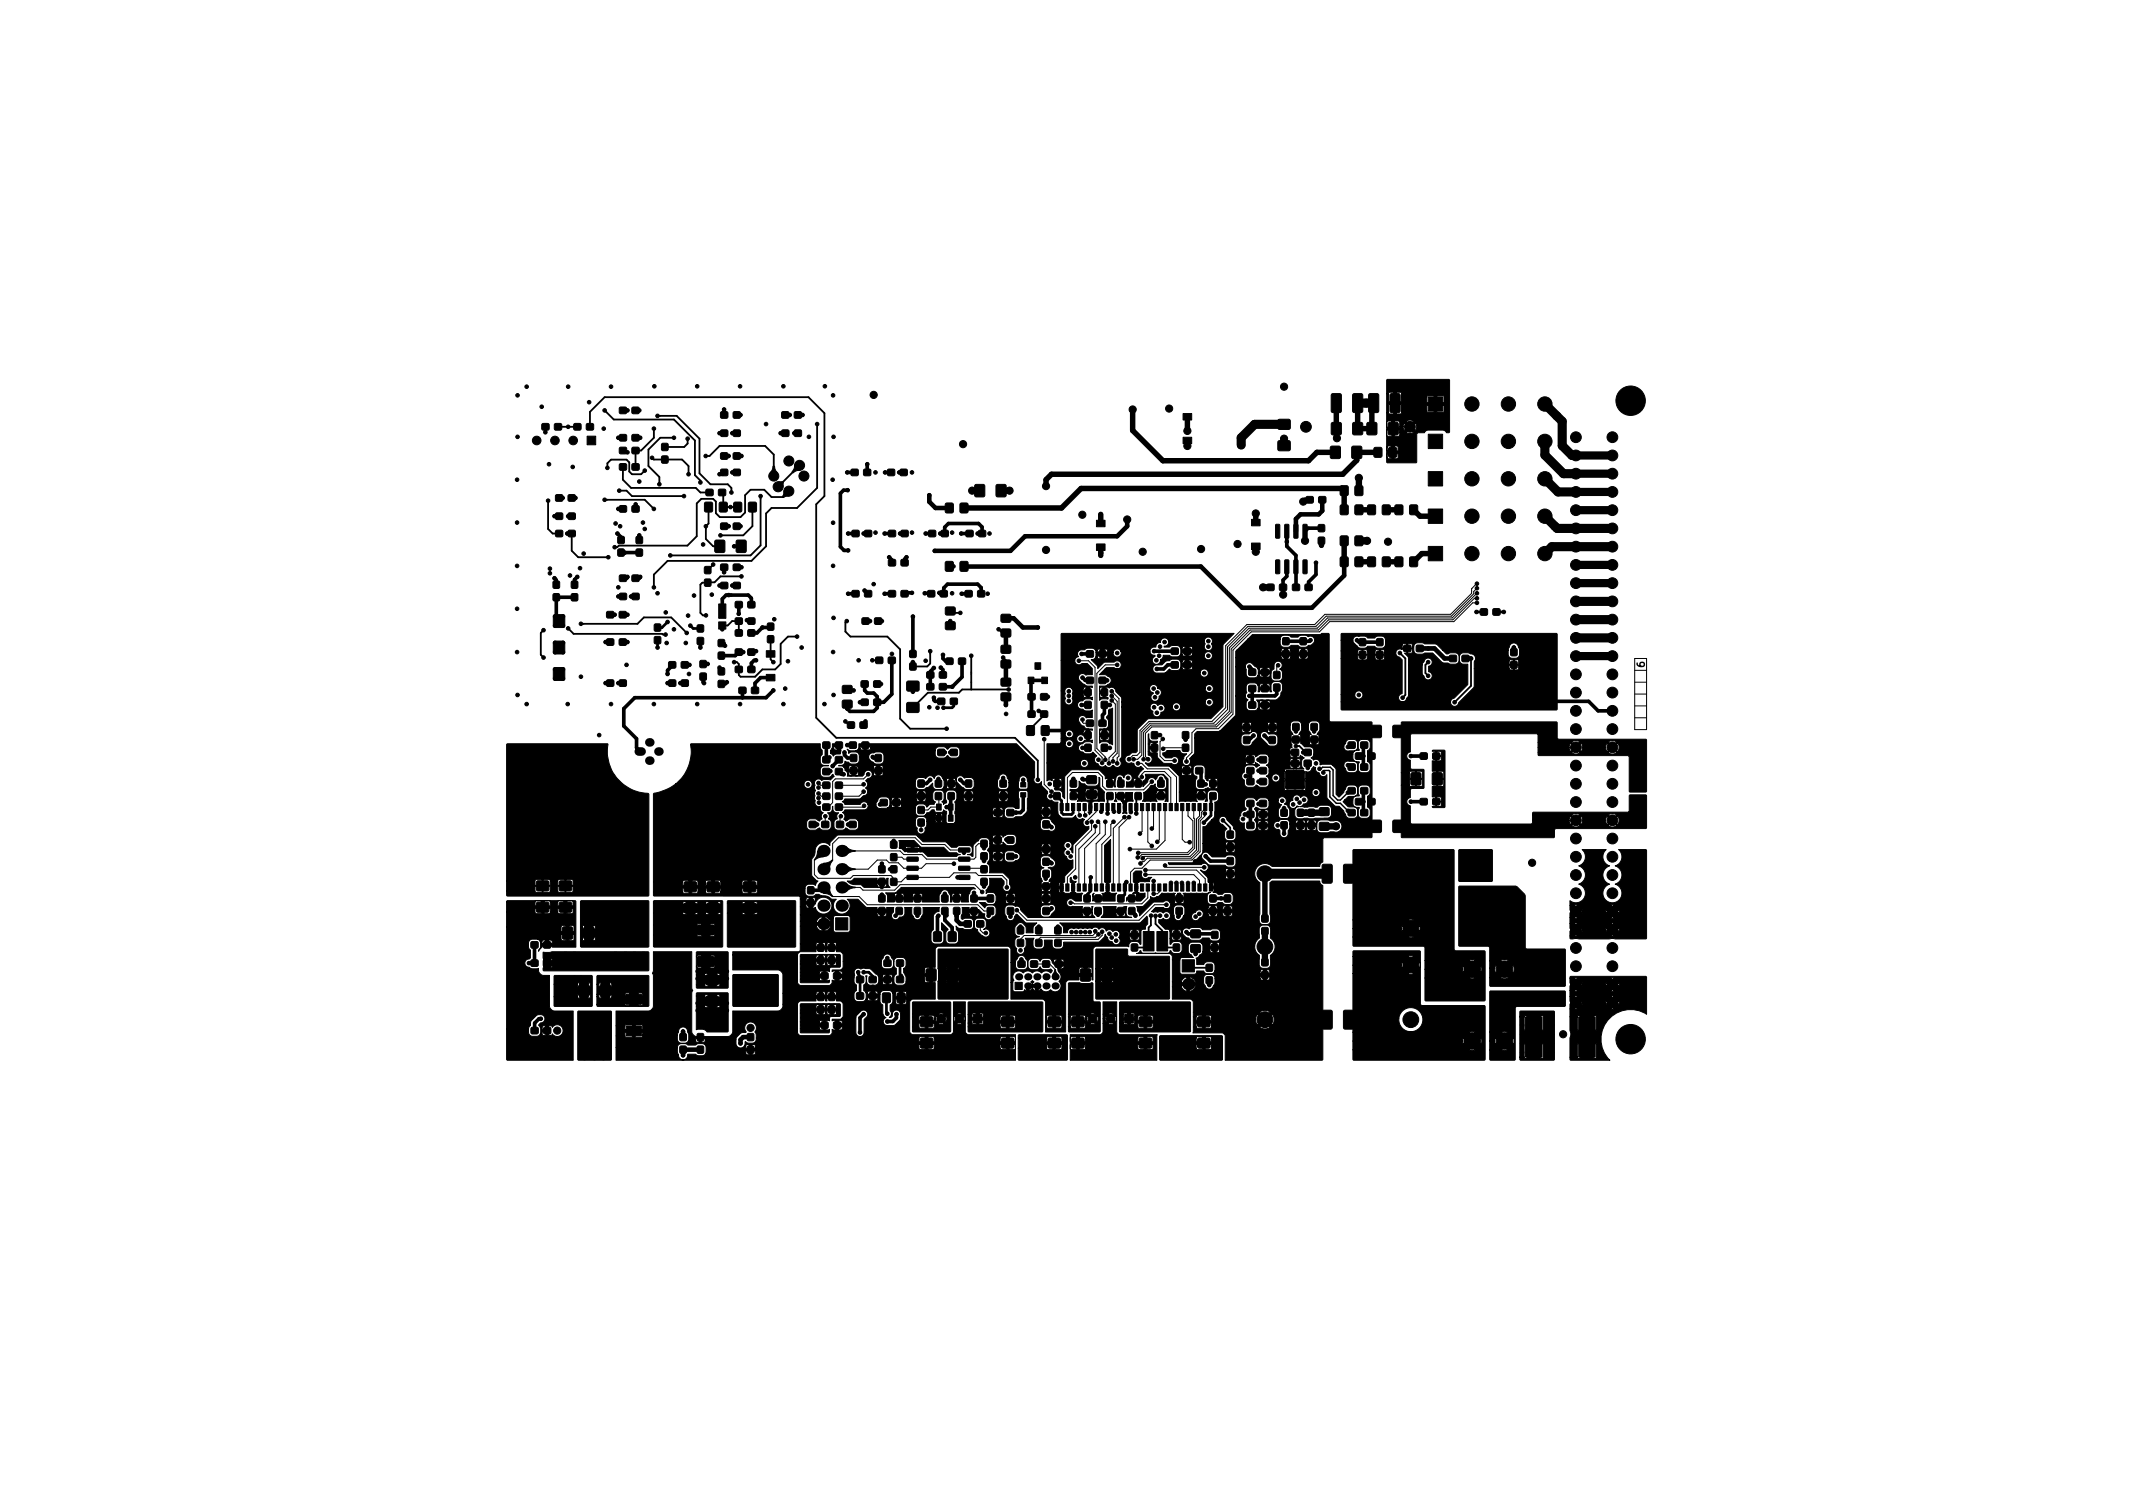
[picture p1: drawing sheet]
<svg xmlns="http://www.w3.org/2000/svg" width="297mm" height="210mm" viewBox="0 0 297 210" stroke-linecap="round" stroke-linejoin="round" font-family="sans-serif">
<defs><g id="words">
<text font-size="1.4" x="229" y="92.9" transform="rotate(-90 229 92.9)">6</text>
</g></defs>
<g fill="#000" stroke="#000" stroke-width=".14">
<path d="M75.5 59h.9l.1 .2-.1 .6-.2 .1h-.7l-.1-.2zM77.3 59h.8l.1 .2v.6l-.2 .1h-.7l-.1-.2zM79.9 59h.9l.1 .2v.6l-.2 .1h-.7l-.1-.2zM81.7 59h.9l.1 .2-.1 .6-.2 .1h-.7l-.1-.2zM86.3 56.7h.9l.1 .2-.1 .6-.2 .1h-.7l-.1-.2zM88 56.7h.9l.1 .2v.6l-.2 .1h-.7l-.1-.2zM100.4 59.9h.9l.1 .2-.1 .6-.2 .1-.7-.1-.1-.1zM100.4 57.4h.9l.1 .1-.1 .7-.2 .1-.7-.1-.1-.2zM102.1 59.9h.9l.1 .2v.6l-.2 .1-.7-.1-.1-.1zM102.1 57.4h.9l.1 .1v.7l-.2 .1-.7-.1-.1-.2zM108.9 59.9h.9l.1 .2-.1 .6-.2 .1-.7-.1-.1-.1zM108.9 57.4h.9l.1 .1-.1 .7-.2 .1-.7-.1-.1-.2z"/>
<path d="M110.7 59.9h.8l.1 .2v.6l-.2 .1-.7-.1-.1-.1zM110.7 57.4h.8l.1 .1v.7l-.2 .1-.7-.1-.1-.2zM164.8 57.6h1.2v.9h-1.2zM178 58.4h.2h1.4l.1 .2-.1 1.1-.2 .1-1.4-.1-.1-.2zM185.5 58.9l1.1-.1 .1 .1 .1 1.4-.1 .2-1.1 .1-.2-.1v-1.4zM185.5 54.9l1.1-.1 .2 .2v2.2l-.2 .2-1 .1-.2-.2zM188.4 58.9l1.1-.1 .2 .1 .1 1.4-.1 .2-1.1 .1-.2-.1v-1.4zM188.4 54.9l1.2-.1 .2 .2v2.2l-.2 .2-1 .1-.2-.2zM190.4 58.9l1.1-.1 .2 .1 .1 1.4-.1 .2-1.1 .1-.2-.1-.1-1.4zM190.7 54.9l1.1-.1 .2 .2v2.2l-.1 .2-1.1 .1-.2-.2zM193.4 58.9l1.1-.1 .2 .1v1.4l-.1 .2-1 .1-.2-.1-.1-1.4zM193.6 54.9l1.2-.1 .2 .2v2.2l-.2 .2-1 .1-.2-.2z"/>
<path d="M198.9 55.3h2v2h-2zM193.1 52.9l.1-.1h8.6l.1 .1v7.3l-.1 .1h-.4l-.2-.3-.3-.1h-2l-.3 .1-.2 .3h-1l-.1 .1v4h-.1h-4h-.1v-.7l.2 .2h.4v-.7h.4l.1 .7h.4l.1-.2v-.5h-1.5l-.1 .5v-1.4l.1 .5h.5v-.7h.4v.7h.6v-.5l-.2-.2h-1.2l-.2 .2v-1.7l.2 .1h.5v-.8h.4l.1 .8h.6v-.5h1l.4 .2 .5-.2-.5-.5-.4 .5h-1v-.3h-1.7l-.1 .7v-1.8l.1 .7h.6v-.8h.4v.8l1.2-.1 .2 .5 .5-.5h.5l.5 .5 .2-.4-.2-.6-.5 .5h-.5l-.5-.5-.2 .5h-.5v-.7h1l.4 .5 .5-.5-.2-.2h-.4l-.3 .2-2.6-.1-.2 .2v-1.3h.3l.1 .1h.6v-1.3h.4v1.3h.6l.1-.3h3.5l.2 .1h.8v-1h.4v1h.8l.2-.1v-.8l-2.3-.1-.1 .9h-3.5l-.1-1h-1.7v1.2h-.3v-2.7h.3v1.1h.7v-1.2h.4v1.2h.6l.1-.6h3.5l.1 .8h.9v-1h.4v1h.9l.1-.9-.2-.1h-2l-.2 .2h-3.5v-.5l-.2-.2h-1.5l-.1 .2h-.3zM77.4 68.9h.9l.1 .2-.1 .6-.1 .1h-.8l-.1-.2zM77.4 71.5h.9l.1 .1-.1 .7-.1 .1-.8-.1-.1-.2zM77.4 73.9h.9l.1 .2-.1 .6-.1 .1-.8-.1-.1-.2zM79.2 68.9h.9v.2v.6l-.2 .1h-.7l-.1-.2zM79.2 71.5h.9v.1v.7l-.2 .1-.7-.1-.1-.2zM79.2 73.9h.9v.2v.6l-.2 .1-.7-.1-.1-.2zM81.8 60.7h1.2v1.2h-1.2zM86.1 76.5l.6-.1 .2 .1 .1 .7-.1 .2-.7 .1-.1-.1zM86.1 74.7h.6l.2 .1 .1 .7-.1 .2h-.7l-.1-.1zM86.3 60.5h.9l.1 .2-.1 .6-.2 .1h-.7l-.1-.2z"/>
<path d="M86.3 70.5l.9-.1 .1 .2-.1 .6-.2 .1h-.7l-.1-.2zM86.3 62.3h.9l.1 .2-.1 .6-.2 .1h-.7l-.1-.2zM86.3 64.6h.9l.1 .2-.1 .6-.2 .1-.7-.1-.1-.1zM88 60.5h.9l.1 .2v.6l-.2 .1h-.7l-.1-.2zM88 70.5l.9-.1 .1 .2v.6l-.2 .1h-.7l-.1-.2zM88 62.3h.9l.1 .2v.6l-.2 .1h-.7l-.1-.2zM88 64.6h.9l.1 .2v.6l-.2 .1-.7-.1-.1-.1zM88.6 76.5l.7-.1 .1 .1 .1 .7-.1 .2-.6 .1-.2-.1zM88.6 74.7h.7l.1 .1 .1 .7-.1 .2h-.6l-.2-.1zM92.2 63.5h.6l.2 .1 .1 .7-.1 .2h-.7l-.1-.1zM92.2 61.8l.6-.1 .2 .1 .1 .7-.1 .2-.7 .1-.1-.1zM98.1 78.9h.7h.2v.8l-.1 .2h-.6l-.2-.1z"/>
<path d="M98.2 70l.8-.1 .2 .1v1.1v.1l-.9 .1-.1-.1-.1-1zM98.4 68.2h.8l.1 .1v.7h-.2h-.7l-.1-.2zM99.6 75.3l1.1-.1 .2 .1 .1 1.4-.1 .2h-1.1h-.2l-.1-1.5zM100.1 68.2h.9l.1 .1-.1 .7h-.2h-.7l-.1-.2zM100.2 70l.8-.1 .2 .1 .1 1.1-.1 .1-.8 .1-.2-.1-.1-1zM100.4 65.4h.9l.1 .1-.1 .7-.2 .1-.7-.1-.1-.2zM100.4 63.1h.9l.1 .2-.1 .6-.2 .1-.7-.1-.1-.2zM100.4 72.9h.9l.1 .1-.1 .7h-.2h-.7l-.1-.2zM100.4 78.6h.9l.1 .2-.1 .6-.2 .1-.7-.1-.1-.2zM102.1 65.4h.9l.1 .1v.7l-.2 .1-.7-.1-.1-.2zM102.1 63.1h.9l.1 .2v.6l-.2 .1-.7-.1-.1-.2zM102.1 72.9h.9l.1 .1v.7h-.2h-.7l-.1-.2z"/>
<path d="M102.1 78.6h.9l.1 .2v.6l-.2 .1-.7-.1-.1-.2zM102.2 70l.9-.1 .2 .1v1.1l-.1 .1-.8 .1-.2-.1v-1zM102.6 75.3l1.1-.1 .2 .1v1.4l-.1 .2h-1h-.2l-.1-1.5zM104.3 70l.8-.1 .2 .1 .1 1.1-.1 .1-.8 .1-.2-.1-.1-1zM107.6 64.9h.3l.1 .5 .2 .4-.4 .8-.5-.8 .2-.4zM108.4 67.1h.5l.2 .1v.6l-1 .2zM109.2 68.4l.9-.2-.3 .9h-.4l-.3 .2-.1-.2 .1-.3zM110.7 64.8l.9-.2-.3 .9-.4 .1-.4 .2-.2-.1 .3-.4zM118.6 65.4h.9v.1v.7l-.2 .1-.7-.1-.1-.2zM118.7 73.9h.9l.1 .2-.1 .6-.2 .1-.7-.1-.1-.2zM120.3 65.4h.9l.1 .1-.1 .7-.1 .1-.8-.1-.1-.2zM120.4 73.9h.9l.1 .2v.6l-.2 .1-.7-.1-.1-.2z"/>
<path d="M123.6 65.4h.9l.1 .1v.7l-.2 .1-.7-.1-.1-.2zM123.8 77.9h.9v.2v.6l-.2 .1h-.7l-.1-.2zM123.8 73.9h.9v.2v.6l-.2 .1-.7-.1-.1-.2zM125.4 65.4h.9l.1 .1-.1 .7-.2 .1-.7-.1-.1-.2zM125.5 77.9h.9l.1 .2-.1 .6-.1 .1h-.8l-.1-.2zM125.5 73.9h.9l.1 .2-.1 .6-.1 .1-.8-.1-.1-.2zM129.4 73.9h.8l.1 .2v.6l-.2 .1-.7-.1-.1-.2zM131.1 73.9h.9l.1 .2-.1 .6-.2 .1-.7-.1-.1-.2zM131.7 70.1l.8-.1 .2 .1 .1 1.1-.1 .2h-.8l-.2-.1-.1-1zM131.7 78.2h.8l.2 .1 .1 1-.1 .2-.8 .1-.2-.1-.1-1.1zM133.7 70.1l.9-.1 .2 .1v1.1l-.1 .2h-.8l-.2-.1v-1zM133.7 78.2h.9l.2 .1v1l-.1 .2-.8 .1-.2-.1v-1.1z"/>
<path d="M134.6 73.9h.9v.2v.6l-.2 .1-.7-.1-.1-.2zM135.8 67.5l1.1-.1 .2 .1v1.4v.2l-1.1 .1-.2-.1-.1-1.4zM136.3 73.9h.9l.1 .2-.1 .6-.1 .1-.8-.1-.1-.2zM138.8 67.5l1.1-.1 .2 .1v1.4l-.1 .2-1.1 .1-.1-.1-.1-1.4zM152.7 72.4h1.2v.9h-1.2zM152.7 75.7h1.2v.9h-1.2zM164.8 60.9h1.2v.9h-1.2zM174.3 72.3h1.2v.9h-1.2zM174.3 75.6h1.2v.9h-1.2zM177.7 78l.4-.1 .1 .2v1.7l-.1 .1h-.4l-.1-.1zM177.7 73h.4l.1 .1v1.7l-.1 .1h-.4l-.1-.1zM178.9 78l.5-.1 .1 .2v1.7l-.1 .1h-.4l-.1-.1z"/>
<path d="M178.9 73h.5l.1 .1v1.7l-.1 .1h-.4l-.1-.1zM178 61.4l.2-.1 1.4 .1 .1 .2-.1 1.1-.2 .1-1.4-.1-.1-.2zM180.2 78l.4-.1 .2 .2v1.7l-.2 .1h-.3l-.1-.1zM180.2 73h.4l.2 .1v1.7l-.2 .1h-.3l-.1-.1zM181.5 78l.4-.1 .1 .2v1.7l-.1 .1h-.3l-.2-.1zM181.5 73h.4l.1 .1v1.7l-.1 .1h-.3l-.2-.1zM181.9 69.2h.9l.1 .2v.6l-.2 .1-.8-.1v-.2zM183.6 74.8h.7l.1 .1 .1 .7-.1 .2h-.6l-.2-.1zM183.6 73.1l.7-.1 .1 .1 .1 .7-.1 .2-.6 .1-.2-.1zM183.7 69.2h.9l.1 .2-.1 .6-.2 .1-.7-.1-.1-.2zM185.3 62.2l1.1-.1 .2 .1 .1 1.4-.1 .2-1.1 .1-.2-.1v-1.4zM186.7 77.6l.8-.1 .2 .1 .1 1.1-.1 .2h-.8l-.2-.1-.1-1z"/>
<path d="M186.7 67.7l.8-.1 .2 .1 .1 1.1-.1 .2h-.8l-.2-.1-.1-1zM186.7 74.7l.8-.1 .2 .1 .1 1.1-.1 .1-.8 .1-.2-.1-.1-1zM186.7 70.4l.8-.1 .2 .1 .1 1-.1 .2-.8 .1-.2-.1-.1-1.1zM188.3 62.2l1.1-.1 .2 .1 .1 1.4-.1 .2-1.1 .1-.2-.1-.1-1.4zM188.7 77.6l.9-.1 .2 .1v1.1l-.1 .2h-.8l-.2-.1v-1zM188.7 67.7l.9-.1 .2 .1v1.1l-.1 .2h-.8l-.2-.1v-1zM188.7 74.7l.9-.1 .2 .1v1.1l-.1 .1-.8 .1-.2-.1v-1zM188.7 70.4l.9-.1 .2 .1v1l-.1 .2-.8 .1-.2-.1v-1.1zM190.5 70.4l.8-.1 .2 .1 .1 1-.1 .2-.8 .1-.2-.1-.1-1.1zM190.5 77.6l.8-.1 .2 .1 .1 1.1-.1 .2h-.8l-.2-.1-.1-1zM191.4 62.4l.8-.1 .2 .1 .1 1-.1 .2-.8 .1-.2-.1-.1-1.1zM192.5 70.4l.9-.1 .2 .1v1l-.1 .2-.8 .1-.2-.1v-1.1z"/>
<path d="M192.5 77.6l.9-.1 .2 .1v1.1l-.1 .2h-.8l-.2-.1v-1zM193.4 62.4l.9-.1 .2 .1v1l-.1 .2-.8 .1-.2-.1v-1.1zM194.3 70.4l.8-.1 .2 .1 .1 1-.1 .2-.8 .1-.2-.1-.1-1.1zM194.3 77.6l.8-.1 .2 .1 .1 1.1-.1 .2h-.8l-.2-.1-.1-1zM196.4 70.4l.8-.1 .2 .1v1l-.1 .2-.8 .1-.2-.1v-1.1zM196.4 77.6l.8-.1 .2 .1v1.1l-.1 .2h-.8l-.2-.1v-1zM198.9 76.1h2v2h-2zM198.9 70.9h2v2h-2zM198.9 65.7h2v2h-2zM198.9 60.5h2v2h-2zM77.1 82.7l.6-.1 .2 .1v.8v.1l-.7 .1-.2-.1zM77.1 81l.6-.1 .2 .1v.7v.2h-.7h-.2z"/>
<path d="M77.1 89.3h1.3l.2 .1 .1 1.4-.1 .2-1.3 .1-.2-.1v-1.5zM77.1 93l1.3-.1 .2 .1 .1 1.5-.1 .2h-1.3h-.2v-1.5zM77.1 85.7l1.3-.1 .2 .1 .1 1.4-.1 .2-1.3 .1-.2-.1v-1.5zM79.6 82.7l.6-.1 .2 .1 .1 .8-.1 .1-.6 .1-.2-.1zM79.6 81l.6-.1 .2 .1 .1 .7-.1 .2h-.6h-.2zM84.5 89h.9l.1 .2-.1 .6-.1 .1-.8-.1v-.2zM84.5 94.7h.9l.1 .2-.1 .6-.1 .1-.8-.1v-.1zM84.5 85.2h.9l.1 .2-.1 .6-.1 .1-.8-.1v-.2zM86.3 89h.9l.1 .2-.1 .6-.2 .1-.7-.1-.1-.2zM86.3 94.7h.9l.1 .2-.1 .6-.2 .1-.7-.1-.1-.1zM86.3 85.2h.9l.1 .2-.1 .6-.2 .1-.7-.1-.1-.2zM86.3 80.1h.9l.1 .2-.1 .6-.2 .1-.7-.1-.1-.2z"/>
<path d="M86.3 82.6h.9l.1 .2-.1 .6-.2 .1h-.7l-.1-.2zM88 80.1h.9l.1 .2v.6l-.2 .1-.7-.1-.1-.2zM88 82.6h.9l.1 .2v.6l-.2 .1h-.7l-.1-.2zM91.2 88.7l.6-.1 .2 .1v.7v.2l-.7 .1-.2-.1zM91.2 86.9h.6h.2v.8v.2h-.7l-.2-.1zM93.2 92.2h.9v.1v.7l-.2 .1-.7-.1-.1-.2zM93.2 94.7h.9v.2v.6l-.2 .1-.7-.1-.1-.1zM94.9 92.2h.9l.1 .1-.1 .7-.1 .1-.8-.1-.1-.2zM94.9 94.7h.9l.1 .2-.1 .6-.1 .1-.8-.1-.1-.1zM97.1 88.8l.7-.1 .2 .1v.7l-.1 .2-.6 .1-.2-.1zM97.1 87.1l.7-.1 .2 .1v.7l-.1 .2h-.6l-.2-.1zM97.5 92l.7-.1 .1 .1 .1 .8-.1 .1-.6 .1-.2-.1z"/>
<path d="M97.5 93.8l.7-.1 .1 .1 .1 .7-.1 .2h-.6h-.2zM98.1 80.7l.7-.1 .2 .1v.7l-.1 .2-.6 .1-.2-.1zM100.1 84.1h1v2h-1zM100.1 86.6h1v1h-1zM100.1 90.8h.6l.2 .1v.7l-.1 .2h-.6l-.2-.1zM100.1 89.1l.6-.1 .2 .1v.7l-.1 .2-.6 .1-.2-.1zM100.1 94.8l.6-.1 .2 .1v.7l-.1 .2-.6 .1-.2-.1zM100.1 93h.6h.2v.8l-.1 .2h-.6l-.2-.1zM100.4 81.1h.9l.1 .2-.1 .6-.2 .1-.7-.1-.1-.1zM102.1 81.1h.9l.1 .2v.6l-.2 .1-.7-.1-.1-.1zM102.4 86.1h.9l.1 .1v.7l-.2 .1-.8-.1v-.2zM102.4 92.8h.9l.1 .2v.6l-.2 .1-.8-.1v-.2z"/>
<path d="M102.4 87.7h.9l.1 .2v.6l-.2 .1h-.8v-.2zM102.4 90.4h.9l.1 .2v.6l-.2 .1-.8-.1v-.2zM102.4 83.8h.9l.1 .2v.6l-.2 .1-.8-.1v-.2zM102.9 95.7h.9l.1 .2v.6l-.2 .1h-.7l-.1-.2zM104.2 86.1h.9l.1 .1-.1 .7-.2 .1-.7-.1-.1-.2zM104.2 92.8h.9l.1 .2-.1 .6-.2 .1-.7-.1-.1-.2zM104.2 87.7h.9l.1 .2-.1 .6-.2 .1h-.7l-.1-.2zM104.2 90.4h.9l.1 .2-.1 .6-.2 .1-.7-.1-.1-.2zM104.2 83.8h.9l.1 .2-.1 .6-.2 .1-.7-.1-.1-.2zM104.7 95.7h.9l.1 .2-.1 .6-.2 .1h-.7l-.1-.2zM106.9 86.8l.7-.1 .1 .1 .1 .7-.1 .2-.6 .1-.2-.1zM106.9 88.6l.7-.1 .1 .1 .1 .7-.1 .2h-.6l-.2-.1z"/>
<path d="M106.7 90.6h1.2v.9h-1.2zM106.7 93.9h1.2v.9h-1.2zM117.4 97.5h.1h1.1l.1 .2-.1 .8-.2 .1h-1l-.1-.2zM117.4 95.5l.1-.1 1.1 .1 .1 .2-.1 .8-.2 .1-1-.1-.1-.2zM118.7 82.3h.9l.1 .1-.1 .7h-.2h-.7l-.1-.2zM120 97.4h.8l.1 .1v.7l-.2 .1-.7-.1-.1-.2zM120 94.8h.8l.1 .2v.6l-.2 .1h-.7l-.1-.2zM120.1 86.1h.9l.1 .1-.1 .7-.2 .1-.7-.1-.1-.2zM120.4 82.3h.9l.1 .1v.7h-.2h-.7l-.1-.2zM121.7 97.4h.9l.1 .1-.1 .7-.2 .1-.7-.1-.1-.2zM121.7 94.8h.9l.1 .2-.1 .6-.2 .1h-.7l-.1-.2zM121.8 86.1h.9l.1 .1v.7l-.2 .1-.8-.1v-.2z"/>
<path d="M122 91.5h.9l.1 .2-.1 .6-.2 .1h-.7l-.1-.2zM123.7 91.5h.9l.1 .2v.6l-.2 .1h-.7l-.1-.2zM123.8 82.3h.9v.1v.7h-.2h-.7l-.1-.2zM125.5 82.3h.9l.1 .1-.1 .7h-.1h-.8l-.1-.2zM126.7 92.3h.7l.1 .1 .1 .7-.1 .2h-.6l-.2-.1zM126.7 90.6l.7-.1 .1 .1 .1 .7-.1 .2-.6 .1-.2-.1zM126.3 94.9l.2-.1 1.4 .1 .1 .2-.1 1.1h-.1h-1.5v-.2zM126.3 97.9l.2-.1 1.4 .1 .1 .1-.1 1.1-.1 .1h-1.5v-.2zM129.1 93.6h.9l.1 .1-.1 .7h-.2h-.7l-.1-.2zM129.1 95.2h.9l.1 .2-.1 .6-.2 .1-.7-.1-.1-.1zM129.2 82.3h.9l.1 .1v.7h-.2h-.8v-.2zM130.6 97.3l.9-.1 .1 .2-.1 .6-.1 .1h-.8v-.2z"/>
<path d="M130.8 93.6h.9l.1 .1v.7h-.2h-.7l-.1-.2zM130.8 95.2h.9l.1 .2v.6l-.2 .1-.7-.1-.1-.1zM131 82.3h.9l.1 .1-.1 .7h-.2h-.7l-.1-.2zM131.8 91.7l.9-.1v.2v.7h-.2h-.7l-.1-.2zM131.7 86.6h.2h1l.1 .2v.8l-.2 .1-1.1-.1-.1-.1zM131.7 84.6l.2-.1 1 .1 .1 .2v.8l-.2 .1-1.1-.1-.1-.2zM132.4 97.3l.9-.1 .1 .2-.1 .6-.2 .1h-.7l-.1-.2zM133.5 91.7l.9-.1 .1 .2-.1 .7h-.1h-.8l-.1-.2zM134.4 82.3h.9l.1 .1v.7h-.2h-.8v-.2zM136.2 82.3h.9l.1 .1-.1 .7h-.2h-.7l-.1-.2zM139.5 87.6h.1h1.1l.1 .2-.1 .8-.2 .1h-1l-.1-.2zM139.5 85.6l.1-.1 1.1 .1 .1 .2-.1 .8-.2 .1-1-.1-.1-.2z"/>
<path d="M139.5 92l.1-.1h1.1l.1 .2-.1 .8-.2 .1h-1l-.1-.2zM139.5 89.9l.1-.1 1.1 .1 .1 .2-.1 .8-.2 .1-1-.1-.1-.2zM139.5 96.5h.1h1.1l.1 .2-.1 .8-.2 .1-1-.1-.1-.1zM139.5 94.5l.1-.1 1.1 .1 .1 .2-.1 .8-.2 .1-1-.1-.1-.2zM143.2 99h.9l.1 .2-.1 .6-.2 .1h-.7l-.1-.2zM143.2 96.6h.9l.1 .2-.1 .6-.2 .1-.7-.1-.1-.1zM143.2 94.3h.8v.9h-.8zM144.1 92.3h.8v.9h-.8zM144.9 99h.9l.1 .2v.6l-.2 .1h-.7l-.1-.2zM144.9 96.6h.9l.1 .2v.6l-.2 .1-.7-.1-.1-.1zM145.1 94.3h.8v.9h-.8zM151.1 95.9h.6l.2 .1 .1 .7-.1 .2h-.6l-.2-.1z"/>
<path d="M151.1 97.7l.6-.1 .2 .1 .1 .7-.1 .2-.6 .1-.2-.1zM151.3 94.3h.9l.1 .2v.6l-.2 .1h-.8v-.2zM151.3 90.6h.9l.1 .2v.6l-.2 .1h-.8v-.2zM153.1 94.3h.9l.1 .2-.1 .6-.2 .1h-.7l-.1-.2zM153.1 90.6h.9l.1 .2-.1 .6-.2 .1h-.7l-.1-.2zM153.4 95.9h.6l.2 .1 .1 .7-.1 .2h-.6l-.2-.1zM153.4 97.7l.6-.1 .2 .1 .1 .7-.1 .2-.6 .1-.2-.1zM163.1 92.2h.9l.1 .1v.7l-.2 .1-.7-.1-.1-.2zM163.1 90.3h.9l.1 .1v.7h-.2h-.7l-.1-.2zM164.9 92.2h.9l.1 .1-.1 .7-.2 .1-.7-.1-.1-.2zM164.9 90.3h.9l.1 .1-.1 .7h-.2h-.7l-.1-.2zM147.8 88.3l.1-.1h24l-1.6 1.6v8.6l-1.7 1.7h-8.7l-1.5 1.5v3l-.2 .2h-.6l-.3 .4a.59 .59 0 0 0-.6 .7 .59 .59 0 0 0 .9 .3l.3 .1a.57 .57 0 0 0 .4 .5 .57 .57 0 0 0 .6-.1l.4 .4-.6 .5-.2 .4v.4l-.6 .1-.1 .4h1.3l.1-.2a.57 .57 0 0 0 .3-.8l2.5-.1 .7 .7v3.1h-.5l.1-.2v-.4h-1.2l-.1 .4 .2 .2h-.2h-1.9l.2-.4-.1-.8 1.8-.1 .1 .4h.4v-.5h.4v.5l.4-.1v-.3l-.2-.2h-.9l-.2 .2h-1.6l1-.9 .3-.1 .2-.2a.62 .62 0 0 0 .5 .8h.6l.4-.2 .1-.9-.2-.4a.64 .64 0 0 0-.6-.5 .64 .64 0 0 0-.7 .5l-.1 .2a.57 .57 0 0 0-.7-.3 .57 .57 0 0 0-.4 .6l-.6 .6-.1-.2h-1.2l-.1 .3h-1l.1-.8a.57 .57 0 0 0 .7-.3 .57 .57 0 0 0-.4-.7 .57 .57 0 0 0-.7 .5 .62 .62 0 0 0-.7-.4 .62 .62 0 0 0-.5 .7v1h-.1v-.3h-.9l.1-.9h.3v.5h.5v-.5h-1.1l-.2 .1v-.5l-.8-.8h-3.8l-1 1v3l-.3-.3v-.3a.56 .56 0 0 0-.6-.6h-.4l-.2-.2h.2v-.5h.4v.5h.4l.1-.5h-.9v-.9h.4v.5h.4l.1-.3-.1-.2h-1.1l-.2 .1v.2l-.4-.1-.3 .1v-2.5h4.6v.1a.57 .57 0 0 0 .9 .5 .57 .57 0 0 0 0-1 .57 .57 0 0 0-.9 .4h-4.6v-2.6l2.5-.1v.1a.57 .57 0 0 0 .9 .4 .57 .57 0 0 0 0-.9 .57 .57 0 0 0-.9 .4h-.6l.1-.1v-.6h2.1a.58 .58 0 0 0 .5 .6 .58 .58 0 0 0 .6-.3l.3-.1v-.4h-.3a.57 .57 0 0 0-.6-.3 .57 .57 0 0 0-.5 .5h-2.1v-.6h.5v.1a.57 .57 0 0 0 .8 .4 .57 .57 0 0 0 .2-.9h1.5l.1 .4h.4v-.5h-.3l-.2 .1h-1.5a.57 .57 0 0 0-.6-.1 .57 .57 0 0 0-.4 .5h-.5v-6h.5l.1 .4-.1 .4 .1 .2a.57 .57 0 0 0 .1 .8 .57 .57 0 0 0 .7 0 .57 .57 0 0 0 .1-.8l.1-.3h1.4l.2 .2h.3v-.5h-.4l-.1 .3h-1.4l-.1-.3a.56 .56 0 0 0 0-.7h1.5l.1 .3h.4v-.5h-.3l-.2 .2h-1.5a.57 .57 0 0 0-.6-.2 .57 .57 0 0 0-.4 .5h-.5v-4.3h1.9v.2a.57 .57 0 0 0 .4 .4 .57 .57 0 0 0 .6-.1h.7l.7 .7v.8l-.9 .1a.58 .58 0 0 0-.8-.1 .58 .58 0 0 0-.1 .8l.5 .5 .5 .3h.8v.2h-.4v1.4h.4v.3l-.2-.1h-.6l-.5 .3a.61 .61 0 0 0-.8 .6 .61 .61 0 0 0 .8 .5l.5 .3h.6l.2-.1v1l-.8 .1a.59 .59 0 0 0-1-.2 .59 .59 0 0 0 .1 .9l.3 .3 .3 .1 .3 .4h.8v.2h-.4v1.3h.4v.4l-.2-.1h-.7l-.4 .3a.58 .58 0 0 0-.6 .6 .58 .58 0 0 0 .6 .5l.5 .3h.6l.3-.3 .5 .6a.6 .6 0 0 0-.3 .6 .6 .6 0 0 0 .5 .5 .57 .57 0 0 0 .5 .4 .57 .57 0 0 0 .5-.2 .58 .58 0 0 0 1 0h.2a.57 .57 0 0 0 .8 .1 .57 .57 0 0 0 .1-.8v-.2l.2-.4v-6.9h4v.4l.4 .3a.57 .57 0 0 0 .4 .7 .57 .57 0 0 0 .7-.6 .57 .57 0 0 0 .5-.8h1.1v.1a.57 .57 0 0 0 .8 .4 .57 .57 0 0 0 0-1 .57 .57 0 0 0-.8 .5l-1.1-.1a.57 .57 0 0 0-1-.1 .57 .57 0 0 0-.6-.3 .57 .57 0 0 0-.4 .5h-4v-.7h11.6v.1a.57 .57 0 0 0 .9 .5 .57 .57 0 0 0 0-1 .57 .57 0 0 0-.9 .4h-11.6v-.6l-.8-.8-.2-.5h4.9a.66 .66 0 0 0 .5 .7v.1a.58 .58 0 0 0-.2 .7 .58 .58 0 0 0 .7 .3 .58 .58 0 0 0 .3-.7 .6 .6 0 0 0 .3-.6 .6 .6 0 0 0-.5-.5h6.6v.1a.57 .57 0 0 0 .9 .5 .57 .57 0 0 0 0-1 .57 .57 0 0 0-.9 .4h-6.6v-.1a.57 .57 0 0 0-.6-.4 .57 .57 0 0 0-.5 .5h-4.9l-.3-.1-.4 .1-.2-.1h-.3v1.4h.3v.1v.2l-.8-.1-.4 .2v-.6l.2 .2h.3v-.5h-.4l-.1 .3v-1l.1 .3h.4v-.5h-.3l-.2 .2v-.4h.8l.4-.2a.6 .6 0 0 0 .4-.6 .6 .6 0 0 0-.5-.6l-.3-.1-.8-.1 .8-.8h6.6a.57 .57 0 0 0 .6 .6h6v.1a.57 .57 0 0 0 .9 .4 .57 .57 0 0 0 0-1 .57 .57 0 0 0-.9 .5h-4.8l.6-.6 .4 .3h.7l.4-.3h.2l.2 .1h.3v-.4h.4l.1 .4h.3l.2-.1-.1-.3h-1.3l-.1 .3h-.2v-1h.2l.1 .3h.4v-.4h.4v.4h.5l.1-.3-.2-.2h-1.1l-.2 .2h-.2l-.4-.3h-.8l-.3 .2-.6 .1-.5 .5h-.7a.57 .57 0 0 0-.6 .5h-6.6l.2-.1h1.1a.57 .57 0 0 0 .8-.1 .57 .57 0 0 0 0-.7 .57 .57 0 0 0-.8 0h-1.4l-.9 .9-.1-.4-.8-.9h.3l.3-.3h.2l.2 .2h.3v-.5h.4l.1 .5h.3l.1-.1v-.4h-1.3l-.1 .3h-.2v-.6h2.4v.1a.57 .57 0 0 0 .7 .5 .57 .57 0 0 0 .4-.8h4l.1 .1a.6 .6 0 0 0 .7 .4l-.1 .2a.58 .58 0 0 0-.3 .7 .58 .58 0 0 0 .6 .4 .58 .58 0 0 0 .5-.7 .57 .57 0 0 0 .4-.6h.9l.4 .3h.7l.4-.4h.2l.2 .2h.3v-.4h.4l.1 .4h2.1a.57 .57 0 0 0 .8 .5 .57 .57 0 0 0 .2-.9 .57 .57 0 0 0-1 .2v.2h-1.7v-.4h-1.3l-.1 .2h-.2v-.9h.2l.1 .3h.4v-.4h.4v.4h.5l.1-.3-.2-.2h-1.1l-.2 .2h-.2l-.4-.3h-.8l-.3 .2h-.8v-.1a.57 .57 0 0 0 .6-.8h5v.1a.44 .44 0 0 1 0 .7 .58 .58 0 0 0 .8 .6 .58 .58 0 0 0 .2-1 .57 .57 0 0 0-.2-.9 .57 .57 0 0 0-.8 .5h-5v-.1a.57 .57 0 0 0-.7-.2 .57 .57 0 0 0-.4 .6 .57 .57 0 0 0-.6 .6 .64 .64 0 0 0-.9 .6h-4a.57 .57 0 0 0-.6-.3 .57 .57 0 0 0-.5 .5h-2.4v-.3h.2l.1 .3h.4v-.5h.4v.5h.5v-.4l-.1-.1h-1.1l-.2 .2h-.2l-.4-.3h-.7l-.5 .2h-.4a.57 .57 0 0 0-.5 .3 .57 .57 0 0 0 .1 .6 .57 .57 0 0 0-.5 .5h-1.9z"/>
<path d="M173.9 93.2h.9l.1 .2v.6l-.2 .1-.8-.1v-.2zM173.9 97.8l.9-.1 .1 .2v.7h-.2h-.8v-.2zM173.9 95.5h.9l.1 .1v.7l-.2 .1-.8-.1v-.2zM175.7 93.2h.9l.1 .2-.1 .6-.2 .1-.7-.1-.1-.2zM175.7 97.8l.9-.1 .1 .2-.1 .7h-.2h-.7l-.1-.2zM175.7 95.5h.9l.1 .1-.1 .7-.2 .1-.7-.1-.1-.2zM176.5 81.4h.9v.1v.7l-.2 .1-.7-.1-.1-.2zM177.4 93.5h.6l.2 .1 .1 .7-.1 .2h-.6l-.2-.1zM177.4 95.3l.6-.1 .2 .1 .1 .7-.1 .2-.6 .1-.2-.1zM178.2 81.4h.9l.1 .1-.1 .7-.1 .1-.8-.1v-.2zM178.7 90.6l.6-.1 .2 .1v.7v.2l-.7 .1-.2-.1zM178.7 88.8h.6l.2 .1v.7v.2h-.7l-.2-.1z"/>
<path d="M180 81.4h.9l.1 .1v.7l-.2 .1-.8-.1v-.2zM181.1 90.6l.6-.1 .2 .1 .1 .7-.1 .2-.7 .1-.1-.1zM181.1 88.8h.6l.2 .1 .1 .7-.1 .2h-.7l-.1-.1zM181.8 81.4h.9l.1 .1-.1 .7-.2 .1-.7-.1-.1-.2zM160 102.2v.6l.2 .3 .2 .1h.8v.2l-.2 .1v1.3h.2v.7l.8 .8h1.2a.57 .57 0 0 0 .8 0 .57 .57 0 0 0 0-.8 .57 .57 0 0 0-.8 0h-.9l-.4-.4v-.3h.4l.2-.3h1.8a.55 .55 0 0 0 .6 .5h.4l-.4 .3-.1 .2a.59 .59 0 0 0 0 1 .59 .59 0 0 0 .9-.2h7.7l.2 .1h.3v-.4h-.4l-.1 .3h-7.7l.1-.3-.2-.3 .4-.4h7.4l.1 .3h.4v-.5h-.4l-.1 .2h-7.4l.4-.5v-2h6.4v.6l.2 .3 .3 .2h.5a.55 .55 0 0 0 .6-.5l.6-.7 .1-.3h.4l.1 .3 1 1.1 .9 .1 .4-.4 .1-.7a.56 .56 0 0 0-.6-.6h-.7l-.3-.3a.57 .57 0 0 0-.9 .5h-.4v-.1a.61 .61 0 0 0-.5-.5 .61 .61 0 0 0-.6 .4h-.8l-.3 .2-.1 .4h-6.4v-.6l.3-.4h6.2l.2 .2h.3v-.5h.4v.5h.4l.1-.2h2.2l.1 .2h.3l.1-.5h.4v.5h.3l.1-.1v-.4h-1.3v.3h-2.2l-.1-.3h-1.2l-.1 .3h-3.1l1.1-1h2l.1 .3h.4v-.5h.4v.5h.4l.1-.3h2.2v.3h.5v-.5h.4v.5h.4v-.2h1.9v.8l.4 .6-.3 .1v.4h1.3v-.4l-.2-.1 .3-.6 .1-.8h.9l.1 .8 .3 .6h-.2l-.1 .4 1.3 .1 .1-.4-.3-.1 .4-.6v-.8a.56 .56 0 0 0-.6-.5l-.7 .1-.3 .4h-.9a.56 .56 0 0 0-.6-.5l-.8 .1-.2 .4h-1.9v-.2l-.2-.1h-.9l-.2 .2h-2.2l-.2-.2h-1l-.2 .2h-2l1.2-1.2v-2.7h1.3l.1 .3 .3 .2-.2 .4-.1 .6a.56 .56 0 0 0 .6 .6l.7-.1 .4-.3h.2l.2 .2h.3v-.4h.4l.1 .4h.4l.1-.2-.1-.2h-1.3l-.1 .2h-.2v-.9h.2l.1 .3h.4v-.5h.4v.5h.5l.1-.3-.1-.2h-1.2l-.2 .2h-.2l-.2-.2h2.5l.4-.1 .4-.5 .1-.4 .2-.4v-.6a.56 .56 0 0 0-.6-.6h-.5l-.4 .2-.1 .4 .1 .8h-.2l-.1-.2h-1.3l-.1 .2h-.2v-.9h.2l.1 .3h.4v-.4h.4v.4h.5v-.3l-.1-.2h-1.1l-.2 .2h-.2l-.4-.3h-.9l-.3 .4v.7v.2l-.2 .5h-1.3v-4.1h1.3l.2 .4v.8l.4 .4h.8l.4-.3h.2l.2 .2h.3v-.5h.4l.1 .5 .3-.1 .1-.1v-.3h-1.3l-.1 .3h-.2v-.4h1.8v.6a.56 .56 0 0 0 .6 .5h.7l.3-.3v-.9l-.3-.5a.58 .58 0 0 0 .2-.7 .58 .58 0 0 0-.8-.3 .58 .58 0 0 0-.3 .8v.3l-.3 .2-.1 .3h-1.8v-.6h.2l.1 .3h.4v-.4h.4v.4h.5v-.4l-.1-.1h-1.1l-.2 .2h-.2l-.9-.7a.57 .57 0 0 0-.9 .4h-1.3v-1.2h6.3l.1 .1 .3 .1 .1-.6h.4v.6l.3-.1 .1-.1h1.1l.1 .1 .3 .1 .1-.6h.4v.6l.3-.1 .1-.1v-.4h-1.2l-.1 .4h-1.1v-.4h-1.2l-.1 .4h-6.3v-.9l.1-.2h6.2l.1 .3h.4v-.4h.4v.4h.4v-.3h1.1l.1 .3h.4v-.4h.4v.4h.4v-.4l-.1-.1h-1l-.2 .2h-1.1l-.2-.2h-.9l-.2 .2h-6.2l1.6-1.5h4.5v.8l.4 .3h.7l.4-.2h1l.3 .2h.8a.61 .61 0 0 1 .7-.3 .62 .62 0 0 0 .5-.8 .62 .62 0 0 0-.9-.3l-.4-.2-.6-.1-.3 .1-.1 .2h-1l-.4-.2-.6-.1-.4 .2-.1 .4h-4.5l.6-.6h9.3l.4-.2h.9l.1 .1v12l.2 .2h5.7l.1 .1v16h-.1l-6.6 .1-.2 .1v3.2l-.3 .3-.1 .3h-6.7a1.42 1.42 0 0 0-2.1 .2 1.42 1.42 0 0 0 .5 2.1v4.4l-.1 .9a.56 .56 0 0 0 .5 .5h.7l.3-.4-.1-5.4 .3-.2h6.7a.57 .57 0 0 0 .4 .6v24.2l-.1 .1h-13.5v-3.3l-.2-.4-.2-.1h-4.1l.1-.8h.4l.1 .2h.7v-.7h.4l.1 .7h.7l.1-.2h6.7a1.08 1.08 0 0 0 1.5 0l-.8-.8-.7 .8h-6.7v-.5h-2.1v.5h-.4v-1.4h.4v.5h.8v-.7h.4v.7h.9v-.2h6.2a.99 .99 0 0 0 .2 .8l.8-.7h.5l.8 .7 .1-.1 .1-.5a.99 .99 0 0 0-.2-.9l-.8 .8h-.5l-.8-.8-.1 .2-.1 .5h-6.2v-.4l-.2-.1h-1.7l-.2 .2h-.4v-.6h9.2l.7 .7 .8-.7a1.08 1.08 0 0 0-1.5 0h-9.2v-1.5l-.3-.3-2.6-.1v-1.7h1.2l.3 .4 .3 .2h.2v-.8h.4v.8l.5-.2 .3-.4v-.2h-2v.2h-1.2v-.7h1.2v.1h.8v-.7h.4v.7h.8l-.1-.2-.3-.4h1.5v.7l.2 .3a.64 .64 0 0 0 .6 .5 .64 .64 0 0 0 .6-.5l.2-.3v-.6h6.3l.1 .1 .3 .1 .1-.6h.3v.5l.3 .1 .2-.2v-.3l-1.3-.1v.4l-6.3-.1a.56 .56 0 0 0-.6-.5l-.7 .1-.3 .4h-1.5a1.04 1.04 0 0 0-1.6 .5h-1.2v-3.1h1v1.7l.2 .3 1.9 .1a.36 .36 0 0 0 .3-.5h.9l.3 .3 .3 .1h.7l.3-.4h6.3v.4h.5v-.5h.3v.5l.5-.1v-.4l-.2-.1h-1l-.1 .2h-6.3v-.8l-.3-.4-.8-.1-.3 .2-.2 .2h-.9l-.1-.7-.1-.2a.57 .57 0 0 0 .6-.4l.2-.2 .2-.3h1l.1 .1h.3l.1-.5h.4v.5h.3l.1-.1v-.4h-1.3v.4h-1v-.9l-.1-.2h1.1v.3h.5v-.4h.4v.4h5.3a1.4 1.4 0 0 0 .7 1.3v1.3a.56 .56 0 0 0 .5 .5h.6l.3-.2 .1-.3v-1.3l.2-.1a1.42 1.42 0 0 0-.2-2.3v-1.2a.56 .56 0 0 0-.5-.6h-.6l-.4 .3v.3v1.2l-.2 .1a1.42 1.42 0 0 0-.5 1h-4.9v-.4l-.1-.1h-1l-.2 .2h-1.1l-.3-.2h-1.1a.57 .57 0 0 0-.5 .6v.8l.7 .7h-1.6l-.2 .1-.1 .2h-1l-.1-.5-.3-.3h-4.6l.2-.1 .3-.3h.1l.1 .2 .2 .1h1.7h1.7l.2-.1 .1-.2h.2l.3 .3 .7 .1a.56 .56 0 0 0 .5-.6v-.8l-.3-.3h-.8l-.3 .2-.1 .2h-.2v-.8h.3l.1 .2h.3v-.5h.4l.1 .5h.3l.1-.2-.1-.3h-1.2v.3h-.3v-1h.3v.3h.4v-.5h.4v.5h.4l.1-.2h.2v.3l.4 .3 .4 .2 .4 .3h1.2l.4-.3h.9l.2 .3 .3 .1h.6l.3-.1 .1-.3 .1-.7a.56 .56 0 0 0-.6-.6h-.6l-.2 .2h-1.1l-.4-.3-1.1-.1-.4 .3a.57 .57 0 0 0-.6-.1 .57 .57 0 0 0-.3 .5h-.2v-.2l-.2-.1h-1l-.1 .2h-.3l-.2-.3h-.4l-.9-.9v-.5h.3l.3-.1a.57 .57 0 0 0 .8 0 .57 .57 0 0 0 0-.8 .57 .57 0 0 0-.8 0 .62 .62 0 0 0-.8-.1h-.3h-.3l-.2-.1 .3-.3h2.7v.6l.1 .3a.63 .63 0 0 0 .6 .7 .63 .63 0 0 0 .7-.6h1.1a.58 .58 0 0 0 .5 .6 .58 .58 0 0 0 .7-.4l.3-.1 .2-.3h.6l.2 .2h.3v-.6h.4v.6h.4l.1-.2h.7l.1 .2h.3l.1-.6h.3v.5l.4 .1 .1-.1v-.4l-1.3-.1v.4h-.7l-.1-.4h-1.2l-.1 .4h-.6v-.1a.58 .58 0 0 0-.5-.6 .58 .58 0 0 0-.7 .4l-.3 .2-.2 .3h-1.1l.2-.4-.1-.9h3.3l.1 .4h.4v-.5h.4v.5h.4l.1-.4h.7v.4h.5v-.5h.3v.5h.5v-.4l-.2-.2h-1l-.1 .2h-.7l-.2-.2h-1l-.2 .2h-3.3l-.2-.2-.7-.1a.56 .56 0 0 0-.6 .6h-2.7l.2-.2h1.2a.57 .57 0 0 0 .7 0 .57 .57 0 0 0 .1-.8h.6l.2 .2h.3v-.5h.4v.5h.3l.2-.1v-.4h-1.3l-.1 .3h-.6a.57 .57 0 0 0-.9 0l-1.4 .1-1.9 1.8-.1-.4-.2-.3-.1-.6h.9l1-1v-.4a.69 .69 0 0 0 1 0h.2l.4-.5 1.9 .1-.2 .1 .1 .4h.4v-.5l.2-.1 .2 .1v.5h.4l.1-.4-.2-.1 .3-.1 3.1 .1 .2-.2 .3 .1-.2 .1-.2 .2-.1 .8a.56 .56 0 0 0 .6 .5h.6l.3-.2h.6l.4 .2h.8l.3-.3v-.8a.56 .56 0 0 0-.5-.5h-.6l-.4 .2h-.6l-.2-.2h-.5l.2-.2v-.3h-.7v-.4l.1-.5h.3v.5l.3-.1-.1-.3-.1-.1h-.4l-.3-.1v-.6h2.5l.1 .1 .3 .1v-.6h.4v.5l.3 .1 .2-.2-.1-.4h-1.2v.4h-2.5l-1-1h.1a.57 .57 0 0 0 .8-.1h2.6v.4h.4v-.5h.4v.5l.5-.1v-.4l-.2-.1h-1l-.1 .2h-2.6a.57 .57 0 0 0 0-.8 .57 .57 0 0 0-.8 .1h-4.5l-.1-.3h3.4l1-.9h.2l.2 .4 .8 .8 2.3 .1 .4 .2h.6l.3-.1 .2-.2v-.8a.56 .56 0 0 0-.5-.5h-.6l-.4 .2h-1.8l-.6-.6a.57 .57 0 0 0-.9 .5h-.2l.4-.4v-.3h3.2l.1 .2h.3v-.5h.4l.1 .5h.3l.1-.2-.1-.3h-1.2v.3h-3.2v-1.1h3.2v.4h.4v-.5h.4v.5h.4l.1-.4-.2-.2-1 .1-.1 .1h-3.2v-2.3a.56 .56 0 0 0 .7-.4l.5-.5h1a.57 .57 0 0 0 .5 .6l.7 .6-.3 .3-.1 .8a.56 .56 0 0 0 .6 .6l.6-.1 .3-.1 .1-.3v-.7l-.1-.3-.2-.2-.1-.4-.8-.8-.1-.2h1.7v.1a.57 .57 0 0 0 .8 .5v.8l.4 .3h.8l.4-.3h.3l.1 .2h.3l.1-.5h.4v.5h.3l.2-.1-.1-.4h-1.3v.3h-.3l.1-.5h2.4v.1a.64 .64 0 0 0 .7 .5l.1 .1 .1 .6a.57 .57 0 0 0 .6 .4 .57 .57 0 0 0 .5-.5v-.5l.2-.2h.8l.2 .2h.3v-.5h.4v.5h.4l.1-.2h.2l.1 .2h.3v-.5h.4l.1 .5h.3l.1-.1-.1-.4h-1.2v.3h-.2l-.1-.3h-1.2l-.1 .3h-.8v-.7h3.8v.7a.57 .57 0 0 0 .6 .6l1.8-.2a.82 .82 0 0 0 1.1-.8 .82 .82 0 0 0-1.2-.7l-1.7-.1a.57 .57 0 0 0-.6 .5h-3.8v-.3h.8l.1 .3h.4v-.5h.4v.5h.4l.1-.3h.2v.3h.4v-.5h.4v.5h.4l.1-.3-.2-.2h-1l-.1 .2h-.2l-.2-.2h-1l-.2 .2h-.8l-.3-.3h-.7l-.3 .1-.2 .2a.57 .57 0 0 0-.7 .5h-2.4l-.1-.4h.3v.2h.5v-.4h.4v.4h.4l.1-.3-.1-.1h-1.2l-.1 .2h-.3l-.2-.4 .2-.2h.3l.1 .2h.3l.1-.5h.4v.4l.3 .1 .2-.1v-.4h-1.4v.3h-.3v-1h.3v.3h.5v-.4h.4v.4h.4l.1-.3-.2-.2h-1l-.2 .2h-.3l-.2-.3a.27 .27 0 0 1 .2-.2 .27 .27 0 0 1 .3 .1l.3 .2 .9-.1 .3-.4v-.8h1.3l.1 .5 .4 .2-.4 .6-.1 .8a.56 .56 0 0 0 .6 .5h.7l.3-.3v-1l-.3-.5-.4-.2h.6a.57 .57 0 0 0 .5 .6 .57 .57 0 0 0 .6-.4l.3 .1a.56 .56 0 0 0-.6 .6l.1 .8 .4 .3 4.1-.1a.57 .57 0 0 0 .5-.6v-.7l-.3-.4-1.3-.1-.3 .3-2.5-.1 .3-.1 .2-.3a.57 .57 0 0 0 .6-.8 .57 .57 0 0 0-1 0 .57 .57 0 0 0-.7-.4 .57 .57 0 0 0-.3 .7 .57 .57 0 0 0-.6 .6l-.6-.1a.57 .57 0 0 0-.1-.9 .57 .57 0 0 0-.8 .4h-1.3l-.3-.3h-.8l-.3 .1-.4 .3-.3-.4h-.8a.56 .56 0 0 0-.5 .5v.6l.2 .4a.33 .33 0 0 1-.4 .3 .75 .75 0 0 0-.4 .7l-.2 .4h-1.7a.57 .57 0 0 0-.6-.3 .57 .57 0 0 0-.5 .5h-1l.4-.6 .1-1.9a.56 .56 0 0 0 .5-.6l-.1-.8h13.1v.1a.57 .57 0 0 0 .9 .4 .57 .57 0 0 0 0-.9 .57 .57 0 0 0-.9 .4h-13.1l-.2-.3h-.7a.56 .56 0 0 0-.6 .6v1h-.3l.1-.2v-.4h-1.3v.4l.2 .2h-.2h-2.4v-1.3h2.4v.4h.5v-.5h.3v.5h.5v-.4l-.1-.2h-1l-.2 .2h-2.4v-2.2l-.2-.3h.5l.1 .2h.4l.1-.5h.3v.4l.4 .1 .1-.1 .1-.4h-1.4l-.1 .3h-.5l-1-1h1.5l.1 .3h.5v-.4h.3v.4h.7l.1 .7 .2 .2 .3 .1v.3l-.2 .3v.7a.56 .56 0 0 0 .5 .5h.6l.6-.2 .2 .1h.3v-.5h.4v.5h.3l.2-.1-.1-.4h-.8v-.9h.4v.5h.5l-.1-.5h-1.1l-.1 .1-.1 .3-.2-.1-.2-.3v-.3h5.1l.1 .3 .3 .2 .1 .8 .4 .2h.8l.3-.3 .6 .3h.9l.3-.4v-.7l-.1-.2h.5v.1a.57 .57 0 0 0 .9 .4 .57 .57 0 0 0 0-1 .57 .57 0 0 0-.9 .5h-.5l-.3-.2 .4-.3v-.4h2.1l.1 2.6 2.8 .1 .1-.3v-2.4a.59 .59 0 0 0 .9-.4l.2-.3 .3 .2a.59 .59 0 0 0 .5 .7 .57 .57 0 0 0 .5 .5 .57 .57 0 0 0 .6-.2v3.2l1.1 1.1 .6 .1 .6 .6 .3 .5a.56 .56 0 0 0 .5 .5h.7l.3-.1 .2-.3v-.6a.56 .56 0 0 0-.6-.5l-.8-.1-.7-.7 .3-.2h1.1v.6a.67 .67 0 0 0 .9 .4l-.2 .4v.6a.56 .56 0 0 0 .6 .5h.8l.2-.2 .1-.3v-.7l-.4-.3v-1.5l.4-.3v-.8l-.3-.4-.8-.1a.56 .56 0 0 0-.6 .6v.5l.2 .4a.67 .67 0 0 0-.9 .5v.1h-1.1l.4-.5h.8a.56 .56 0 0 0 .6-.6v-.5l-.2-.3-.3-.2h-.7a.64 .64 0 0 0-.6 .6l-.2 .4-.6 .7-.4-.4v-3.5l-.6-.6h1.6l.1 .3 .2 .2a.56 .56 0 0 0 .5 .6h.7l.3-.2 .2-.3v-.5a.56 .56 0 0 0-.6-.6h-.6a.57 .57 0 0 0-.8 .5h-3.3a.57 .57 0 0 0-.2-.7 .57 .57 0 0 0-.7 0l-.3-.3 .3-.2v-.3h5.5v.6a.67 .67 0 0 0 .9 .5l-.2 .4v.5a.56 .56 0 0 0 .6 .6h.8l.2-.3 .1-.3v-.6l-.4-.4v-1.5l.4-.3v-.8l-.3-.4h-.8a.56 .56 0 0 0-.6 .5v.6l.2 .4a.67 .67 0 0 0-.9 .4v.1h-5.5v-.5a.56 .56 0 0 0-.5-.5h-.8h5.5v.1a.59 .59 0 0 0 .8 .4h.7l.3-.1 .2-.3v-.6a.56 .56 0 0 0-.6-.5h-.7a.66 .66 0 0 0-.5 .6l-.2 .4h-5.5l-.4-.5h1.1l.2 .2h.3v-.5h.4v.4l.3 .1 .2-.1v-.4h-1.3l-.1 .3h-1.1l-.1-.3h-1.3v.3l.1 .2v.4l-.2 .1-.1 .3 .9 .1 .1 .8h.4l.1-.2 .5 .3-.2 .2-.1 .4v.5l.3 .5h-2.5h-.2l-.1 .3h-2.1l-.1-.6h3l.2 .1 .3 .1 .1-.5h.3v.4h.5l.1-.1-.1-.3h-1.3l-.1 .3h-3l-.3-.3 .4-.3v-.4h2.9l.1 .3h.5v-.4h.3v.4h.5l.1-.3-.2-.2h-1.1l-.2 .2h-2.9l-.1-.6h3l.2 .2h.3l.1-.4h-.5l-.1 .2h-3l-.3-.2h-.7l-.8 .4v-.2l-.4-.1-.1 1.3h.4l.1-.2 .6 .3-.1 .1a.29 .29 0 0 1-.3 .2 .29 .29 0 0 1-.3-.2l-.9-.1a.56 .56 0 0 0-.5 .6v.4l-.3 .3-.1 .3h-5.1v-1a.56 .56 0 0 0-.5-.6l-.8 .1-.3 .2-.1 .3h-.1l-.1-.3-.1-.2h-1.1l-.2 .2h-1.5l-.3-.1h-2.8l-.4-.5h.1a.57 .57 0 0 0 .8-.3 .57 .57 0 0 0-.5-.7v-.6h.2l.2 .2h.3v-.5h-.4l-.1 .3h-.2v-1h.2l.1 .3h.4l-.1-.5h-.2l-.2 .2h-.2v-1.3zM189.3 90.7l.7-.1 .2 .1v.8l-.1 .1-.6 .1-.2-.1zM189.3 89l.7-.1 .2 .1v.7l-.1 .2h-.6h-.2zM191.7 90.7l.7-.1 .2 .1v.8l-.1 .1-.6 .1-.2-.1zM191.7 89l.7-.1 .2 .1v.7l-.1 .2h-.6h-.2zM195.5 89.9h.9l.1 .2-.1 .6-.1 .1-.8-.1-.1-.2zM197.3 89.9h.9l.1 .2-.1 .6-.2 .1-.7-.1-.1-.2zM201.9 91.3h.9l.1 .2-.1 .6-.2 .1-.7-.1-.1-.2z"/>
<path d="M203.6 91.3h.9l.1 .2v.6l-.2 .1-.7-.1-.1-.2zM206.2 84.8h.9l.1 .2-.1 .6-.2 .1-.7-.1-.1-.2zM207.9 84.8h.9l.1 .2v.6l-.2 .1-.7-.1-.1-.2zM210.4 92.1l.7-.1 .1 .1 .1 .8-.1 .1-.6 .1-.2-.1zM210.4 90.4l.7-.1 .1 .1 .1 .7-.1 .2h-.6h-.2zM186.8 88.3v-.1h30l.1 .1v10.5l-.1 .1h-30v-.1v-1.1h15.2v.1a.57 .57 0 0 0 .6 .6 .57 .57 0 0 0 .5-.6l2.2-2.1v-2.6h4.9l.1 .2h.4l.1-.7h.1v.7h.4l.2-.2-.1-.5h-1.2v.5h-4.9v-1l.1-.1h4.8v.5h.6v-.6h.1v.6h.5l.1-.5-.2-.1h-1l-.1 .1h-4.8v-.1a.72 .72 0 0 0-.7-.9l-.9-.1a.56 .56 0 0 0-.6 .6l.1 .5 .1 .3 .3 .2h.7v2.8l-1.9 1.9-.4 .2-.1 .3h-15.2v-1h1.9v.1a.57 .57 0 0 0 .8 .5 .57 .57 0 0 0 0-1 .57 .57 0 0 0-.8 .4h-1.9v-5h2.3l.1 .2h.4l.1-.7h.1v.7h.5l.1-.2h1.1l.1 .2h.4l.1-.7h.1v.6l.4 .1 .2-.1v-.5l-1.3-.1v.5h-1.1v-.5h-1.3v.5h-2.3v-1.1h2.3v.5h.6v-.6h.1v.6h.6v-.5h1.1v.5h.6v-.6h.1v.6h.6v-.2h1.6a.57 .57 0 0 0 .5 .6l.4 .4v4.7a.57 .57 0 0 0-.5 .6 .57 .57 0 0 0 .5 .5 .57 .57 0 0 0 .6-.5l.3-.4v-4.2h1.9v1.1a1.6 1.6 0 0 0 .7 1 .57 .57 0 0 0 .6-.5 .57 .57 0 0 0-.5-.7v-.7l.1-.1a.57 .57 0 0 0 .2-.9 .57 .57 0 0 0-.9 .3l-.2 .5h-1.9l-.1-1.1-.5-.5 .3-.1v-.5h.1l.1 .6 .5-.1 .1-.1v-.4h-1.5a.57 .57 0 0 0-.8 .5h-1.6v-.3l-.2-.2-1 .1-.1 .1h-1.1l-.2-.2-1 .1-.1 .1h-2.3v-1.5h1.6l.2 .4 .8 .7h.7l.4-.2h.9l.4 .2h.7l.3-.1 .1-.3h2.4v.4h.6v-.5h.1v.5h.6l.1-.1h.2v.4a.56 .56 0 0 0 .5 .6h.7l.3-.2h1.1l1.4 1.4h.8l.2 .2h.7a.56 .56 0 0 0 .6-.6v-.6l-.3-.3-.8-.1-.7 .2-.5-.6h9.1v.6a.56 .56 0 0 0 .6 .6l.6-.1 .3-.2 .1-.9-.1-.4a.67 .67 0 0 0-.8-.6 .67 .67 0 0 0-.6 .7l-.1 .3h-9.1l-.7-.7-.3-.1h-1.5l-.3-.2h-.7a.56 .56 0 0 0-.5 .6h-.2v-.4l-.2-.1h-1.1l-.1 .2h-2.4v-.9l-.4-.3h-.7l-.4 .2h-.9l-.4-.2h-.9a.57 .57 0 0 0-.8 .5h-1.6zM70.5 103.7l.1-.1h14v1.4l.2 1.3 .5 1.1 .7 1 .9 .8 1.2 .8 1 .3 1.2 .2 .1 .1v14.1l-.1 .1h-19.7l-.1-.1v-.6h4l.2 .1 .8 .1v-.9h.1l.1 .9 .8-.1 .1-.1h1.1l.1 .1 .8 .1 .1-.9h.1l.1 .9 .8-.1 .1-.1v-.7h-2.1v.7h-1.1v-.7h-2.1v.7h-4v-1.5h4v.7h1v-.8h.1v.8h1v-.7h1.1v.7h1v-.8h.1v.8h1v-.7l-.2-.2h-1.8l-.1 .2h-1.1l-.2-.2h-1.7l-.2 .2h-4zM112.7 114.4h.9l.1 .2-.1 .6-.1 .1-.8-.1-.1-.2zM96.2 103.6h18v.5l.3 .4v.6l-.3 .3v.6a.56 .56 0 0 0 .6 .6h.6l-.7 .1-.3 .1-.2 .3v.6a.56 .56 0 0 0 .6 .5h.8l.4-.4 .2 .3-.6 .5-.8-.1-.3 .1a.63 .63 0 0 0-.9 0 .63 .63 0 0 0-.1 .8l-.1 .3 .2 .4-.2 .3 .1 .4-.1 .4 .1 .3a.57 .57 0 0 0 .1 .6 .57 .57 0 0 0 .6 .2l.1 .5 .4 .4a.57 .57 0 0 0-.2 .8l-.2 .1a.28 .28 0 0 1-.3 .2 .28 .28 0 0 1-.2-.2l-.9-.1a.56 .56 0 0 0-.6 .6l.1 .7 .3 .3h.9l.5-.3 .4 .3h.8l.4-.3 .1-.3-.1-.6-.3-.4a.57 .57 0 0 0-.2-.8 .63 .63 0 0 0 .7-.9h.1v.3a.61 .61 0 0 0 .8 .6 .64 .64 0 0 0-.2 .8 .55 .55 0 0 0-.5 .6l.1 .7 .3 .3h.9l.4-.3 .5 .3h.7l.3-.1 .2-.2 .1-.7-.1-.4h8v.7l.3 .4a.58 .58 0 0 0 .5 .8 .58 .58 0 0 0 .5-.8l.3-.4v-.5h1.1l.1 .1h.2l.1-.4h.3v.4h.2l.1-.1 .1-.2-1-.1-.1 .3h-1.1a.57 .57 0 0 0-.6-.7l-.8 .1-.2 .4h-8l-.4-.2h-.7l-.6 .3-.3-.2a.56 .56 0 0 0-.2-1l.3-.3h2.6a.58 .58 0 0 0 .7-.8h1.1v.1a.6 .6 0 0 0 .8 .4h4.7v.6a.56 .56 0 0 0 .5 .5h.6l.3-.1h1.3l.1 .2h.3v-.3h.3v.3h.3v-.3l-.1-.1h-.7l-.2 .2h-1.3l.2-.3 .3-.1 .4-.3h.3l.1 .2 .2 .1h.8l.2-.3 .4 .2v1.4l.2 .3h.8l.2-.2h11.9v.7l.1 .3 .3 .1h.8a.57 .57 0 0 0 .7 0 .57 .57 0 0 0 .1-.8l-.4-.4a.56 .56 0 0 0-.6-.5l-.8 .1-.2 .5h-11.9v-.9h5.2l.2 .2h.3l.1-.5h.3l.1 .5h.4l.1-.2-.1-.3h-1.3l-.1 .3h-5.2v-.3v-.6h5.2l.1 .3h.5v-.5h.3v.5l.8-.1v.5a.56 .56 0 0 0 .5 .5h.7l.3-.2h.8l.3-.1h2.5l.1 .1 .3 .1 .1-.6h.4v.5l.3 .1 .1-.2v-.4h-1.2l-.1 .4h-2.5l.5-.6 .1-.5h1.9l.1 .3h.4v-.4h.4v.4h.4v-.3l-.1-.2h-1l-.2 .2h-1.9v-2.2l-.2-.2h-.8h-.1l-.2 .2v.7l.1 .2v1.4h-.5l-.3-.2h-.8l-.3 .2-.1 .3h-.2v-.3l-.2-.1h-1.1l-.2 .2h-5.2v-1.1l.2-.2h1l.1 .2h.3l.1-.6h.4v.6h.3l.1-.2h3.5l.2 .2h.3v-.6h.4v.6h.3l.2-.2-.1-.4h-1.2l-.1 .4h-3.5v-.4h-1.2l-.1 .4h-1v-1.1h1l.1 .4h.4v-.5h.4v.5h.4v-.4h3.5l.1 .4h.4v-.5h.4v.5h.4l.1-.4-.2-.2h-1l-.2 .2h-3.5l-.1-.2h-1l-.2 .2h-1l-.3-.3h-.7a.56 .56 0 0 0-.5 .6v.6l.1 .6-.4 .2-.1-.2-.1-.2 .3-.4v-.6a.56 .56 0 0 0-.6-.6h-.7l-.3 .4v.8l.2 .3 .2 .2-.2 .3h-.6l-.4 .4-.4-.4-.7-.1a.56 .56 0 0 0-.5 .6h-3.9l.3-.3h.2l.2 .2h.3v-.5h.4l.1 .5h.3l.1-.1v-.4h-1.3l-.1 .3h-.2v-.9h.2l.1 .3h.4v-.5h.4v.5h.5v-.2h2.1l.1 .2h.3l.1-.6h.4v.5l.2 .1 .2-.2v-.3l-1.2-.1-.1 .4h-2.1l-.1-.3h-1.1l-.2 .2h-.2l-.4-.3h-.7a.56 .56 0 0 0-.6 .5l-.2 .5h-1.1a.57 .57 0 0 0-.6-.4 .57 .57 0 0 0-.5 .4h-2.2l-.3-.4 .3-.4h2.1l.5-.4a.56 .56 0 0 0 .6-.5h6.8l.1 .4h.4v-.5h.4v.5l.4-.1v-.3l-.2-.2h-.9l-.2 .2h-6.8a.56 .56 0 0 0-.3-.6 .57 .57 0 0 0 .2-.9h6.8v.6a.56 .56 0 0 0 .5 .5h.7l.3-.2 .3-.1 .6-.6v.6l.4 .3h.7l.4-.3h.4l.1 .2h.3l.1-.5h.4v.5h.3l.1-.2v-.3h-1.3v.3h-.4v-1h.4v.3h.5v-.5h.4v.5h.4l.1-.3 .1 .3 .5 .6 .7 .4h.7l.3-.1 .2-.3v-.7h3.2v.6a.56 .56 0 0 0 .6 .5h.5l.3-.1 .2-.3v-.5h1.3v.6l.2 .2 1 .1 .2-.3-.1-.8a.62 .62 0 0 0-.7-.8 .62 .62 0 0 0-.5 .8l-.1 .2h-1.3v-.4l-.2-.2a.6 .6 0 0 0-.7-.6 .6 .6 0 0 0-.5 .6l-.2 .4h-3.2l-.1-.3-.3-.2h-.7l-.3 .1a.61 .61 0 0 0-.6-.4 .61 .61 0 0 0-.5 .6l-.3-.2h-1l-.1 .2h-.4l-.1-.2a.62 .62 0 0 0-.6-.5 .62 .62 0 0 0-.6 .5 .57 .57 0 0 0-.9-.2l-.3 .2-.3-.1h-.6a.56 .56 0 0 0-.5 .5h-6.8l-.2-.1 .5-.3a.56 .56 0 0 0 .5-.6h.1l.2 .2h.3v-.5h.4v.5h.3l.2-.1v-.4h-1.3l-.1 .3h-.1a.57 .57 0 0 0-.6-.6 .57 .57 0 0 0-.6 .6l-.2 .3h-2.1v-.3h.2l.1 .2h.3l.1-.5h.4v.5h.3l.1-.1v-.4h-1.2l-.1 .3h-.2v-.3l-.3-.2-.1-.3-.1-.2h.7l.1 .3h.4v-.5h.4v.5h.4v-.3h2.1l.1 .3h.4v-.5h.4v.5h.4l.1-.4-.2-.1h-1l-.2 .2h-2.1l-.1-.2h-1l-.2 .2h-.7l-.3-.1-.4-.1h.3a.56 .56 0 0 0 .6-.6l.5 .1 .3 .3h.6a.56 .56 0 0 0 .6-.6v-.4h1.3a1.24 1.24 0 0 0 .7 .8l.4 .2 .7-.1 .3-.4v-.6a.56 .56 0 0 0-.6-.6h-.5l-.3 .1a.57 .57 0 0 0-.7 .6h-1.3v-.1a.56 .56 0 0 0-.6-.6h-.6l-.3 .2-.1-.4-.1-.2 .5 .2h11.7v.5a.56 .56 0 0 0 .6 .6l.8-.1 .4-.3 .3 .3 .8 .1a.56 .56 0 0 0 .6-.6v-.6l-.3-.3-.9-.1-.4 .1a.19 .19 0 0 1-.1 .2 .19 .19 0 0 1-.2-.2l-.3-.1h-.8l-.4 .2-.1 .3h-11l.3-.3h.3l.1 .2h.4v-.5h.4v.5h.4l.1-.1v-.4h-1.4v.3h-.3l.1-.6h21.9l2.6 2.5v2.1a.57 .57 0 0 0 .1 .9 .57 .57 0 0 0 .8-.3l.1 .6 .8 .8v.3a.6 .6 0 0 0-.1 .7 .6 .6 0 0 0 .7 .2l.2 .3h.6v1.6l.5 .5 .3 .1h1.2l.5-.3a.59 .59 0 0 0 1 .4l.2 .1a.57 .57 0 0 0-.1 .8 .57 .57 0 0 0 .7 .2v.3l-2.1 2.2-.1 1.2-.4-.6a.57 .57 0 0 0 .2-.8 .57 .57 0 0 0-.9 0 .57 .57 0 0 0 .2 .8 .59 .59 0 0 0-.4 .6 .59 .59 0 0 0 .4 .5 .57 .57 0 0 0 .9 .4v1.1l-1.1 1.1v.9l-.3 .1 .1 1.4 .3 .1h.5l.4-.2v-1.3l-.3-.1v-.5l.2-.1a.57 .57 0 0 0 .7 .5l-.2 .2h-.1v1.3l.4 .2h.8l-.2 .3v.8l-.9-.1a.67 .67 0 0 0-.6-.2 .67 .67 0 0 0-.6 .4 .62 .62 0 0 0 1 .6h1.2l.1 .5h1.2v-.5h.2l-.1 .3v.7l.4 .6h-9.3l-1-1-.1-.2h2.8v.5a.56 .56 0 0 0 .5 .6h.7l.3-.3h4.3l.1 .2h.3l.1-.6h.4v.6h.3l.2-.2-.1-.4h-1.2l-.1 .4h-4.3l.5-.5a.6 .6 0 0 0-.1-.8 .6 .6 0 0 0-.8-.1h-.6a.56 .56 0 0 0-.5 .6h-2.8v-.1a.69 .69 0 0 0-.8-.3l-.3-.2h-.6l-.3 .2-.2 .4v.6l.2 .3a.63 .63 0 0 0 .6 .7 .63 .63 0 0 0 .6-.7l.2-.2h.1l1.3 1.2h1.5l-.5 .5v.9h-1v-.6a.83 .83 0 0 0-1.1-.7l-.4 .4-.1 .8a.56 .56 0 0 0 .7 .6l-.1 .1a.56 .56 0 0 0-.6 .5v.7l.3 .3a.6 .6 0 0 0 .5 .9 .6 .6 0 0 0 .6-.9l.2-.4v-.7l-.1-.2 1.2-.1-.1 .4 .1 .9 .3 .2h.6a.56 .56 0 0 0 .5-.5v-.7h1.1l.1 1 .4 .2h.6a.56 .56 0 0 0 .5-.5v-.4h4.9l.8-.7 .1-.4 .3 .4a.62 .62 0 0 0 .7 .6 .57 .57 0 0 0 .8 .4 .57 .57 0 0 0 .2-.8h1.4l.1 .2h.3l.1-.5h.4v.5h.3l.1-.1 .1-.4h-1.3l-.1 .3h-1.4l-.1-.2a.57 .57 0 0 0-.1-.8h1.6l.1 .3h.4v-.5h.4v.5l.5-.1-.1-.3-.1-.1h-1l-.2 .2h-1.6a.56 .56 0 0 0-.7 0 .57 .57 0 0 0-1 0 .57 .57 0 0 0-.4-.5 .57 .57 0 0 0-.6 .2 .63 .63 0 0 0-1-.1h-2.5a.57 .57 0 0 0-.6 0 .57 .57 0 0 0-.2 .6h-.6v-.9l-.5-.5h11l.3-.1 .8-.8 .1 .2v.8l-.3 .4v.4h-.4l-.2 .2v1.9h-.1l-.4-.4h-.8a.61 .61 0 0 0-.4 .7h-.2h-4.5l-.3 .4v4.3h-.1l-.1-.6h-1.7v.6h-1.5l-.3 .2-.1 7h-2.8v-.7h.1l.2 .2h.7v-.7h.4l.1 .7h.6l.2-.2-.1-.5h-2l-.1 .5h-.1v-1.4h.1l.1 .5h.8v-.7h.4v.7h.8l.1-.5-.2-.2h-1.8l-.2 .2h-.1v-2.1l-.3-.3-4.5-.1v-2.3h.2v1l.3 .3h1.2l.2-.3 .2 .1v-.4h.4v.4h.2l.3-.3 .2 .3h.2v-.4h-.4v.1l-.1-.1h-.8v-.4h.8l-.2-.4 .3-.2 .2 .2-.2 .4h.8v.8l.4-.2a.82 .82 0 0 0 1.3 .1 .82 .82 0 0 0 1.2 .1 .82 .82 0 0 0 0-1.3 1.01 1.01 0 0 0-.2-1.4l-.1-.8h.4l.1 .5h2.6v.7h.7v-.9h.4v.9l.7-.1v-.7l-.2-.1h-1.5l-.1 .2h-2.3l.1-.2v-.3h-1.2l-.4-.4v-.2h.2l.1 .2h.4v-.4h.4v.4h.5v-.3l-.1-.1h-1.1l-.2 .2h-.2l-.4-.3-.7-.1-.3 .1-.3 .4-.3-.4-.8-.1a.56 .56 0 0 0-.5 .6v.7l.3 .3h.9l.3-.1 .2-.3 .1 .3 .3 .1h.8l.2-.1 .2 .2-.2 .4a.82 .82 0 0 0-1.3 0 .82 .82 0 0 0-1.2 0 .82 .82 0 0 0-1.3 0 .82 .82 0 0 0-1.1-.1 .82 .82 0 0 0-.2 1.1l-.2 .3h-.2v-2.8h.6v.5a.56 .56 0 0 0 .6 .5h.6l.4-.2 .1-.9-.3-.4a.59 .59 0 0 0-.6-.5 .59 .59 0 0 0-.5 .5l-.3 .5h-.6v-1.9l-.4-.3h-9.8l-.4 .3v2.6h-.3v2.1h.3v2.3h-3.1l-.3 .2-.1 .3v4l.3 .4h5.5l.3-.3v-1.2h.4l.4 .1 .4-.1-.4-.4-.4 .4h-.4v-.6l.2 .3 .3-.3h.6l.3 .3 .2-.4-.2-.3-.3 .4h-.6l-.3-.4-.2 .4v-.7h.4l.4 .4 .4-.4-.4-.1-.4 .1h-.4v-1.7h1.6v4.1l.1 .3 .4 .2h6.5v3.5h-55.6v-1.7h8.5l.1 .9a.75 .75 0 0 0 .8 .8 .72 .72 0 0 0 .6-.8h1.1l.4 .2h.7l.3-.3h5.6l.1 .2h.3v-.6h.4v.5l.3 .1 .2-.1v-.4l-1.3-.1v.4h-5.6v-.9l-.3-.4-.7-.1-.4 .2h-1.1l-.3-.2h-.6a.56 .56 0 0 0-.6 .6h-8.5v-1.7h1.2l.2 .2h.8l.1-.7h.4v.7h.9l.1-.3h4.8l.1 .8 .4 .3h.7l.4-.3h1l.1 .2h.3v-.5h.4l.1 .5h.3l.1-.3h4.3v.5a.64 .64 0 0 0 .5 .6 .64 .64 0 0 0 .7-.3h.2v.4h.4v-.5h.4v.5h23.3l.1 .1h.7v-.7h.4l.1 .7h.6l.2-.1h9.2l.1 .1h.7v-.7h.4l.1 .7h.6l.2-.1v-.6h-2.1v.6h-9.2l-.1-.6h-2v.6h-22.9l.1-.4-.2-.2h-1l-.1 .2h-.2l.1-.6 .4 .2 .6 .1a.58 .58 0 0 0 .5-.8h22.7v.6h.8v-.7h.4v.7h.8l.1-.6h9.2v.6h.8v-.7h.4v.7l.9-.1v-.5l-.2-.2h-1.8l-.1 .2h-9.2l-.2-.2h-1.8l-.1 .2h-22.7v-.5l-.2-.3a.82 .82 0 0 0 0-1.2 .82 .82 0 0 0-1.2 0 .82 .82 0 0 0 0 1.2l-.8 .2-.5 .5-.1 .4h-4.3v-.2h-1.3v.3h-1v-.8l-.1-.4a.64 .64 0 0 0-.7-.7 .64 .64 0 0 0-.6 .7l-.2 .4h-4.8v-.4h-2.4l-.1 .5h-1.2v-1.4h1.2l.1 .6h1v-.7h.4v.7h1v-.6l-.2-.1h-2.1l-.2 .1h-1.2v-2h4.6a.82 .82 0 0 0 .6-.7v-4.2l-.2-.4 .2-.4v-2.6h5.3v5l.2 .4-.2 .4v5.4a.82 .82 0 0 0 .7 .6h4.5a.82 .82 0 0 0 .5-.7v-2.8h6.4a.83 .83 0 0 0 .6-1h2.1v4l.3 .4h4.2l.3-.3v-.6l.1 .1h.4v-.5h.4v.5h.4l.1-.1-.1-.4h-.8v-.8h.4v.5h.4v-.5h-1.2l-.1 .1v-.3h1.1l.3-.2h1.9v2.2a.57 .57 0 0 0 .6 .4 .57 .57 0 0 0 .5-.5v-1.8l.4-.4a.57 .57 0 0 0 0-.8 .57 .57 0 0 0-.8 0l-.6 .6-.1 .3h-1.9l.1-.2v-1.8l-.3-.3h-.6l-.1-.4h-1.2v.4h-.2l-.1-.4h-1.2l-.1 .4h-2.1l-.3 .2-.1 .2h-2.1v-1.5h4.6l.1 .3h.4v-.4h.4v.4h.4l.1-.3h.2v.3h.4v-.4h.4v.4h.4l.1-.3-.2-.2h-1l-.1 .2h-.2l-.2-.2h-1l-.2 .2h-4.6v-2.5a.79 .79 0 0 0-.7-.7h-6.3v-2.1h9.1v3.8l.1 .2 .2 .2h4.1l.4-.3v-.4l.1 .1 .4-.1v-.4h.4v.4h.4l.1-.3h1.6l.1 .6 .3 .3v.8l-.4 .4 .1 .9 .5 .3h.7l.4-.3h.2l.2 .1h.3v-.4h.4v.4h.4l.1-.1v-.3h-1.3l-.1 .3h-.2v-1h.2l.1 .3h.4v-.4h.4v.4h.8l.1 1 .1 .3 .2 .1v1.2l.2 .4 .3 .2a.57 .57 0 0 0-.4 .6 .57 .57 0 0 0 .5 .5h.9l.3-.2 .7-.7v-.8a.57 .57 0 0 0-.6-.5 .57 .57 0 0 0-.5 .6v.3l-.2 .2h-.3a.57 .57 0 0 0 .2-1v-.8l.3-.3h.4l.1 .2h.5v-.7h.4v.7h.4l.2-.1-.1-.6h-1.4l-.1 .5h-.4v-1.4h.4l.1 .5h.5v-.6h.4v.6h.5l.1-.5-.2-.2h-1.2l-.2 .2h-.4l-.4-.3h-.8a.57 .57 0 0 0-.6 .6h-.3v-.3l-.1-.2h-1.1l-.2 .2h-.2l-.3-.3v-.8l.3-.4-.1-.8h.3l-.1 .7 .1 .4 .3 .2h.7l.3-.1 .2-.2h.6l.1 .1 .3 .1 .1-.5h.4v.5l.4-.1 .1-.1v-.3h-1.4v.3h-.6v-1h.6v.3h.5v-.4h.4v.4h.5v-.4l-.2-.1h-1l-.2 .2h-.6l-1.1-1-1-.1a.43 .43 0 0 1-.6 0 .68 .68 0 0 0-.6 1l-.1 .4-2.5-.1v-.8h.4v.4h.4l.1-.4-.2-.1h-1.1l-.1 .1v-.2l1.2-.1 .3-.3v-.8h5.3v.4a.56 .56 0 0 0 .6 .6h.7l.3-.2 .1-.2 .1-.6v.7l.3 .3v.7l-.3 .3v.7a.56 .56 0 0 0 .5 .6l.8-.1 .3-.2 .1-.3h2.6l.1 .2h.6v-.9h-.7v.7h-2.6v-.6l-.4-.6v-.5h3v.7h.7l-.1-.9h-.5l-.1 .2h-3l.3-.3 .1-.7a.56 .56 0 0 0-.6-.6l-.8 .1-.2 .2-.1 .3-.4-.5a.58 .58 0 0 0-.5-.6 .58 .58 0 0 0-.6 .6l-.3 .5h-5.3v-1.1l-.3-.3h-.6l-.1-.3h-1.2v.3h-.2l-.1-.3h-1.2l-.1 .3h-2.2l-.2 .2-.1 .3h-9.1v-.5h9.3l.1-.2v-.9h2.2l.1 .4h.4v-.5h.4v.5h.4l.1-.4h.2v.4h.4v-.5h.4v.5h.4l.1-.4-.2-.2h-1l-.1 .2h-.2l-.2-.2h-1l-.2 .2h-2.2v-2.4h2.3l.3 .4 .3 .2h.2v-.8h.4v.8l.5-.2 .3-.4v-.2h-2v.2h-2.3v-.7h2.3v.2h.8v-.8h.4v.8h.8l-.1-.3-.3-.4h.8v1.7v.2l.3 .1h1.7l.2-.1 .1-1.9-.2-.3h-1.8l-.3 .1v.2h-.8a1.03 1.03 0 0 0-1.6 .5h-2.3v-.9h10.7l.2 .2h.3v-.6h.4v.5l.3 .1 .2-.1v-.4l-1.3-.1-.1 .4h-10.7v-1.2h.8l.2 .2h.3v-.5h.4v.5h.3l.1-.1 .1 .1a1.17 1.17 0 0 0 1.8 .6 1.17 1.17 0 0 0-.1-1.9 1.17 1.17 0 0 0-1.8 .8h-1.2l-.1 .3h-.8v-1h.8l.1 .3h.4v-.5h.4v.5h.4l.1-.4-.2-.1h-1l-.2 .2h-.8v-.3l-.1-.1h-20.2l-.1-.1v-.5h4.1l.1 .2h.7v-.7h.4l.1 .7h.7l.1-.2h1l.2 .2h.7v-.7h.4l.1 .7h.6l.2-.2h2.9l.2 .2h.7v-.7h.4v.6l.7 .1 .2-.2-.1-.5h6.7l.1 .8 .3 .3h.7l.4-.3h.4l.6 .2a2.63 2.63 0 0 1 1.4 .5h.5a1.17 1.17 0 0 0-.1 1.7 1.17 1.17 0 0 0 1.7 0 1.17 1.17 0 0 0-.1-1.7h1.5l1.1 1.1 1.5 .1 .1 .3h1.2l.1-.3h1l-.1 .7a.57 .57 0 0 0 0 .9 .57 .57 0 0 0 .8-.3 .6 .6 0 0 0 .8-.6v-.7h1v.8l.2 .4a.61 .61 0 0 0 .6 .5 .61 .61 0 0 0 .6-.6l.1-.3v-.8h2.3v.5l-.4 .1-.4 .5v2l-.3 .4v1a.57 .57 0 0 0 .5 .5h.8l.4-.3v-1.2l-.3-.4v-1l.9 .9-.3 .5v1a.57 .57 0 0 0 .6 .5h.7l.4-.3 .1-1.2-.3-.4-.1-.6 .5 .4 1.4 .1 .5-.2 .1-.8 .1 .5a.76 .76 0 0 0 .4 .6l.1 .3 .6 .5a.59 .59 0 0 0 .8 .1 .59 .59 0 0 0 .1-.8 .59 .59 0 0 0-.8-.2l.4-.3 .1-.7a.56 .56 0 0 0-.6-.5h-.8l-.4 .5a.56 .56 0 0 0-.6-.5h-.6l-.4 .1-.1-.1v-.4l.1-.1h1l.1 .2h.3v-.6h.4v.5l.3 .1 .2-.1v-.4l-1.3-.1v.4h-1v-1h1v.3l1.3-.1 .5 .6h.3a.61 .61 0 0 0 .4 .8 .61 .61 0 0 0 .8-.3l.4-.3v-.8a.56 .56 0 0 0-.5-.6l-.7 .1-.4 .3-.7-.7h.8l.2 .2h.3h.7l.3-.3h1.3l.2 .2h.3v-.5h.4l.1 .5h.3l.1-.2h3.6l.1 .2h.3l.1-.5h.4v.5h.3l.1-.1v-.4h-1.2l-.1 .3h-3.6l-.1-.3h-1.2l-.1 .3h-1.3v-1h1.3l.1 .3h.4v-.5h.4v.5h.4l.1-.3h3.6l.1 .3h.4v-.5h.4v.5h.4v-.4l-.1-.1h-1l-.2 .2h-3.6l-.2-.2h-1l-.2 .2h-1.3l-.2-.2-.3-.1h-.6l-.3 .1v-.5l.2-.1 .3-.6v-.9h1.6l.4 .4v.5a.57 .57 0 0 0 0 .8 .57 .57 0 0 0 .8-.1h4.4l.1 .2h.3l.1-.5h.4v.5h1.5l.1 .1h.2v-.4h-.3v.3h-1.1v-.5h-1.2l-.1 .3h-4.4a.57 .57 0 0 0 0-.8v-.7l-.8-.8-2-.1v-.9l-.3-.4 .3-.5h.4l.2 .2h.3l.1-.5h.3l.1 .5h.4l.1-.2-.1-.3h-1.3l-.1 .3h-.4v-.9h.4l.1 .3h.5v-.5h.3v.5l.8-.1v.7l.4 .3h.8l.7-.3h3.1v.6a.55 .55 0 0 0 .5 .5 .55 .55 0 0 0-.5 .6v.7l.3 .6-.2 .2 .1 .3h1.2v-.1h1.1v.2l.3 .1-.1-.5-.2 .2h-1.1v-.3l-.2-.1 .4-.7-.1-.8-.2-.3-.2-.1 .2-.1a.58 .58 0 0 0 .7-.2 .58 .58 0 0 0 0-.7l-.8-.6h-.7a.56 .56 0 0 0-.5 .5h-3.1h.1a.57 .57 0 0 0-.1-.9h3.2l.1 .1 .3 .1 .1-.6h.4v.5l.2 .1 .2-.2v-.3l-1.2-.1-.1 .4h-3.2l-.7-.3h-.7l-.4 .1-.1 .4h-.2v-.3l-.2-.1h-1.1l-.2 .2h-.4l-.1-.2a.29 .29 0 0 1-.2-.2 .29 .29 0 0 1 .2-.3l.1-.7h.4l.2 .2h.3l.1-.4h-.5l-.1 .2h-.4a.62 .62 0 0 0-.5-.8l-.8 .1-.3 .4-.2 .1-.4 .4-.1 1.6-.4-.2h-.4a.56 .56 0 0 0 .7-.5v-.5l-.4-.3h-1.4l-.4 .3h-.7l-.9-.8h-3l-.8-.7h10.4l.1 .3h.5v-.5h.3l.1 1.3h.4l.1-.4 .6 .5h4.7l.1 .4h.4v-.5h.4v.5l.4-.1v-.4l-.2-.1h-.9l-.2 .2h-3.8l.3-.3v-.7a.56 .56 0 0 0-.5-.5h-.8l-.5 .4-.1-.2-.1-.1h-1.1l-.2 .2h-10.4l-.4-.2h-10.6l-.3 .1-.8 .8-.1 .5a1.23 1.23 0 0 0-1.5-.2 1.23 1.23 0 0 0-.6 1.4l-.5 .8v2.2l.6 .7 .3 .1-.4 .6-.3-.2h-.6l-.4 .3-.1 .3h-8.7l-.1 .5h-2.9l-.1-.5h-2l-.1 .5h-1v-.5h-2.1v.5h-4.1v-1.4h4.1v.5h.8v-.7h.4v.7h.9v-.5h1l.1 .5h.8v-.7h.4v.7h.8l.1-.5h2.9l.1 .5h.8v-.7h.4v.7l.9-.1v-.5l-.2-.1h-1.8l-.2 .2h-2.9l-.2-.2h-1.8l-.2 .2h-1l-.2-.2h-1.8l-.1 .2h-4.1v-12.3l.1-.1 1.6-.4 1.4-.8h17.9a.57 .57 0 0 0 .7 .5 .57 .57 0 0 0 .2-.9 .57 .57 0 0 0-.9 .2v.2h-17.9l1.1-1.2 .7-1.4 .4-1.6-.1-1.4zM113.8 118.5l1.2-.3-.3 1.1-.7 .1-.5 .4-.1-.1 .3-.5zM114.5 114.4h.9v.2v.6l-.2 .1-.7-.1-.1-.2zM114.6 103.3h.9l.1 .2-.1 .6-.1 .1h-.8v-.2z"/>
<path d="M114.6 105.4h.9l.1 .1-.1 .7-.1 .1-.8-.1v-.2zM114.6 112h.9l.1 .2-.1 .6-.1 .1-.8-.1v-.2zM114.6 110.5l.9-.1 .1 .2-.1 .7h-.1h-.8v-.2zM114.6 108.9h.9l.1 .2-.1 .6-.1 .1h-.8v-.2zM114.6 107h.9l.1 .2-.1 .6-.1 .1h-.8v-.2zM114.7 120.2l.7-.1 .5-.4 .1 .1-.4 .5-.1 .7-1.1 .3zM115.9 103.6h1.1v.8h.2l-.2 .6h-.7l-.3 .3-.1-.3-.3-.1v-.4l.3-.3h.2l.2 .2h.3v-.5h-.4l-.1 .3h-.2zM116.4 103.3h.9l.1 .2-.1 .6-.2 .1h-.7l-.1-.2zM116.4 105.4h.9l.1 .1-.1 .7-.2 .1-.7-.1-.1-.2zM116.4 112h.9l.1 .2-.1 .6-.2 .1-.7-.1-.1-.2zM116.4 110.5l.9-.1 .1 .2-.1 .7h-.2h-.7l-.1-.2zM116.4 108.9h.9l.1 .2-.1 .6-.2 .1h-.7l-.1-.2z"/>
<path d="M116.4 107h.9l.1 .2-.1 .6-.2 .1h-.7l-.1-.2zM116.5 114.4h.9l.1 .2v.6l-.2 .1-.8-.1v-.2zM116.8 118.5l1-.6 .6 .4 .7 .1v.1l-.8 .2-.5 .4zM118 100.6l.9-.1 .1 .2v.6l-.2 .1h-.7l-.1-.2zM118.3 114.4h.9l.1 .2-.1 .6-.2 .1-.7-.1-.1-.2zM118.3 103.3h.9l.1 .2-.1 .6-.2 .1h-.7l-.1-.2zM118.5 106.8h.6l.2 .1v.7v.2h-.7l-.1-.1zM118.5 105.1l.6-.1 .2 .1v.7v.2l-.7 .1-.1-.1zM119.8 100.6l.9-.1 .1 .2-.1 .6-.2 .1h-.7l-.1-.2zM120.1 103.3h.8l.1 .2v.6l-.2 .1h-.7l-.1-.2zM121.9 106.8h.6l.2 .1 .1 .7-.1 .2h-.6l-.2-.1zM121.9 105.1l.6-.1 .2 .1 .1 .7-.1 .2-.6 .1-.2-.1z"/>
<path d="M122.6 111.3h.9l.1 .2-.1 .6-.1 .1h-.8v-.2zM124.1 117.2l.6-.1 .2 .1v.7l-.1 .2h-.6l-.2-.1zM124.1 118.9l.6-.1 .2 .1v.7l-.1 .2-.6 .1-.2-.1zM124.4 111.3h.9l.1 .2-.1 .6-.2 .1h-.7l-.1-.2zM126.3 118.1h1.5l.1 .1v.4l-.2 .1h-1.3l-.1-.2zM126.3 119.4l1.5-.1 .1 .1v.4l-.2 .1h-1.3l-.1-.1zM125.2 117h2.1l1 1h3.1l.8 .7h1l.3 .2 .2 .1h-.2l-.3 .2h-4l-.7-.6h-2.5l-.4-.4-.4-.1 1.7 .1v-.3h.4v.3h.7l.1-.2-.2-.1h-1.6l-.2 .2h-.9zM127.9 112.3h.6h.2v.8v.2h-.7l-.2-.1zM127.9 114.1l.6-.1 .2 .1v.7v.2l-.7 .1-.2-.1zM127.9 110.4l.6-.1 .2 .1v.7v.2l-.7 .1-.2-.1zM127.9 108.6h.6l.2 .1v.7v.2h-.7l-.2-.1zM130.3 110.4l.6-.1 .2 .1 .1 .7-.1 .2-.7 .1-.1-.1z"/>
<path d="M130.3 108.6h.6l.2 .1 .1 .7-.1 .2h-.7l-.1-.1zM130.4 112h.7v.8h-.7zM130.4 113.5h.7v.9h-.7zM130.6 104.4l.9-.1 .1 .2-.1 .7h-.1h-.8v-.2zM132.1 108.6h.6l.2 .1v.7l-.1 .2h-.6l-.2-.1zM132.1 110.4l.6-.1 .2 .1v.7l-.1 .2-.6 .1-.2-.1zM132.1 112h.6v.8h-.6zM132.1 113.5h.6v.9h-.6zM132.4 104.4l.9-.1 .1 .2-.1 .7h-.2h-.7l-.1-.2zM133.5 119.4l1.5-.1 .1 .1v.4l-.2 .1h-1.3l-.1-.1zM133.5 118.1h1.5l.1 .1v.4l-.2 .1h-1.3l-.1-.2zM134.5 110.4l.6-.1 .2 .1v.7v.2l-.7 .1-.1-.1z"/>
<path d="M134.5 108.6h.6l.2 .1v.7v.2h-.7l-.1-.1zM136.6 117h.7h.2v.8l-.1 .2h-.6l-.2-.1zM136.6 118.8l.7-.1 .2 .1v.7l-.1 .2-.6 .1-.2-.1zM138.5 112.7h.9l.1 .2-.1 .6-.2 .1h-.7l-.1-.2zM138.5 118.8h.9l.1 .2-.1 .6-.2 .1h-.7l-.1-.2zM138.5 116.6l.9-.1 .1 .2-.1 .6-.2 .1h-.7l-.1-.2zM139.3 110.4l.6-.1 .2 .1 .1 .7-.1 .2-.6 .1-.2-.1zM139.3 108.6h.6l.2 .1 .1 .7-.1 .2h-.6l-.2-.1zM140.2 112.7h.9l.1 .2v.6l-.2 .1h-.7l-.1-.2zM140.2 118.8h.9l.1 .2v.6l-.2 .1h-.7l-.1-.2zM140.2 116.6l.9-.1 .1 .2v.6l-.2 .1h-.7l-.1-.2zM142.1 109h.7v.6h-.7z"/>
<path d="M142.1 110.4h.7v.6h-.7zM143 101.1l.8-.1 .2 .1 .1 1.1-.1 .2h-.8l-.2-.1-.1-1zM145 101.1l.9-.1 .2 .1v1.1l-.1 .2h-.8l-.2-.1v-1zM145.3 112.6l.6-.1 .2 .1v.7v.2l-.7 .1-.2-.1zM145.3 114.3h.6l.2 .1v.7v.2h-.7l-.2-.1zM145.3 117.8l.6-.1 .2 .1v.7v.2l-.7 .1-.2-.1zM145.3 119.5h.6l.2 .1v.7v.2h-.7l-.2-.1zM146.8 108.6h.6l.2 .1 .1 .7-.1 .2h-.6l-.2-.1zM146.8 110.4l.6-.1 .2 .1 .1 .7-.1 .2-.6 .1-.2-.1zM147.6 111.9h.5v1h-.5zM148.4 111.9h.5v1h-.5zM149.2 111.9h.5v1h-.5z"/>
<path d="M149.1 110.4l.6-.1 .2 .1 .1 .7-.1 .2-.7 .1-.1-.1zM149.1 108.6h.6l.2 .1 .1 .7-.1 .2h-.7l-.1-.1zM150 111.9h.5v1h-.5zM150.8 111.9h.5v1h-.5zM151.6 111.9h.5v1h-.5zM151.1 101.9l.6-.1 .2 .1 .1 .8-.1 .1-.6 .1-.2-.1zM151.1 103.7l.6-.1 .2 .1 .1 .7-.1 .2h-.6h-.2zM151.3 100.3h.9l.1 .2v.6l-.2 .1-.8-.1v-.2zM152.4 111.9h.5v1h-.5zM151.4 110.1l.2-.1 1 .1 .1 .2v.8l-.2 .1-1.1-.1-.1-.2zM151.4 108.1l.2-.1 1 .1 .1 .1v.9h-.2h-1.1l-.1-.2zM149 109.9h.7a.56 .56 0 0 0 .6-.5v-.6l.2 .2 .6 .1 .3 .3 1.1 .1a.57 .57 0 0 0 .5-.6v-.7l.2 .2v1.2l.6 .7v1.3h-1.4l-.3 .1v1.4l-.4 .3-.2-.3 .2-.1v-1.3l-.4-.1h-1.3l.1-.2v-.2h1l.2 .2h.5v-.6h.4v.5l.6 .1 .1-.2v-.3l-1.7-.1-.1 .4h-1v-.2l-.8 .1v-.9h.4v.5h.4v-.4l-.1-.2-.7 .1-.3-.1v-.1h2.1l.1 .4h.6v-.5h.4v.5h.7v-.5h-.2h-1.4l-.2 .1h-2.1z"/>
<path d="M153.2 111.9h.5v1h-.5zM153.1 100.3h.9l.1 .2-.1 .6-.2 .1-.7-.1-.1-.2zM154 111.9h.5v1h-.5zM153.4 101.9l.6-.1 .2 .1 .1 .8-.1 .1-.6 .1-.2-.1zM153.4 103.7l.6-.1 .2 .1 .1 .7-.1 .2h-.6h-.2zM154.8 111.9h.5v1h-.5zM154.2 108.6h.6l.2 .1v.7l-.1 .2h-.6l-.2-.1zM154.2 110.4l.6-.1 .2 .1v.7l-.1 .2-.6 .1-.2-.1zM154.5 98.7l.4-.1v5.1l-.8-.4h-.6l-.4 .2v-.6l.1 .2h.4v-.5h.4v.5h.3l.1-.1v-.4h-1.2l-.1 .3v-1.1l.1 .4h.4v-.5h.4v.5l.5-.1-.1-.3-.1-.1h-1l-.2 .1v-.3h.7a.56 .56 0 0 0 .6-.6l-.1-.7a.35 .35 0 0 1-.2-.4 .35 .35 0 0 1 .2-.3l.1-.6zM155.3 110.4h.1l.1 .3h1.2v-.3h1v.7l.1 .5h-.6l-.4 .1v1.3l.1 .1v.2l-.3-.1-.3 .1 .2-.3v-1.3l-.4-.1 .6-.1v-.4l-1.2-.1-.1 .4 .2 .2h-.4l.1-.4zM155.6 111.9h.5v1h-.5zM155.7 110.4l.6-.1 .2 .1 .1 .7-.1 .2-.7 .1-.1-.1z"/>
<path d="M155.7 108.6h.6l.2 .1 .1 .7-.1 .2h-.7l-.1-.1zM156.4 111.9h.5v1h-.5zM157.2 111.9h.5v1h-.5zM158 111.9h.5v1h-.5zM158.1 108.6h.6l.2 .1 .1 .7-.1 .2h-.6l-.2-.1zM158.1 110.4l.6-.1 .2 .1 .1 .7-.1 .2-.6 .1-.2-.1zM158.8 111.9h.5v1h-.5zM159.6 111.9h.5v1h-.5zM160.4 111.9h.5v1h-.5zM160.4 103.7l.6-.1 .2 .1 .1 .7-.1 .2h-.7h-.1zM160.4 101.9l.6-.1 .2 .1 .1 .8-.1 .1-.7 .1-.1-.1zM161.2 111.9h.5v1h-.5z"/>
<path d="M161.3 110.4l.6-.1 .2 .1v.7v.2l-.7 .1-.2-.1zM161.3 108.6h.6l.2 .1v.7v.2h-.7l-.2-.1zM162 111.9h.5v1h-.5zM162.8 111.9h.5v1h-.5zM163.6 111.9h.5v1h-.5zM164.4 111.9h.5v1h-.5zM165.2 111.9h.5v1h-.5zM164.7 103.7l.6-.1 .2 .1 .1 .7-.1 .2h-.6h-.2zM164.7 101.9l.6-.1 .2 .1 .1 .8-.1 .1-.6 .1-.2-.1zM164.8 106.9h.9l.1 .2-.1 .6-.2 .1-.7-.1-.1-.2zM166 111.9h.5v1h-.5zM166.8 111.9h.5v1h-.5z"/>
<path d="M166.5 106.9h.9l.1 .2v.6l-.2 .1-.7-.1-.1-.2zM166.9 110.4l.6-.1 .2 .1v.7l-.1 .2-.6 .1-.2-.1zM166.9 108.6h.6l.2 .1v.7l-.1 .2h-.6l-.2-.1zM167.6 111.9h.5v1h-.5zM168.4 111.9h.5v1h-.5zM168.5 108.6h.6l.2 .1 .1 .7-.1 .2h-.6l-.2-.1zM168.5 110.4l.6-.1 .2 .1 .1 .7-.1 .2-.6 .1-.2-.1zM170.9 117.5l.7-.1 .1 .1 .1 .8-.1 .1-.6 .1-.2-.1zM170.9 115.8l.7-.1 .1 .1 .1 .7-.1 .2h-.6h-.2zM170.9 119.4h.7l.1 .1 .1 .7-.1 .2h-.6l-.2-.1zM173.2 100.8h.6l.2 .1 .1 .7-.1 .2h-.6l-.2-.1zM173.2 102.6l.6-.1 .2 .1 .1 .7-.1 .2-.6 .1-.2-.1z"/>
<path d="M173.7 111.5h.9l.1 .1-.1 .7-.2 .1-.7-.1-.1-.2zM173.7 106.9h.9l.1 .2-.1 .6-.2 .1-.7-.1-.1-.2zM173.7 108.4h.9l.1 .2-.1 .6-.2 .1h-.7l-.1-.2zM173.7 113h.9l.1 .2-.1 .6-.2 .1-.7-.1-.1-.2zM173.7 105.4h.9l.1 .1-.1 .7-.2 .1-.7-.1-.1-.2zM173.7 114.5h.9l.1 .2-.1 .6-.2 .1h-.7l-.1-.2zM175.4 111.5h.9l.1 .1v.7l-.2 .1-.8-.1v-.2zM175.4 106.9h.9l.1 .2v.6l-.2 .1-.8-.1v-.2zM175.4 108.4h.9l.1 .2v.6l-.2 .1h-.8v-.2zM175.4 113h.9l.1 .2v.6l-.2 .1-.8-.1v-.2zM175.4 105.4h.9l.1 .1v.7l-.2 .1-.8-.1v-.2zM175.4 114.5h.9l.1 .2v.6l-.2 .1h-.8v-.2z"/>
<path d="M176.8 100.8h.6l.2 .1v.7v.2h-.7l-.2-.1zM176.8 102.6l.6-.1 .2 .1v.7v.2l-.7 .1-.2-.1zM178.4 112.7l.7-.1 .1 .1 .1 .8-.1 .1-.6 .1-.2-.1zM178.4 114.5l.7-.1 .1 .1 .1 .7-.1 .2h-.6h-.2zM179.9 105.9h.9l.1 .2-.1 .6-.2 .1-.7-.1-.1-.2zM179.9 104.4l.9-.1 .1 .2-.1 .7h-.2h-.7l-.1-.2zM180.1 102.5h.6h.2v.8v.1l-.7 .1-.2-.1zM180.1 100.8l.6-.1 .2 .1v.7v.2l-.7 .1-.2-.1zM180.7 114.5l.6-.1 .2 .1 .1 .7-.1 .2h-.6h-.2zM180.7 112.7l.6-.1 .2 .1 .1 .8-.1 .1-.6 .1-.2-.1zM179.1 107.4l.2-.1 2.3 .1v.1v2.3l-.2 .1-2.3-.1-.1-.2zM181.6 105.9h.9l.1 .2v.6l-.2 .1-.7-.1-.1-.2z"/>
<path d="M181.6 104.4l.9-.1 .1 .2v.7h-.2h-.7l-.1-.2zM182.2 114.5l.7-.1 .1 .1 .1 .7-.1 .2h-.6h-.2zM182.2 112.7l.7-.1 .1 .1 .1 .8-.1 .1-.6 .1-.2-.1zM182.6 102.5h.6h.2l.1 .8-.1 .1-.6 .1-.2-.1zM182.6 100.8l.6-.1 .2 .1 .1 .7-.1 .2-.6 .1-.2-.1zM183.8 114.6l.2-.1h1l.1 .2-.1 .8-.1 .1h-1.1l-.1-.2zM183.8 112.5l.2-.1 1 .1 .1 .2-.1 .8-.1 .1-1.1-.1-.1-.2zM187.8 112.7h.9l.1 .2-.1 .6-.2 .1h-.7l-.1-.2zM187.8 109.7h.9l.1 .2-.1 .6-.2 .1-.7-.1-.1-.2zM187.8 106.4h.9l.1 .2-.1 .6-.2 .1-.7-.1-.1-.2zM187.8 103.3h.9l.1 .2-.1 .6-.2 .1h-.7l-.1-.2zM188.8 111.2h.9l.1 .2-.1 .6-.2 .1-.7-.1-.1-.1z"/>
<path d="M188.8 104.9h.9l.1 .1-.1 .7-.2 .1-.7-.1-.1-.2zM189.5 112.7h.9l.1 .2-.1 .6-.1 .1h-.8v-.2zM189.5 109.7h.9l.1 .2-.1 .6-.1 .1-.8-.1v-.2zM189.5 106.4h.9l.1 .2-.1 .6-.1 .1-.8-.1v-.2zM189.5 103.3h.9l.1 .2-.1 .6-.1 .1h-.8v-.2zM190.5 111.2h.9l.1 .2v.6l-.2 .1-.7-.1-.1-.1zM190.5 104.9h.9l.1 .1v.7l-.2 .1-.7-.1-.1-.2zM191 114.3l1.1-.1 .2 .1 .1 1.4-.1 .2h-1.1l-.2-.1v-1.4zM191 101h1.1l.2 .1 .1 1.4-.1 .2h-1.1l-.2-.1v-1.4zM194 114.3l1.1-.1 .2 .1 .1 1.4-.1 .2h-1.1l-.2-.1-.1-1.4zM194 101h1.1l.2 .1 .1 1.4-.1 .2h-1.1l-.2-.1-.1-1.4zM196.5 107.7l1.1-.1 .2 .1 .1 1.4-.1 .2h-1.1l-.2-.1v-1.4z"/>
<path d="M197.8 104.9h.9l.1 .1-.1 .7-.2 .1-.7-.1-.1-.2zM197.8 111.2h.9l.1 .2-.1 .6-.2 .1-.7-.1-.1-.1zM199.6 104.9h.8l.1 .1v.7l-.2 .1-.7-.1-.1-.2zM199.6 111.2h.8l.1 .2v.6l-.2 .1-.7-.1-.1-.1zM199.5 107.7l1.1-.1 .2 .1 .1 1.4-.1 .2h-1.1l-.2-.1-.1-1.4zM199.5 104.5h1.6h.1v7.9l-.1 .1h-1.6v-.1v-.1l.4-.1v-.5h.2v.6h.5l.1-.2v-.4h-.8v-.7h.2v.6h.6v-.6h-1.2v-1.5h.6v-1h.1l.1 1h.6l.2-.2-.1-.8h-.9v-1.1h.1v1l.9-.1-.1-.9h-1.5v-1.5h.4v-.6h.2v.6h.5l.1-.1v-.5h-.8v-.6h.2v.5h.6v-.5l-.1-.1-.7 .1-.4-.1zM188.4 118.4l.1-.1h13.9l.1 .1v13.8l.2 .2h4l.1 .1v6.8l-.1 .1h-8.2l-.1-.1v-3.1h6.2a.81 .81 0 0 0 .8 0l-.4-.4-.4 .4h-6.2v-1.2h5.3l.1 .4 .4-.5h1.6l.4 .5a.81 .81 0 0 0 0-.9l-.4 .4h-1.6l-.4-.4-.1 .5h-5.3v-1.3h6.2l.4 .4 .4-.4a.81 .81 0 0 0-.8 0h-6.2v-1.8l-.1-.1h-9.8l-.1-.1v-1.2h7.7a.73 .73 0 0 0 .8 0l-.4-.4-.4 .4h-7.7v-1.2h6.8l.1 .4 .4-.4h1.6l.4 .4a.73 .73 0 0 0 0-.8l-.4 .4h-1.6l-.4-.4-.1 .4h-6.8v-1.2h7.7l.4 .4 .4-.4a.73 .73 0 0 0-.8 0h-7.7zM203.1 118.4l.1-.1h4.5l.1 .1v4.2l-.1 .1h-4.5l-.1-.1zM195.1 100.6l.1-.1h21.6l.1 .1v2.1l.1 .2h12.2l.1 .1v7.2l-.1 .1h-2.2l-.1-.1v-4.8l-.2-.2h-12.4l-.1-.1v-.4h4.7l.2 .2 .4 .1 .3-.1 .2-.2h4a.78 .78 0 0 0 1.1 0l-.6-.6-.5 .6h-4l-.5-.6-.6 .6h-4.7v-.6h4.3l.1 .3 .2 .2 .6-.5h.1l.6 .5 .2-.2 .1-.3h3.2l.1 .3 .2 .2 .6-.5h.1l.6 .5 .3-.4-.1-.5-.2-.2-.6 .6h-.1l-.6-.6-.2 .2-.1 .4h-3.2l-.1-.4-.2-.2-.6 .6h-.1l-.6-.6-.2 .2-.1 .4h-4.3v-.7h4.7l.6 .6 .5-.6h4l.5 .6 .6-.6-.2-.2-.4-.1-.3 .1-.2 .2h-4a.78 .78 0 0 0-1.1 0h-4.7v-1.1l-.2-.1h-17.4l-.2 .2v2.3a.57 .57 0 0 0-.5 .6 .57 .57 0 0 0 .5 .5v1.1l.2 .2h1.6l.1 .1v2.5l-.1 .1h-1.6l-.2 .2v1.1a.57 .57 0 0 0-.5 .6 .57 .57 0 0 0 .5 .5v2.3l.2 .2h16.6l.2-.1v-.4h5.1l.1 .4 .2 .2 .6-.6h.1l.6 .6 .2-.2 .1-.4h3.2l.1 .4 .2 .2 .6-.6h.1l.6 .6 .3-.4-.1-.6-.2-.2-.6 .6h-.1l-.6-.6-.2 .3-.1 .3h-3.2l-.1-.4-.2-.2-.6 .6h-.1l-.6-.6-.2 .3-.1 .3h-5.1v-.7h5.5l.6 .6 .5-.6h4l.5 .6 .6-.6-.2-.2h-.4l-.3 .1-.2 .1h-4a.78 .78 0 0 0-1.1 0h-5.5v-.3l.1-.1h13.2l.2-.2v-2.1l.1-.1h2.2l.1 .1v4.5l-.1 .1h-12.5l-.2 .2v1h-.1h-21.2h-.1v-1.7h23.8l.2 .2 .4 .1 .3-.1 .2-.2h4a.78 .78 0 0 0 1.1 0l-.6-.6-.5 .6h-4l-.5-.6-.6 .6h-23.8v-5.6h1.2l.1 .2h.7v-1h.1l.1 1h.6l.2-.2-.1-.8h-1.7v.8h-1.2v-1.7h1.2v.8h.8v-1h.1v1h.8l.1-.8-.2-.2h-1.4l-.2 .2h-1.2zM220.3 118.3h3.4a1.33 1.33 0 0 0 .5 2.3 1.33 1.33 0 0 0-1 1.2 1.33 1.33 0 0 0 1 1.3 1.33 1.33 0 0 0-.7 2.1 1.33 1.33 0 0 0 2.1 0 1.33 1.33 0 0 0-.7-2.1 1.33 1.33 0 0 0 1-1.3 1.33 1.33 0 0 0-1-1.2 1.33 1.33 0 0 0 .5-2.3h3.8l.1 .1v12.3h-.1h-10.5l-.1-.4 .9 .1 .2-.1h4.6l.3 .1 .2-.1-.3-.2-.2 .2h-4.6l-.2-.2-.3 .2h-.6v-.6l.2-.2h1.3l.2 .2 .1-.2h3.2l.1 .2 .2-.2h1.3l.2 .2 .1-.3-.1-.2-.2 .3h-1.3l-.2-.3-.1 .3h-3.2l-.1-.3-.2 .3h-1.3l-.2-.2v-.7h.6l.3 .2 .2-.2h4.6l.2 .2 .3-.2-.3-.1-.2 .1h-4.6l-.3-.1-.8 .1v-.8l.9 .1 .2-.1h4.6l.3 .1 .2-.1-.3-.3-.2 .3h-4.6l-.2-.3-.3 .3h-.6v-.7l.2-.2h1.3l.2 .3 .1-.2h3.2l.1 .2 .2-.3h1.3l.2 .3 .1-.3-.1-.2-.2 .2h-1.3l-.2-.2-.1 .3h-3.2l-.1-.3-.2 .2h-1.3l-.2-.2v-.6h.6l.3 .2 .2-.2h4.6l.2 .2 .3-.2-.3-.1-.2 .1h-4.6l-.3-.1-.8 .1v-.7a1.33 1.33 0 0 0 2-.4 1.33 1.33 0 0 0-.8-1.9 1.33 1.33 0 0 0 1-1.3 1.33 1.33 0 0 0-1-1.2 1.33 1.33 0 0 0 .5-2.3zM74 131.2l.9-.1 .1 .2-.1 .7h-.2h-.7l-.1-.2zM74 133.7h.9l.1 .2-.1 .6-.2 .1-.7-.1-.1-.2z"/>
<path d="M74.8 125.7l.1-.1 1.4 .1 .1 .2v1l-.2 .1h-1.4l-.1-.2zM74.8 122.7l.1-.1 1.4 .1 .1 .2v1.1l-.2 .1-1.4-.1-.1-.2zM75.7 131.2l.9-.1 .1 .2v.7h-.2h-.8v-.2zM75.7 133.7h.9l.1 .2v.6l-.2 .1-.8-.1v-.2zM77.9 125.7l.2-.1 1.4 .1 .1 .2v1l-.2 .1h-1.4l-.1-.2zM77.9 122.7l.2-.1 1.4 .1 .1 .2v1.1l-.2 .1-1.4-.1-.1-.2zM78.4 129.1l1.1-.1 .2 .1v1.4v.2l-1.1 .1-.2-.1-.1-1.4zM70.5 125.5l.1-.1h9.5l.1 .1v6.4h-3.3v-.1h-1.4l-.5 .7v-.2l.3-.4-.1-.8h.3v.3h.5v-.5h.4v.5h.5v-.3l-.2-.2h-1.1l-.1 .2h-.3l-.3-.3h3.2l.2 .2h.5v-.9h.4v.8l.6 .1 .1-.2v-.7h-1.7l-.1 .7h-4.1l-.2 .1-.2 .3v.7l.3 .4v1.1l-.2 .1a.6 .6 0 0 0-.6 .7 .6 .6 0 0 0 .7 .5l.3 .2 .9-.1a.82 .82 0 0 0 .7 1h.8v4.4a.82 .82 0 0 0 .7 .6h2.6v6.8h-9.2l-.1-.1v-4.2h3.1v.6l.2 .2 .3 .2h.6l.3-.1 .2-.2h.3l.1 .2h.4v-.5h-.5v.3h-.3v-1h.3v.3h.5v-.4h.4v1.2l.4 .1 .1-.2h.1a.82 .82 0 0 0 1.2 .1 .82 .82 0 0 0-.1-1.2 .82 .82 0 0 0-1.2 .2l-.2-.3h-1.1l-.1 .2h-.3l-.2-.3 .3-.3a.6 .6 0 0 0 .6-.7 .6 .6 0 0 0-.8-.4l-.4 .1-.7 .7-.1 .7-.2 .2-.1 .3h-3.1v-14.3h7.6l.1 .7h.6v-.8h.4v.8h.7v-.7l-.2-.2h-1.4l-.2 .2h-7.6v-2h4l.2 .2h.6l.1-.7h.4v.7h.7l.1-.2h1.1l.1 .2h.7v-.7h.4v.7h.7l.2-.1v-.5l-2.1-.1v.5h-1.1v-.5h-2.1v.5h-4v-1.4h4v.5h.9v-.6h.4v.6h.8v-.5h1.1v.5h.8v-.6h.4v.6h.9v-.5l-.2-.2h-1.8l-.1 .2h-1.1l-.2-.2h-1.7l-.2 .2h-4zM80.7 137.1l1.1-.1 .2 .1v1.4l-.1 .2-1 .1-.2-.1-.1-1.4zM77.2 135.9v-.1h5.2l.1 .1v4.1l-.1 .1h-5.2v-.1v-1.2h3.2l.1 .2h.2v-.5h1.2v.4l.1 .1 .2-.1v-.4h-1.7l-.1 .3h-3.2v-1.8h3.2l.1 .3h.2v-.4h1.2v.4h.3v-.3l-.2-.2-1.4 .1-.2 .1h-3.2zM81.4 129.1l1.1-.1 .2 .1v1.4l-.1 .2-1.1 .1-.2-.1v-1.4zM83.7 137.1l1.1-.1 .1 .1 .1 1.4-.1 .2-1.1 .1-.2-.1v-1.4z"/>
<path d="M87.2 138.4h2.1v1.4h-2.1zM80.8 125.5l.1-.1h9.4l.1 .1v6.3l-.1 .1h-9.4l-.1-.1v-1h.3l.1 .1 .2 .1v-.5h1.2v.4l.2 .1 .1-.1v-.4h-1.7l-.1 .3h-.3v-1.8h.3l.1 .3h.2v-.4h1.2v.4h.3v-.3l-.2-.2h-1.4l-.2 .2h-.3zM83.1 135.9l.1-.1h7.1l.1 .1v4.1l-.1 .1h-7.1l-.1-.3h3.9l.1 .2h.5l.1-.3h1.1l.1 .3h.4h.2v-.2l-2.4-.1-.1 .1h-3.9v-1h.3l.1 .2h.2v-.5h1.2v.5h.2l.1-.2-.1-.3h-1.7v.3h-.3v-.4h3.9l.1 .2h.6v-.3h1.1v.3h.7v-.2l-.2-.1h-2.1l-.2 .1h-3.9v-1.4h.3v.3h.3v-.4h1.2v.4h.2l.1-.3-.2-.2h-1.4l-.2 .2h-.3zM75.7 132.6l14.6-.1 .1 .1v2.5l-.1 .1h-14.6l-.1-.4 .1-.1v-.2h.9l.1 .3 .2-.2-1.2-.1v-1h.9v.2l.3-.1-.2-.2h-1.1zM95.3 122.8h.2h1.4l.1 .2v1.1l-.2 .1-1.4-.1-.1-.2zM95.3 125.8l.2-.1 1.4 .1 .1 .2v1.1l-.2 .1-1.4-.1-.1-.2zM97.2 133.2h2.1v1.4h-2.1zM97.2 128.8h2.1v1.4h-2.1zM98.4 138.8l.2-.1h1.4l.1 .2-.1 1.1-.2 .1h-1.4l-.1-.2zM98.4 135.8l.2-.1 1.4 .1 .1 .2-.1 1-.2 .1h-1.4l-.1-.2zM98.5 122.8h.2h1.4l.1 .2-.1 1.1-.2 .1-1.4-.1-.1-.2zM98.5 125.8l.2-.1 1.4 .1 .1 .2-.1 1.1-.2 .1-1.4-.1-.1-.2z"/>
<path d="M91 125.5l.1-.1h9.5v.1v6.3v.1h-9.5l-.1-.1v-1.6h6.1l.1 .2h.5v-.3h1.2v.3h.4l.2-.1v-.2h-2.4v.1h-6.1v-1.4h6.1v.1h.6v-.2h1.2v.2h.6v-.1l-.2-.2h-2.1l-.1 .2h-6.1v-1.6h4.1l.1 .1 .3 .1 .1-.4h1.1l.1 .4 .3-.1 .1-.1h1l.2 .1 .3 .1v-.4h1.2v.3l.3 .1 .1-.1 .1-.2-2.1-.1-.1 .2h-1v-.2h-2.1v.2h-4.1v-1.5h4.1v.2h.5v-.3h1.1v.3h.5v-.2h1l.1 .2h.4v-.3h1.2v.3h.4l.1-.2-.2-.2h-1.8l-.2 .2h-1l-.2-.2h-1.8l-.1 .2h-4.1zM97.1 132.5h4.2l.1 .1v4.9l-.1 .1h-4.2l-.1-.1v-.4h1.1l.2 .2h.3v-.3h1.2v.3h.3l.2-.2-.1-.1h-2l-.1 .1h-1.1v-1.4h1.1l.1 .2h.4v-.3h1.2v.3l.5-.1-.1-.2-.1-.1h-1.8l-.2 .2h-1.1v-1.1l.2 .2h.5v-.3h1.2v.3h.5l.1-.2v-.1h-2.4l-.1 .1v-1.4l.1 .1h.6v-.2h1.2v.2h.6v-.2l-.2-.1h-2.1l-.2 .2v-.6zM97.1 138.2h4.2l.1 .1v5.3l-.1 .1h-2.9a1.25 1.25 0 0 0-1.4-.3v-3.3h1.1l.2 .2h.3v-.3h1.2v.3h.3l.2-.2-.1-.1h-2l-.1 .1h-1.1v-1.4h1.1l.1 .1h.4v-.3h1.2v.3h.5l-.1-.2-.1-.1h-1.8l-.2 .2h-1.1v-.4zM103.6 122.8h.2h1.4l.1 .2-.1 1.1-.2 .1-1.4-.1-.1-.2zM103.6 125.8l.2-.1 1.4 .1 .1 .2-.1 1.1-.2 .1-1.4-.1-.1-.2zM102.1 135.7h6.2l.1 .1v4.2l-.1 .1h-6.2l-.1-.1v-4.2zM101.3 125.5l.1-.1h9.3l.1 .1v6.3l-.1 .1h-9.3l-.1-.1v-4.6h2l.1 .1 .4 .1v-.4h1.2v.3l.3 .1 .1-.1 .1-.2-2.1-.1-.1 .2h-2v-1.5h2l.1 .2h.4v-.3h1.2v.3h.4l.1-.2-.2-.2h-1.8l-.2 .2h-2zM112.5 125.3l.6-.1 .2 .1 .1 .7-.1 .2h-.6l-.2-.1zM112.5 123.5l.6-.1 .2 .1 .1 .7-.1 .2-.6 .1-.2-.1zM113.9 138.4l.6-.1 .2 .1 .1 .7-.1 .2h-.6h-.2zM113.9 131.5l.6-.1 .2 .1 .1 .7-.1 .2-.6 .1-.2-.1zM113.9 133.3l.6-.1 .2 .1 .1 .7-.1 .2h-.6l-.2-.1z"/>
<path d="M114.4 135.5h.9v.1v.7l-.2 .1-.7-.1-.1-.2zM114.4 123.3l1.1 .3 .1 .7 .4 .5-.1 .1-.5-.4-.7-.1zM115.4 131.5l.7-.1 .1 .1 .1 .7-.1 .2-.6 .1-.2-.1zM115.4 133.3l.7-.1 .1 .1 .1 .7-.1 .2h-.6l-.2-.1zM115.4 138.4l.7-.1 .1 .1 .1 .7-.1 .2h-.6h-.2zM116.1 135.5h.9l.1 .1-.1 .7-.1 .1-.8-.1-.1-.2zM111.5 132.9h5.4l.1 .1v1.6l-.1 .1h-1.2l-.2 .2v.4l-.2-.1-.3 .1v1.2l.3 .1 .2-.1-.1 .3h-3.9l-.1-.1v-.3h2.7l.1 .1h.4v-.4h-.4l-.1 .3h-2.7v-1h2.7l.1 .3h.4v-.4l-.3-.1-.2 .2h-2.7v-1.2h2.2l.2 .2h.3v-.5h.4v.5h.3l.2-.2h.2l.1 .2h.3v-.5h.4l.1 .5h.3l.1-.2-.1-.3h-1.2v.3h-.2l-.1-.3h-1.2l-.1 .3h-2.2v-1h2.2l.1 .3h.4v-.5h.4v.5h.4l.1-.3h.2v.3h.4v-.5h.4v.5h.5v-.4l-.2-.1h-1l-.1 .2h-.2l-.2-.2h-1l-.2 .2h-2.2zM111.5 139.8h5.4h.1v1.6l-.1 .1h-1.2l-.2 .2v.5l-.2-.1h-.3v1.3h.3l.2-.1v.4l-.1 .1h-3.9l-.1-.1v-.5h2.7l.1 .2h.4v-.5h-.4l-.1 .3h-2.7v-.9h2.7l.1 .3h.4v-.5h-.3l-.2 .2h-2.7v-1.2h2.2l.2 .2h.3v-.5h.4v.5h.3l.2-.2h.2l.1 .2h.3v-.5h.4l.1 .5h.3l.1-.2-.1-.3h-1.2v.3h-.2l-.1-.3h-1.2l-.1 .3h-2.2v-1.1h2.2l.1 .4h.4v-.5h.4v.5h.4l.1-.4h.2v.4h.4v-.5h.4v.5l.5-.1v-.3l-.2-.1h-1l-.1 .1h-.2l-.2-.1h-1l-.2 .1h-2.2zM116.8 121l1-.6 .6 .4 .7 .2v.1l-.8 .2-.5 .3zM116.8 123.6l1-.6 .5 .3 .8 .2v.1l-.7 .1-.6 .4zM116.4 127.8h1.7v1.7h-1.7zM119.3 138.3h.9l.1 .1-.1 .7-.1 .1-.8-.1-.1-.2z"/>
<path d="M119.3 136h.9l.1 .2-.1 .6-.1 .1-.8-.1-.1-.2zM121.1 138.3h.9l.1 .1-.1 .7-.2 .1-.7-.1-.1-.2zM121.1 136h.9l.1 .2-.1 .6-.2 .1-.7-.1-.1-.2zM118 122.7l.6-.1 .4-.3h3.1l.1 .3h1.2l.1-.3h.2v.9l.3 .4h-3.7l-.2-.3h2l.2 .2h.3v-.5h.4v.5h.3l.2-.1v-.4h-1.3l-.1 .3h-2l-.2-.1-1.3-.1zM122.4 122.3h.6l.2 .1 .1 .7-.1 .2h-.6l-.2-.1zM122.4 120.6l.6-.1 .2 .1 .1 .7-.1 .2-.6 .1-.2-.1zM122.4 126.4l.6-.1 .2 .1 .1 .7-.1 .2-.6 .1-.2-.1zM122.4 124.6h.6l.2 .1 .1 .7-.1 .2h-.6l-.2-.1zM122.9 138.3l.9-.1 .2 .1v1.1l-.1 .2h-.8l-.2-.1v-1zM123.1 136h.9l.1 .2v.6l-.2 .1-.8-.1v-.2zM123.1 133.7h.9l.1 .2v.6l-.2 .1-.8-.1v-.2zM124.1 122.3h.6l.2 .1v.7l-.1 .2h-.6l-.2-.1z"/>
<path d="M124.1 120.6l.6-.1 .2 .1v.7l-.1 .2-.6 .1-.2-.1zM124.8 124.6h.7l.1 .1 .1 .7-.1 .2h-.6l-.2-.1zM124.8 126.4l.7-.1 .1 .1 .1 .7-.1 .2-.6 .1-.2-.1zM124.9 136h.9l.1 .2-.1 .6-.2 .1-.7-.1-.1-.2zM124.9 133.7h.9l.1 .2-.1 .6-.2 .1-.7-.1-.1-.2zM125 138.3l.8-.1 .2 .1 .1 1.1-.1 .2h-.8l-.2-.1-.1-1zM126.3 120.6h1.5l.1 .1v.4l-.2 .1h-1.3l-.1-.1zM126.3 121.9h1.5l.1 .1v.4l-.2 .1h-1.3l-.1-.2zM127.4 124.6h.6l.2 .1v.7v.2h-.7l-.2-.1zM127.4 126.4l.6-.1 .2 .1v.7v.2l-.7 .1-.2-.1zM129 135l1.1-.1 .2 .1 .1 1.4-.1 .2h-1.1l-.2-.1v-1.4zM130 129.8l.9-.1 .2 .1v1.1l-.1 .2h-.8l-.2-.1v-1z"/>
<path d="M131.2 124.6h.6l.2 .1v.7v.2h-.7l-.1-.1zM131.2 126.4l.6-.1 .2 .1v.7v.2l-.7 .1-.1-.1zM127.2 139.5h5.1l.1 .1v4l-.1 .1h-5.1l-.1-.1v-.6h.9l.1 .2h.7v-.7h.4l.1 .7 .7-.1 .1-.6h.6l.4 .1 .3-.1-.3-.4-.4 .4h-2.7v.5h-.9v-1.4h.9v.5h.8v-.7h.4v.7h.8l.1-.2h.2l.1 .3 .4-.3h.5l.4 .3 .2-.4-.2-.3-.4 .4h-.5l-.4-.4-.1 .4h-.2v-.4l-.2-.1h-1.7l-.2 .2h-.9v-.4h3.6l.4 .4 .3-.4-.3-.1-.4 .1h-3.6v-1.6zM132.1 129.8l.8-.1 .2 .1 .1 1.1-.1 .2h-.8l-.2-.1-.1-1zM132 135l1.1-.1 .2 .1 .1 1.4-.1 .2h-1.1l-.2-.1-.1-1.4zM132.8 124.6h.7l.1 .1 .1 .7-.1 .2h-.6l-.2-.1zM132.8 126.4l.7-.1 .1 .1 .1 .7-.1 .2-.6 .1-.2-.1zM133.5 121.9h1.5l.1 .1v.4l-.2 .1h-1.3l-.1-.2zM133.5 120.6h1.5l.1 .1v.4l-.2 .1h-1.3l-.1-.1zM134.3 128.2h.9l.1 .2-.1 .6-.2 .1h-.7l-.1-.2zM123.3 124.3h1.4l.8-.7h10.1l.2 .2a.65 .65 0 0 0-.8 .6l-.1 .3v.9h-1l-.1-.3h-1.2v.3h-.3v-1h.3v.3h.4v-.5h.4v.5h.5v-.4l-.2-.1h-1l-.1 .2a.65 .65 0 0 1-.6-.6 .63 .63 0 0 0-1.1 .4l-.1 .3v.9h-2.4v-.3h-1.3v.3h-1.2l-.1-.3h-1.2v.3h-1l-.1-1h1.1v.3h.4v-.5h.4v.5h.4l.1-.3h1.2v.3h.5v-.5h.4v.5h.4v-.4l-.2-.1h-1l-.1 .2h-1.2l-.2-.2h-1l-.1 .2h-1.1zM135.2 126.4l.7-.1 .2 .1v.7l-.1 .2-.6 .1-.2-.1z"/>
<path d="M135.2 124.6h.7l.2 .1v.7l-.1 .2h-.6l-.2-.1zM136.1 128.2h.8l.1 .2v.6l-.2 .1h-.7l-.1-.2zM136.6 122.3h.7l.2 .1v.7l-.1 .2h-.6l-.2-.1zM136.6 120.6l.7-.1 .2 .1v.7l-.1 .2-.6 .1-.2-.1zM137.5 124.6h.7l.1 .1 .1 .7-.1 .2h-.6l-.2-.1zM137.5 126.4l.7-.1 .1 .1 .1 .7-.1 .2-.6 .1-.2-.1zM130.7 132.1h9.6l.1 .1v6.8l-.1 .1h-9.6l-.1-.1v-2.4h1.1l.2 .2 .1-.2h1.3l.1 .2 .1-.2h-2.9v-1.7h1.4v-.2h1.3v.2h.2l-.1-.2h-1.5l-.2 .2h-1.1v-2.7zM140.3 124.6h.7l.1 .1 .1 .7-.1 .2h-.6l-.2-.1zM140.3 126.4l.7-.1 .1 .1 .1 .7-.1 .2-.6 .1-.2-.1zM141.4 136.8h1v1h-1zM141.7 129.1l.7-.1 .1 .1 .1 .7-.1 .2-.6 .1-.2-.1zM141.7 130.8h.7l.1 .1 .1 .7-.1 .2h-.6l-.2-.1z"/>
<path d="M141.8 133.8h.9l.1 .2-.1 .6-.2 .1h-.7l-.1-.2zM143.5 133.8h.9l.1 .2v.6l-.2 .1h-.7l-.1-.2zM144.2 129.1l.7-.1 .2 .1v.7l-.1 .2-.6 .1-.2-.1zM144.2 130.8h.7l.2 .1v.7l-.1 .2h-.6l-.2-.1zM134.9 139.5h10.2l.1 .1v4l-.1 .1h-10.2l-.1-.1v-.6h4.5l.1 .2h.7v-.7h.4l.1 .7h.6l.2-.2v-.5h-2.1v.5h-4.5v-.5h.6l.1 .1h.4l.1-.6h.3l.1 .6h.4l.1-.1v-.5h-1.5v.5h-.6v-1.2h.6v.4h.6v-.6h.3v.6h.6v-.1h2.4v.5h.8v-.7h.4v.7l.9-.1v-.5l-.2-.1h-1.7l-.2 .2h-2.4v-.4l-.1-.1h-1.3l-.1 .2h-.6v-1.7zM145.3 123l.6-.1 .2 .1v.7v.2h-.7h-.2zM145.3 121.2l.6-.1 .2 .1v.8v.1l-.7 .1-.2-.1zM145.3 124.6h.6l.2 .1v.7v.2h-.7l-.2-.1zM145.3 126.4l.6-.1 .2 .1v.7v.2l-.7 .1-.2-.1zM145.2 133.8h.9l.1 .2v.6l-.2 .1h-.8v-.2zM146.9 135h.1l.1 .4 .2 .3-.4 .5-.3-.5 .2-.3zM146.9 129.1l.7-.1 .1 .1 .1 .7-.1 .2-.6 .1-.2-.1z"/>
<path d="M146.9 130.8h.7l.1 .1 .1 .7-.1 .2h-.6l-.2-.1zM147.6 123.1h.5v1h-.5zM147 133.8h.9l.1 .2-.1 .6-.2 .1h-.7l-.1-.2zM148.4 123.1h.5v1h-.5zM149.2 123.1h.5v1h-.5zM150 123.1h.5v1h-.5zM148.9 136.8h1.5l.3 .2h.9l.5-.2 .1 .1v2.4l.2 .2h.7l.1 .1v4l-.1 .1h-4.2l-.1-.1v-.6h.2l.2 .2 .7-.1v-.6h.4l.1 .7 .7-.1 .1-.6h.6l.4 .1 .3-.1-.4-.4-.3 .4h-2.7l-.1 .5h-.2v-1.4h.2l.1 .5h.8v-.7h.4v.7h.8l.1-.2h.2l.1 .3 .4-.3h.5l.4 .3 .1-.4-.1-.3-.4 .4h-.5l-.4-.4-.1 .4h-.2v-.4l-.2-.1h-1.8l-.2 .2h-.2v-.4h3l.3 .4 .4-.4-.4-.1-.3 .1h-3v-4.3zM150.8 123.1h.5v1h-.5zM151.6 123.1h.5v1h-.5zM151 126.4l.6-.1 .2 .1 .1 .7-.1 .2-.7 .1-.1-.1zM151 124.6h.6l.2 .1 .1 .7-.1 .2h-.7l-.1-.1zM150.5 135l1.1-.1 .2 .1 .1 1.4-.1 .2h-1.1l-.2-.1v-1.4z"/>
<path d="M152.4 123.1h.5v1h-.5zM152.5 124.6h.6l.2 .1 .1 .7-.1 .2h-.6l-.2-.1zM152.5 126.4l.6-.1 .2 .1 .1 .7-.1 .2-.6 .1-.2-.1zM153.2 123.1h.5v1h-.5zM154 123.1h.5v1h-.5zM153.5 135l1.1-.1 .2 .1 .1 1.4-.1 .2h-1.1l-.2-.1-.1-1.4zM153.8 117.7l.9-.8v5.9l-.3 .1v1.3l.4 .2h.7l-.2 .3v.8h-1.7l-.1-.2h-1.2l-.1 .2-.1-.9 .2-.2h.1l-.2 .1 .1 .4h1.2l.1-.4-.2-.1h.3l.4-.2v-1.3l-.3-.1zM154.8 123.1h.5v1h-.5zM153.6 126.2h1.8l.1 .5h1.2v-.5h.2l-.1 .3v.6a.69 .69 0 0 0 .8 .7h-4.3l.3-.4h1.8l.1 .2h.3l.1-.6h.4v.6h.3l.1-.2v-.4h-1.2l-.1 .4h-1.8l.1-.8zM149 144.1l4.3-.1 .3-.3v-1.2h.7l.4 .1 .4-.1-.4-.4-.4 .4h-.7v-.6h.3l.1 .3 .4-.3h.6l.3 .3 .2-.4-.2-.3-.3 .4h-.6l-.4-.4-.1 .4h-.3v-.7h.7l.4 .4 .4-.4-.4-.1-.4 .1h-.7v-1.7h1.9l.1 4.3 .4 .3h5.2l-.1 3.5h-12.1v-1.6l.2 .1h.7v-.7h.4l.1 .7h.6l.2-.1h7.2l.2 .1h.7v-.7h.4l.1 .7h.6l.2-.1-.1-.6h-2l-.1 .6h-7.2l-.1-.6h-2l-.1 .6v-1.5l.1 .6h.8v-.7h.4v.7h.8l.1-.6h7.2l.1 .6h.8v-.7h.4v.7h.8l.1-.6-.2-.2h-1.8l-.2 .2h-7.2l-.2-.2h-1.8l-.2 .2zM155.6 123.1h.5v1h-.5zM155.7 126.4l.6-.1 .2 .1 .1 .7-.1 .2-.7 .1-.1-.1z"/>
<path d="M155.7 124.6h.6l.2 .1 .1 .7-.1 .2h-.7l-.1-.1zM156.4 123.1h.5v1h-.5zM152.7 132.1h4.2l.1 .1v.8l.2 .2h5.6h.1v5.8l-.1 .1h-10.1l-.1-.1v-2.4h.6l.2 .2 .1-.2h1.3l.1 .2 .1-.2h-2.4v-1.7h.9v-.2h1.3v.2h.2l-.1-.2h-1.5l-.2 .2h-.6v-2.7zM157.2 123.1h.5v1h-.5zM157.2 124.6h.6l.2 .1 .1 .7-.1 .2h-.6l-.2-.1zM157.2 126.4l.6-.1 .2 .1 .1 .7-.1 .2-.6 .1-.2-.1zM158 123.1h.5v1h-.5zM157.6 129.7h.6h.2l.1 .8-.1 .2h-.6l-.2-.1zM157.6 131.5l.6-.1 .2 .1 .1 .7-.1 .2-.6 .1-.2-.1zM158.8 123.1h.5v1h-.5zM157.8 121.6l.3-.3h.9v.1a.6 .6 0 0 0 .1 .8 .6 .6 0 0 0 .8 0h.5a.56 .56 0 0 0-.3 .6h-1.3l-.4 .1v1.3l.4 .2h.7v.5l-.7 .6h-.5l-.1-.2h-1.2l-.1 .2v-.5l.1-.1h1.3l-.1-.5h-.5l.4-.2v-1.3l-.3-.1zM159.2 129.7h1.5v2.7h-1.5z"/>
<path d="M159.6 123.1h.5v1h-.5zM160.4 123.1h.5v1h-.5zM161.1 129.7h1.5v2.7h-1.5zM161.2 123.1h.5v1h-.5zM162 123.1h.5v1h-.5zM162.8 123.1h.5v1h-.5zM163.6 123.1h.5v1h-.5zM163.4 129.7h.7h.2v.8l-.1 .2h-.6l-.2-.1zM163.4 131.5l.7-.1 .2 .1v.7l-.1 .2-.6 .1-.2-.1zM164.4 123.1h.5v1h-.5zM163.8 124.6h.6l.2 .1 .1 .7-.1 .2h-.6l-.2-.1zM163.8 126.4l.6-.1 .2 .1 .1 .7-.1 .2-.6 .1-.2-.1z"/>
<path d="M164.6 133.6h1.7v1.7h-1.7zM165.2 123.1h.5v1h-.5zM156 139.5h9.7l.1 .1v4l-.1 .1h-9.7l-.1-.1v-.6h2.5l.2 .2h.7v-.7h.4l.1 .7h.6l.2-.2-.1-.5h-2l-.1 .5h-2.5v-.5h.5l.2 .1h.4v-.6h.4l.1 .6h.4l.1-.1v-.5h-1.5l-.1 .5h-.5v-1.2h.5l.1 .4h.5v-.6h.4v.6l1-.1 .1 .5h.8v-.7h.4v.7l.9-.1v-.5l-.2-.1h-1.8l-.2 .2h-.4v-.4l-.1-.1h-1.3l-.2 .2h-.5v-1.7zM166 123.1h.5v1h-.5zM166.8 123.1h.5v1h-.5zM165.9 131.6l.1-.1 1.1 .1 .1 .2-.1 .8-.2 .1-1-.1-.1-.2zM165.9 129.5h.1h1.1l.1 .2-.1 .8-.2 .1h-1l-.1-.2zM167.6 123.1h.5v1h-.5zM168.4 123.1h.5v1h-.5zM168 136h.6l.2 .1 .1 .7-.1 .2h-.6l-.2-.1zM168 134.3l.6-.1 .2 .1 .1 .7-.1 .2-.6 .1-.2-.1zM168.5 126.4l.6-.1 .2 .1 .1 .7-.1 .2-.6 .1-.2-.1z"/>
<path d="M168.5 124.6h.6l.2 .1 .1 .7-.1 .2h-.6l-.2-.1zM168.8 131.5l.6-.1 .2 .1v.7v.2l-.7 .1-.2-.1zM168.8 129.7h.6h.2v.8v.2h-.7l-.2-.1zM170.5 126.4l.7-.1 .2 .1v.7l-.1 .2-.6 .1-.2-.1zM170.5 124.6h.7l.2 .1v.7l-.1 .2h-.6l-.2-.1zM170.9 121.2l.7-.1 .1 .1 .1 .7-.1 .2-.6 .1-.2-.1zM175.7 135.3l.7-.1 .2 .1v.7l-.1 .2-.6 .1-.2-.1zM175.7 133.5h.7l.2 .1v.7l-.1 .2h-.6l-.2-.1zM175.7 129.2l.7-.1 .2 .1v.7l-.1 .2-.6 .1-.2-.1zM175.7 127.4h.7l.2 .1v.7l-.1 .2h-.6l-.2-.1zM184.2 120.4l1.1-.1 .2 .2v2.3l-.1 .2h-1.1l-.2-.2zM187.2 120.4l1.1-.1 .2 .2v2.2l-.1 .3h-1.1l-.2-.1v-2.3z"/>
<path d="M188.5 132.4h9.2l.1 .1v7.3l.1 .2h8.8l.1 .1v7.4l-.1 .1h-18.2l-.1-.1v-1.3h16.2a.81 .81 0 0 0 .8 0l-.4-.4-.4 .4h-16.2v-1.2h15.3l.1 .4 .4-.5h1.6l.4 .5a.81 .81 0 0 0 0-.9l-.4 .4h-1.6l-.4-.4-.1 .5h-15.3v-1.3h16.2l.4 .4 .4-.4a.81 .81 0 0 0-.8 0h-16.2v-1.9h6.4a1.68 1.68 0 0 0 2.3 1.8 1.68 1.68 0 0 0 .5-2.8 1.68 1.68 0 0 0-2.7 .7l-.1 .3h-6.4v-6.3h7.7a.73 .73 0 0 0 .8 0l-.4-.3-.4 .3h-7.7v-1.1h6.8l.1 .3 .4-.3h1.6l.4 .3a.73 .73 0 0 0 0-.7l-.4 .4h-1.6l-.4-.4-.1 .4h-6.8v-1.2h7.7l.4 .4 .4-.4a.73 .73 0 0 0-.8 0h-7.7v-.7zM203.1 123.5l.1-.1h7.9l.2 .1 1 1 .1 .2v7.3l.2 .1h5.3l.1 .1v5.1h-.1h-10.4v-1.2h1.5a.96 .96 0 0 0 1.1 0l-.6-.5-.5 .5h-1.5v-1.3h.7v.5l.1 .2 .6-.6h1.2l.6 .6a.96 .96 0 0 0 0-1.1l-.6 .5h-1.2l-.6-.5-.1 .4h-.7v-1h1.5l.5 .5 .6-.5a.96 .96 0 0 0-1.1 0h-1.5v-1.9l-.2-.1h-4.1l-.1-.1zM207.5 138h10.4l.1 .1v1.9l-.1 .1-6.7 .1-.2 .1v7.2l-.1 .1h-3.4v-.1v-1.3h1.6a.81 .81 0 0 0 .8 0l-.4-.4-.4 .4h-1.6v-1.2h.7l.1 .4 .4-.5h1.6l.4 .5a.81 .81 0 0 0 0-.9l-.4 .4h-1.6l-.4-.4-.1 .5h-.7v-1.3h1.6l.4 .4 .4-.4a.81 .81 0 0 0-.8 0h-1.6v-5.6zM218.7 135.9h10.5l.1 .1v5.2a4.1 4.1 0 0 0-5.5 .9 4.1 4.1 0 0 0 .4 5.5h-5.5l-.1-.1v-.3h1.1l.1 .2 .2-.1v-2h1.9v2l.3 .1 .1-.2v-1.9h-2.6v1.9h-1.1v-2.7l.1-.4-.1-.6v-1.9h1.1v1.8h.3v-1.9h1.9v1.9h.4v-1.8l-.2-.2h-2.3l-.1 .2h-1.1v-1.1l.9 .1 .2-.1h4.6l.3 .1 .2-.1-.3-.3-.2 .3h-4.6l-.2-.3-.3 .3h-.6v-.7l.2-.2h1.3l.2 .3 .1-.2h3.2l.1 .2 .2-.3h1.3l.2 .3 .1-.4-.1-.1-.2 .2h-1.3l-.2-.2-.1 .3h-3.2l-.1-.3-.2 .2h-1.3l-.2-.2v-.6h.6l.3 .2 .2-.2h4.6l.2 .2 .3-.2-.3-.1-.2 .1h-4.6l-.3-.1-.8 .1v-.9l.9 .1 .2-.1h4.6l.3 .1 .2-.1-.3-.2-.2 .2h-4.6l-.2-.2-.3 .2h-.6v-.6l.2-.2h1.3l.2 .2 .1-.2h3.2l.1 .2 .2-.2h1.3l.2 .2 .1-.4-.1-.1-.2 .3h-1.3l-.2-.3-.1 .3h-3.2l-.1-.3-.2 .3h-1.3l-.2-.2v-.7h.6l.3 .2 .2-.2h4.6l.2 .2 .3-.2-.3-.1-.2 .1h-4.6l-.3-.1-.8 .1zM74 143.1h.9l.1 .2-.1 .6-.2 .1-.7-.1-.1-.2zM75.7 143.1h.9l.1 .2v.6l-.2 .1-.7-.1-.1-.2zM80.5 140.9v-.1h4.6l.1 .1v6.6l-.1 .1h-4.6v-.1zM87.2 142.8h2.1v1.4h-2.1zM94.7 145.7l.7-.1 .1 .1 .1 .7-.1 .2-.6 .1-.2-.1zM94.7 144l.7-.1 .1 .1 .1 .7-.1 .2h-.6l-.2-.1zM97.1 144l.7-.1 .2 .1v.7l-.1 .2h-.6l-.2-.1zM97.1 145.7l.7-.1 .2 .1v.7l-.1 .2-.6 .1-.2-.1z"/>
<path d="M104.1 145.7l.7-.1 .1 .1 .1 .7-.1 .2-.6 .1-.2-.1zM104.1 144l.7-.1 .1 .1 .1 .7-.1 .2h-.6l-.2-.1zM113.9 140.1l.6-.1 .2 .1 .1 .8-.1 .1-.6 .1-.2-.1zM114.4 142.3h.9v.2v.6l-.2 .1h-.7l-.1-.2zM115.4 140.1l.7-.1 .1 .1 .1 .8-.1 .1-.6 .1-.2-.1zM116.1 142.3h.9l.1 .2-.1 .6-.1 .1h-.8l-.1-.2zM128.2 144.6l.2-.1 1.4 .1 .1 .2v1.1l-.2 .1-1.5-.1v-.2zM128.2 141.6h.2h1.4l.1 .2v1.1l-.2 .1-1.5-.1v-.2zM135.5 141.3h1.2v1.2h-1.2zM139.5 144.6l.2-.1 1.4 .1 .1 .2v1.1l-.2 .1-1.4-.1-.1-.2zM139.5 141.6h.2h1.4l.1 .2v1.1l-.2 .1-1.4-.1-.1-.2zM146 141.6h.2h1.4l.1 .2-.1 1.1-.2 .1-1.4-.1-.1-.2z"/>
<path d="M146 144.6l.2-.1 1.4 .1 .1 .2-.1 1.1-.2 .1-1.4-.1-.1-.2zM141.9 144.1h6.7l.1 .1v3.3l-.1 .1h-6.7l-.1-.1v-1.5h3.9l.2 .1h.7v-.7h.4l.1 .7h.6l.2-.1-.1-.6h-2l-.1 .6h-3.9v-1.5h3.9l.1 .6h.8v-.7h.4v.7l.9-.1v-.5l-.2-.2h-1.8l-.2 .2h-3.9v-.3zM149.3 144.6l.2-.1 1.4 .1 .1 .2-.1 1.1-.2 .1-1.4-.1-.1-.2zM149.3 141.6h.2h1.4l.1 .2-.1 1.1-.2 .1-1.4-.1-.1-.2zM156.6 141.3h1.2v1.2h-1.2zM158.7 144.6l.2-.1 1.4 .1 .1 .2-.1 1.1-.2 .1-1.4-.1-.1-.2zM158.7 141.6h.2h1.4l.1 .2-.1 1.1-.2 .1-1.4-.1-.1-.2zM166.8 141.6h.2h1.4l.1 .2v1.1l-.2 .1-1.4-.1-.1-.2zM166.8 144.6l.2-.1 1.4 .1 .1 .2v1.1l-.2 .1-1.4-.1-.1-.2zM161.6 144.2h8.6v.1v3.2v.1h-8.6l-.1-.1v-1.5h5.1l.1 .1h.7v-.7h.4l.1 .7h.7l.1-.1v-.6h-2.1v.6h-5.1v-1.5h5.1v.6h.8v-.7h.4v.7l.9-.1v-.5l-.1-.2h-1.8l-.2 .2h-5.1zM184.2 140.7h1.1l.2 .1v2.3l-.1 .2h-1.1l-.2-.1v-2.3zM187.2 140.7h1.1l.2 .1v2.3l-.1 .2h-1.1l-.2-.1v-2.3z"/>
<path d="M212.4 141.6h2.3v5.6h-2.3zM211.7 140.8h4.7l.1 .1v6.6l-.1 .1h-4.7l-.1-.1v-.3h.7l.1 .2 .2-.1v-2h1.9v2l.3 .1 .1-.2v-1.9h-2.6v1.9h-.7v-5.6h.7v1.8h.3v-1.9h1.9v1.9h.4v-1.9l-2.5-.1-.1 .2h-.7v-.7zM219.8 141.6h2.3v5.6h-2.3z"/>
<circle cx="72.1" cy="55" r=".25"/>
<circle cx="73.3" cy="53.8" r=".25"/>
<circle cx="75.4" cy="56.6" r=".25"/>
<circle cx="79.1" cy="59.4" r=".25"/>
<circle cx="79.1" cy="53.8" r=".25"/>
<circle cx="82" cy="56" r=".25"/>
<circle cx="84.1" cy="59.7" r=".25"/>
<circle cx="84.2" cy="57.1" r=".25"/>
<circle cx="85.1" cy="53.8" r=".25"/>
<circle cx="87.4" cy="57.1" r=".25"/>
<circle cx="89" cy="57.1" r=".25"/>
<circle cx="91.1" cy="59.7" r=".25"/>
<circle cx="91.1" cy="53.8" r=".25"/>
<circle cx="91.6" cy="57.9" r=".25"/>
<circle cx="97.1" cy="53.8" r=".25"/>
<circle cx="100.8" cy="57" r=".25"/>
<circle cx="103.1" cy="53.8" r=".25"/>
<circle cx="103.1" cy="57.8" r=".25"/>
<circle cx="106.7" cy="59" r=".25"/>
<circle cx="109.1" cy="53.8" r=".25"/>
<circle cx="110" cy="57.8" r=".25"/>
<circle cx="111.8" cy="57.8" r=".25"/>
<circle cx="113.8" cy="59" r=".25"/>
<circle cx="114.9" cy="53.8" r=".25"/>
<circle cx="116" cy="55" r=".25"/>
<circle cx="121.7" cy="55" r=".5"/>
<circle cx="157.7" cy="57" r=".5"/>
<circle cx="162.8" cy="56.9" r=".5"/>
<circle cx="178.8" cy="53.8" r=".5"/>
<circle cx="181.9" cy="59.4" r=".75"/>
<circle cx="196.3" cy="59.4" r=".75"/>
<circle cx="205" cy="56.3" r="1"/>
<circle cx="210.1" cy="56.3" r="1"/>
<circle cx="215.1" cy="56.3" r="1"/>
<circle cx="227.1" cy="55.8" r="2.05"/>
<circle cx="72" cy="66.8" r=".25"/>
<circle cx="72" cy="78.8" r=".25"/>
<circle cx="72" cy="72.8" r=".25"/>
<circle cx="72.1" cy="60.8" r=".25"/>
<circle cx="74.7" cy="61.3" r=".6"/>
<circle cx="75.9" cy="60.2" r=".25"/>
<circle cx="76.3" cy="69.7" r=".25"/>
<circle cx="76.5" cy="64.6" r=".25"/>
<circle cx="76.6" cy="79.8" r=".25"/>
<circle cx="76.6" cy="79.2" r=".25"/>
<circle cx="77.2" cy="71.9" r=".25"/>
<circle cx="77.3" cy="61.3" r=".6"/>
<circle cx="78.4" cy="69.3" r=".25"/>
<circle cx="79" cy="74.3" r=".25"/>
<circle cx="79.1" cy="71.9" r=".25"/>
<circle cx="79.8" cy="65" r=".25"/>
<circle cx="79.8" cy="61.3" r=".6"/>
<circle cx="80.1" cy="69.3" r=".25"/>
<circle cx="80.8" cy="79.1" r=".25"/>
<circle cx="81.3" cy="77.1" r=".25"/>
<circle cx="84.2" cy="69.6" r=".25"/>
<circle cx="84.6" cy="65.1" r=".25"/>
<circle cx="84.7" cy="77.6" r=".25"/>
<circle cx="85.6" cy="76.2" r=".25"/>
<circle cx="85.7" cy="72.9" r=".25"/>
<circle cx="86" cy="74.3" r=".25"/>
<circle cx="86.1" cy="61" r=".25"/>
<circle cx="86.1" cy="70.9" r=".25"/>
<circle cx="86.2" cy="68.3" r=".25"/>
<circle cx="86.4" cy="73.3" r=".25"/>
<circle cx="87" cy="77" r=".25"/>
<circle cx="87.4" cy="63" r=".25"/>
<circle cx="88.5" cy="70.2" r=".25"/>
<circle cx="89" cy="74.5" r=".25"/>
<circle cx="89" cy="67.1" r=".25"/>
<circle cx="89.2" cy="61" r=".25"/>
<circle cx="89.5" cy="72.8" r=".25"/>
<circle cx="89.8" cy="65.5" r=".25"/>
<circle cx="89.8" cy="73.7" r=".25"/>
<circle cx="90.8" cy="63.7" r=".25"/>
<circle cx="91.1" cy="70.9" r=".25"/>
<circle cx="91.8" cy="67.4" r=".25"/>
<circle cx="93.3" cy="77.3" r=".25"/>
<circle cx="93.9" cy="61" r=".25"/>
<circle cx="95.3" cy="69.1" r=".25"/>
<circle cx="95.8" cy="61.1" r=".25"/>
<circle cx="95.9" cy="66" r=".25"/>
<circle cx="97.5" cy="67.2" r=".25"/>
<circle cx="97.9" cy="75.8" r=".25"/>
<circle cx="98.3" cy="63.5" r=".25"/>
<circle cx="98.3" cy="73.3" r=".25"/>
<circle cx="99.3" cy="78.6" r=".25"/>
<circle cx="100.2" cy="60.3" r=".25"/>
<circle cx="100.2" cy="66" r=".25"/>
<circle cx="100.3" cy="74.5" r=".25"/>
<circle cx="100.8" cy="79.7" r=".25"/>
<circle cx="101.5" cy="63.5" r=".25"/>
<circle cx="101.5" cy="73.3" r=".25"/>
<circle cx="101.7" cy="70.6" r=".25"/>
<circle cx="101.9" cy="68.6" r=".25"/>
<circle cx="102" cy="60.3" r=".25"/>
<circle cx="102" cy="65.8" r=".25"/>
<circle cx="102.2" cy="76.1" r=".25"/>
<circle cx="103.1" cy="73.3" r=".25"/>
<circle cx="103.3" cy="79" r=".25"/>
<circle cx="103.3" cy="63.5" r=".25"/>
<circle cx="105.9" cy="69.1" r=".25"/>
<circle cx="107.8" cy="66.3" r=".7"/>
<circle cx="108.4" cy="67.8" r=".7"/>
<circle cx="108.7" cy="60.3" r=".25"/>
<circle cx="109.9" cy="68.4" r=".7"/>
<circle cx="109.9" cy="64.2" r=".7"/>
<circle cx="110.6" cy="60.3" r=".25"/>
<circle cx="111.3" cy="64.8" r=".7"/>
<circle cx="112" cy="66.3" r=".7"/>
<circle cx="112.6" cy="60.8" r=".25"/>
<circle cx="116" cy="66.8" r=".25"/>
<circle cx="116" cy="72.8" r=".25"/>
<circle cx="116" cy="78.8" r=".25"/>
<circle cx="116.1" cy="60.8" r=".25"/>
<circle cx="118" cy="65.8" r=".25"/>
<circle cx="118" cy="68.3" r=".25"/>
<circle cx="118.1" cy="74.3" r=".25"/>
<circle cx="118.1" cy="76.6" r=".25"/>
<circle cx="120.3" cy="74.3" r=".25"/>
<circle cx="120.8" cy="64.6" r=".25"/>
<circle cx="121.9" cy="65.8" r=".25"/>
<circle cx="121.9" cy="74.2" r=".25"/>
<circle cx="123.2" cy="74.3" r=".25"/>
<circle cx="123.3" cy="65.8" r=".25"/>
<circle cx="123.8" cy="77.6" r=".25"/>
<circle cx="125.2" cy="65.8" r=".25"/>
<circle cx="125.3" cy="74.3" r=".25"/>
<circle cx="126.2" cy="77.6" r=".25"/>
<circle cx="127" cy="65.8" r=".25"/>
<circle cx="127" cy="74.2" r=".25"/>
<circle cx="128.9" cy="74.3" r=".25"/>
<circle cx="129.4" cy="69" r=".25"/>
<circle cx="130.2" cy="76.7" r=".25"/>
<circle cx="130.9" cy="74.3" r=".25"/>
<circle cx="132.6" cy="74.2" r=".25"/>
<circle cx="132.8" cy="78.9" r=".25"/>
<circle cx="133.9" cy="74.3" r=".25"/>
<circle cx="134.1" cy="61.8" r=".5"/>
<circle cx="135.4" cy="68.3" r=".5"/>
<circle cx="136.1" cy="74.3" r=".25"/>
<circle cx="137.8" cy="74.3" r=".25"/>
<circle cx="140.6" cy="68.3" r=".5"/>
<circle cx="145.7" cy="76.6" r=".5"/>
<circle cx="145.7" cy="67.7" r=".5"/>
<circle cx="150.7" cy="71.7" r=".5"/>
<circle cx="153.3" cy="71.6" r=".25"/>
<circle cx="153.3" cy="77.3" r=".25"/>
<circle cx="157" cy="72.3" r=".5"/>
<circle cx="159.1" cy="76.8" r=".5"/>
<circle cx="165.4" cy="62.1" r=".5"/>
<circle cx="165.4" cy="60" r=".5"/>
<circle cx="167.3" cy="76.4" r=".5"/>
<circle cx="172.3" cy="75.7" r=".5"/>
<circle cx="172.8" cy="62" r=".5"/>
<circle cx="174.9" cy="71.5" r=".5"/>
<circle cx="174.9" cy="76.8" r=".5"/>
<circle cx="178.8" cy="61.1" r=".5"/>
<circle cx="179.2" cy="75.4" r=".25"/>
<circle cx="181.5" cy="69.8" r=".5"/>
<circle cx="181.7" cy="75.3" r=".5"/>
<circle cx="183.3" cy="78.4" r=".25"/>
<circle cx="184" cy="75.9" r=".25"/>
<circle cx="186.2" cy="61" r=".5"/>
<circle cx="189.2" cy="66.5" r=".5"/>
<circle cx="190.4" cy="75.3" r=".5"/>
<circle cx="193.3" cy="75.4" r=".5"/>
<circle cx="205" cy="66.7" r="1"/>
<circle cx="205" cy="61.5" r="1"/>
<circle cx="205" cy="77.1" r="1"/>
<circle cx="205" cy="71.9" r="1"/>
<circle cx="210.1" cy="66.7" r="1"/>
<circle cx="210.1" cy="61.5" r="1"/>
<circle cx="210.1" cy="77.1" r="1"/>
<circle cx="210.1" cy="71.9" r="1"/>
<circle cx="215.1" cy="71.9" r="1"/>
<circle cx="215.1" cy="77.1" r="1"/>
<circle cx="215.1" cy="66.7" r="1"/>
<circle cx="215.1" cy="61.5" r="1"/>
<circle cx="219.5" cy="78.7" r=".75"/>
<circle cx="219.5" cy="68.5" r=".75"/>
<circle cx="219.5" cy="66" r=".75"/>
<circle cx="219.5" cy="71" r=".75"/>
<circle cx="219.5" cy="60.9" r=".75"/>
<circle cx="219.5" cy="63.4" r=".75"/>
<circle cx="219.5" cy="73.6" r=".75"/>
<circle cx="219.5" cy="76.1" r=".75"/>
<circle cx="224.5" cy="68.5" r=".75"/>
<circle cx="224.5" cy="66" r=".75"/>
<circle cx="224.5" cy="73.6" r=".75"/>
<circle cx="224.5" cy="71" r=".75"/>
<circle cx="224.5" cy="78.7" r=".75"/>
<circle cx="224.5" cy="63.4" r=".75"/>
<circle cx="224.5" cy="76.1" r=".75"/>
<circle cx="224.5" cy="60.9" r=".75"/>
<circle cx="72" cy="84.8" r=".25"/>
<circle cx="72" cy="90.8" r=".25"/>
<circle cx="72.1" cy="96.8" r=".25"/>
<circle cx="73.3" cy="98" r=".25"/>
<circle cx="75.7" cy="87.7" r=".25"/>
<circle cx="75.7" cy="91.6" r=".25"/>
<circle cx="77.2" cy="80.5" r=".25"/>
<circle cx="77.3" cy="90.8" r=".25"/>
<circle cx="77.3" cy="87.1" r=".25"/>
<circle cx="77.3" cy="94.5" r=".25"/>
<circle cx="77.3" cy="93.2" r=".25"/>
<circle cx="77.3" cy="89.5" r=".25"/>
<circle cx="77.3" cy="85.8" r=".25"/>
<circle cx="78.4" cy="90.8" r=".25"/>
<circle cx="78.4" cy="87.1" r=".25"/>
<circle cx="78.4" cy="94.5" r=".25"/>
<circle cx="78.4" cy="89.5" r=".25"/>
<circle cx="78.4" cy="93.2" r=".25"/>
<circle cx="78.4" cy="85.8" r=".25"/>
<circle cx="79.1" cy="98" r=".25"/>
<circle cx="79.1" cy="87.5" r=".25"/>
<circle cx="79.4" cy="80.1" r=".25"/>
<circle cx="80.4" cy="80.3" r=".25"/>
<circle cx="80.9" cy="94.2" r=".25"/>
<circle cx="80.9" cy="86.9" r=".25"/>
<circle cx="84.3" cy="95.1" r=".25"/>
<circle cx="84.3" cy="89.4" r=".25"/>
<circle cx="85.1" cy="98" r=".25"/>
<circle cx="85.6" cy="85.6" r=".25"/>
<circle cx="86.1" cy="81.8" r=".25"/>
<circle cx="86.1" cy="95.1" r=".25"/>
<circle cx="86.1" cy="83.1" r=".25"/>
<circle cx="87.2" cy="92.6" r=".25"/>
<circle cx="87.4" cy="89.4" r=".25"/>
<circle cx="87.4" cy="85.6" r=".25"/>
<circle cx="87.4" cy="80.3" r=".25"/>
<circle cx="87.9" cy="83.1" r=".25"/>
<circle cx="89.2" cy="80.3" r=".25"/>
<circle cx="91.1" cy="81.8" r=".25"/>
<circle cx="91.1" cy="98" r=".25"/>
<circle cx="91.6" cy="90.2" r=".25"/>
<circle cx="91.6" cy="82.6" r=".25"/>
<circle cx="92.7" cy="88.4" r=".25"/>
<circle cx="92.7" cy="85.3" r=".25"/>
<circle cx="92.8" cy="89.5" r=".25"/>
<circle cx="93" cy="93.8" r=".25"/>
<circle cx="93" cy="86.6" r=".25"/>
<circle cx="93" cy="95.1" r=".25"/>
<circle cx="93.9" cy="87.6" r=".25"/>
<circle cx="94.7" cy="95.1" r=".25"/>
<circle cx="95.5" cy="89.5" r=".25"/>
<circle cx="95.6" cy="88.1" r=".25"/>
<circle cx="95.8" cy="85.7" r=".25"/>
<circle cx="95.9" cy="93.8" r=".25"/>
<circle cx="96" cy="92.6" r=".25"/>
<circle cx="96.1" cy="87.1" r=".25"/>
<circle cx="96.6" cy="82.9" r=".25"/>
<circle cx="97.1" cy="98" r=".25"/>
<circle cx="97.5" cy="90.2" r=".25"/>
<circle cx="98" cy="95.1" r=".25"/>
<circle cx="98.3" cy="85.7" r=".25"/>
<circle cx="98.6" cy="92.5" r=".25"/>
<circle cx="99.1" cy="82.8" r=".25"/>
<circle cx="100.2" cy="81.5" r=".25"/>
<circle cx="100.2" cy="93" r=".25"/>
<circle cx="100.6" cy="87.6" r=".25"/>
<circle cx="101" cy="89.9" r=".25"/>
<circle cx="101.2" cy="95" r=".25"/>
<circle cx="101.5" cy="82.9" r=".25"/>
<circle cx="102" cy="81.5" r=".25"/>
<circle cx="102.2" cy="92.2" r=".25"/>
<circle cx="102.9" cy="85.5" r=".25"/>
<circle cx="103.1" cy="98" r=".25"/>
<circle cx="103.3" cy="80.3" r=".25"/>
<circle cx="103.5" cy="90.8" r=".25"/>
<circle cx="104" cy="86.4" r=".25"/>
<circle cx="105.3" cy="91.9" r=".25"/>
<circle cx="105.3" cy="90.7" r=".25"/>
<circle cx="106.2" cy="87.4" r=".25"/>
<circle cx="107.7" cy="96.1" r=".25"/>
<circle cx="107.7" cy="92.2" r=".25"/>
<circle cx="107.8" cy="86.2" r=".25"/>
<circle cx="109.1" cy="98" r=".25"/>
<circle cx="109.3" cy="95.9" r=".25"/>
<circle cx="109.7" cy="92.1" r=".25"/>
<circle cx="111" cy="88.6" r=".25"/>
<circle cx="111.6" cy="90.2" r=".25"/>
<circle cx="114.8" cy="98" r=".25"/>
<circle cx="116" cy="90.8" r=".25"/>
<circle cx="116.1" cy="86" r=".25"/>
<circle cx="116.1" cy="96.8" r=".25"/>
<circle cx="117.9" cy="86.5" r=".25"/>
<circle cx="118" cy="98.7" r=".25"/>
<circle cx="118.1" cy="82.7" r=".25"/>
<circle cx="118.9" cy="96.1" r=".25"/>
<circle cx="119.6" cy="91.9" r=".25"/>
<circle cx="119.8" cy="97.8" r=".25"/>
<circle cx="120.4" cy="82.2" r=".25"/>
<circle cx="121.2" cy="86.5" r=".25"/>
<circle cx="121.5" cy="91.9" r=".25"/>
<circle cx="121.7" cy="81.3" r=".25"/>
<circle cx="122.7" cy="95.2" r=".25"/>
<circle cx="122.8" cy="86.5" r=".25"/>
<circle cx="123.2" cy="82.7" r=".25"/>
<circle cx="124.2" cy="91.1" r=".25"/>
<circle cx="127" cy="82.5" r=".25"/>
<circle cx="127.1" cy="92.2" r=".25"/>
<circle cx="127.1" cy="85.8" r=".25"/>
<circle cx="127.1" cy="96.3" r=".25"/>
<circle cx="128.8" cy="82.6" r=".25"/>
<circle cx="128.9" cy="92" r=".25"/>
<circle cx="129.4" cy="98.5" r=".25"/>
<circle cx="129.5" cy="90.7" r=".25"/>
<circle cx="130" cy="93" r=".25"/>
<circle cx="130" cy="97.1" r=".25"/>
<circle cx="130.6" cy="98.5" r=".25"/>
<circle cx="130.8" cy="82.5" r=".25"/>
<circle cx="131" cy="93" r=".25"/>
<circle cx="131.3" cy="91.2" r=".25"/>
<circle cx="131.4" cy="98.6" r=".25"/>
<circle cx="132.3" cy="86.5" r=".25"/>
<circle cx="132.6" cy="82.6" r=".25"/>
<circle cx="132.6" cy="95.6" r=".25"/>
<circle cx="133.7" cy="85.3" r=".25"/>
<circle cx="133.9" cy="82.7" r=".25"/>
<circle cx="135.3" cy="91.3" r=".25"/>
<circle cx="137.5" cy="82.7" r=".25"/>
<circle cx="139.1" cy="87.6" r=".25"/>
<circle cx="139.7" cy="91.6" r=".25"/>
<circle cx="140.1" cy="98.2" r=".25"/>
<circle cx="140.1" cy="99.4" r=".25"/>
<circle cx="140.5" cy="96" r=".25"/>
<circle cx="144.5" cy="87.4" r=".25"/>
<circle cx="144.5" cy="93" r=".25"/>
<circle cx="144.7" cy="99" r=".25"/>
<circle cx="145.9" cy="97" r=".25"/>
<circle cx="148.8" cy="97.6" r=".25"/>
<circle cx="148.8" cy="96.9" r=".25"/>
<circle cx="148.8" cy="96.3" r=".25"/>
<circle cx="150.2" cy="92" r=".25"/>
<circle cx="150.6" cy="91.1" r=".25"/>
<circle cx="150.6" cy="98.2" r=".25"/>
<circle cx="150.7" cy="94.4" r=".25"/>
<circle cx="154.2" cy="94.7" r=".25"/>
<circle cx="154.6" cy="98.2" r=".25"/>
<circle cx="154.7" cy="91.1" r=".25"/>
<circle cx="154.8" cy="97.5" r=".25"/>
<circle cx="154.8" cy="96.9" r=".25"/>
<circle cx="154.8" cy="96.3" r=".25"/>
<circle cx="155.6" cy="90.9" r=".25"/>
<circle cx="155.6" cy="92.6" r=".25"/>
<circle cx="160.7" cy="95.9" r=".25"/>
<circle cx="160.7" cy="90.7" r=".25"/>
<circle cx="160.7" cy="98.5" r=".25"/>
<circle cx="160.8" cy="97.1" r=".25"/>
<circle cx="161" cy="91.9" r=".25"/>
<circle cx="161.1" cy="99.2" r=".25"/>
<circle cx="161.1" cy="93.1" r=".25"/>
<circle cx="161.2" cy="96.4" r=".25"/>
<circle cx="161.4" cy="91.3" r=".25"/>
<circle cx="161.5" cy="90" r=".25"/>
<circle cx="161.7" cy="98.6" r=".25"/>
<circle cx="162.2" cy="89.4" r=".25"/>
<circle cx="163.8" cy="98.4" r=".25"/>
<circle cx="167.7" cy="93.7" r=".25"/>
<circle cx="168.3" cy="91.3" r=".25"/>
<circle cx="168.3" cy="89.3" r=".25"/>
<circle cx="168.3" cy="90" r=".25"/>
<circle cx="168.4" cy="95.9" r=".25"/>
<circle cx="168.4" cy="97.8" r=".25"/>
<circle cx="174" cy="96.9" r=".25"/>
<circle cx="174" cy="92.8" r=".25"/>
<circle cx="175.9" cy="81.8" r=".5"/>
<circle cx="178" cy="92.6" r=".25"/>
<circle cx="178.7" cy="82.8" r=".5"/>
<circle cx="182.5" cy="90.4" r=".25"/>
<circle cx="182.5" cy="89.1" r=".25"/>
<circle cx="182.6" cy="98" r=".25"/>
<circle cx="188.8" cy="90.4" r=".25"/>
<circle cx="189" cy="89.1" r=".25"/>
<circle cx="189.2" cy="96.8" r=".25"/>
<circle cx="189.2" cy="98" r=".25"/>
<circle cx="194.9" cy="90.9" r=".25"/>
<circle cx="195.3" cy="97.1" r=".25"/>
<circle cx="198.9" cy="90.3" r=".25"/>
<circle cx="198.9" cy="92.2" r=".25"/>
<circle cx="198.9" cy="94.1" r=".25"/>
<circle cx="202.6" cy="97.8" r=".25"/>
<circle cx="204.9" cy="91.7" r=".25"/>
<circle cx="205.6" cy="85.2" r=".25"/>
<circle cx="205.7" cy="83.9" r=".25"/>
<circle cx="205.7" cy="83.3" r=".25"/>
<circle cx="205.7" cy="81.9" r=".25"/>
<circle cx="205.7" cy="81.3" r=".25"/>
<circle cx="205.7" cy="82.6" r=".25"/>
<circle cx="206.1" cy="91.7" r=".25"/>
<circle cx="209.4" cy="85.2" r=".25"/>
<circle cx="210.8" cy="90.2" r=".25"/>
<circle cx="219.5" cy="93.9" r=".75"/>
<circle cx="219.5" cy="81.2" r=".75"/>
<circle cx="219.5" cy="83.7" r=".75"/>
<circle cx="219.5" cy="91.4" r=".75"/>
<circle cx="219.5" cy="88.8" r=".75"/>
<circle cx="219.5" cy="99" r=".75"/>
<circle cx="219.5" cy="96.4" r=".75"/>
<circle cx="219.5" cy="86.3" r=".75"/>
<circle cx="224.5" cy="88.8" r=".75"/>
<circle cx="224.5" cy="93.9" r=".75"/>
<circle cx="224.5" cy="99" r=".75"/>
<circle cx="224.5" cy="86.3" r=".75"/>
<circle cx="224.5" cy="96.4" r=".75"/>
<circle cx="224.5" cy="81.2" r=".75"/>
<circle cx="224.5" cy="83.7" r=".75"/>
<circle cx="224.5" cy="91.4" r=".75"/>
<circle cx="78.1" cy="115.8" r=".5"/>
<circle cx="78.1" cy="118.4" r=".5"/>
<circle cx="80.5" cy="118.4" r=".5"/>
<circle cx="80.5" cy="115.8" r=".5"/>
<circle cx="83.1" cy="118.4" r=".5"/>
<circle cx="83.1" cy="115.8" r=".5"/>
<circle cx="83.4" cy="102.4" r=".25"/>
<circle cx="98.4" cy="118.4" r=".5"/>
<circle cx="98.4" cy="115.8" r=".5"/>
<circle cx="101" cy="118.4" r=".5"/>
<circle cx="101" cy="115.7" r=".5"/>
<circle cx="103.5" cy="118.4" r=".5"/>
<circle cx="103.5" cy="115.7" r=".5"/>
<circle cx="112.5" cy="109.2" r=".25"/>
<circle cx="113.8" cy="114.8" r=".25"/>
<circle cx="114" cy="111.1" r=".25"/>
<circle cx="114" cy="109.7" r=".25"/>
<circle cx="114" cy="110.5" r=".25"/>
<circle cx="114" cy="109" r=".25"/>
<circle cx="114" cy="111.8" r=".25"/>
<circle cx="114.9" cy="113.7" r=".25"/>
<circle cx="115.5" cy="105.5" r=".25"/>
<circle cx="115.6" cy="107.4" r=".25"/>
<circle cx="116" cy="106.7" r=".25"/>
<circle cx="116.8" cy="104.6" r=".25"/>
<circle cx="117.1" cy="113.7" r=".25"/>
<circle cx="117.5" cy="107.8" r=".25"/>
<circle cx="117.6" cy="104.8" r=".25"/>
<circle cx="117.7" cy="100.5" r=".25"/>
<circle cx="118" cy="103.8" r=".25"/>
<circle cx="118.1" cy="114.8" r=".25"/>
<circle cx="119.5" cy="106.5" r=".25"/>
<circle cx="120.2" cy="111.2" r=".25"/>
<circle cx="120.3" cy="109.2" r=".25"/>
<circle cx="120.3" cy="110.2" r=".25"/>
<circle cx="120.3" cy="112.2" r=".25"/>
<circle cx="120.5" cy="100.5" r=".25"/>
<circle cx="120.9" cy="107.8" r=".25"/>
<circle cx="121.4" cy="106.4" r=".25"/>
<circle cx="121.5" cy="105.4" r=".25"/>
<circle cx="122.6" cy="112" r=".25"/>
<circle cx="124.5" cy="117.1" r=".25"/>
<circle cx="128.1" cy="118.4" r=".25"/>
<circle cx="128.3" cy="115.6" r=".25"/>
<circle cx="129" cy="118.4" r=".25"/>
<circle cx="129.5" cy="108.6" r=".25"/>
<circle cx="130.7" cy="108.5" r=".25"/>
<circle cx="131.6" cy="104.8" r=".25"/>
<circle cx="131.8" cy="112.4" r=".25"/>
<circle cx="131.8" cy="101.5" r=".25"/>
<circle cx="132.3" cy="104.8" r=".25"/>
<circle cx="133.7" cy="108.6" r=".25"/>
<circle cx="134.2" cy="118.7" r=".25"/>
<circle cx="137" cy="119.9" r=".25"/>
<circle cx="137" cy="118.1" r=".25"/>
<circle cx="139.7" cy="108.3" r=".25"/>
<circle cx="140.2" cy="116.9" r=".25"/>
<circle cx="141.5" cy="119.2" r=".25"/>
<circle cx="141.5" cy="113.2" r=".25"/>
<circle cx="142.5" cy="108.6" r=".25"/>
<circle cx="144.5" cy="108.6" r=".25"/>
<circle cx="145.4" cy="102.9" r=".25"/>
<circle cx="146.2" cy="109.2" r=".25"/>
<circle cx="146.3" cy="110.9" r=".25"/>
<circle cx="146.4" cy="115.2" r=".25"/>
<circle cx="146.4" cy="110.2" r=".25"/>
<circle cx="148.7" cy="117.7" r=".25"/>
<circle cx="148.7" cy="118.7" r=".25"/>
<circle cx="148.9" cy="102.2" r=".25"/>
<circle cx="148.9" cy="103.6" r=".25"/>
<circle cx="149" cy="114.7" r=".25"/>
<circle cx="149.1" cy="119.2" r=".25"/>
<circle cx="149.5" cy="108.5" r=".25"/>
<circle cx="150.4" cy="113.5" r=".25"/>
<circle cx="150.5" cy="102.9" r=".25"/>
<circle cx="150.5" cy="111" r=".25"/>
<circle cx="150.5" cy="110.2" r=".25"/>
<circle cx="150.7" cy="104.1" r=".25"/>
<circle cx="150.7" cy="108.5" r=".25"/>
<circle cx="150.7" cy="100.2" r=".25"/>
<circle cx="151" cy="106.3" r=".25"/>
<circle cx="151.1" cy="113.5" r=".25"/>
<circle cx="151.4" cy="114.5" r=".25"/>
<circle cx="151.5" cy="101.7" r=".25"/>
<circle cx="152" cy="114.4" r=".25"/>
<circle cx="152.5" cy="115.1" r=".25"/>
<circle cx="152.9" cy="114.4" r=".25"/>
<circle cx="153" cy="105.8" r=".25"/>
<circle cx="153.4" cy="113" r=".25"/>
<circle cx="153.5" cy="106.2" r=".25"/>
<circle cx="153.8" cy="101.7" r=".25"/>
<circle cx="153.9" cy="105.8" r=".25"/>
<circle cx="153.9" cy="114.4" r=".25"/>
<circle cx="154.2" cy="113.3" r=".25"/>
<circle cx="154.3" cy="119.1" r=".25"/>
<circle cx="154.4" cy="106.3" r=".25"/>
<circle cx="154.6" cy="108.6" r=".25"/>
<circle cx="154.6" cy="104.1" r=".25"/>
<circle cx="155" cy="106" r=".25"/>
<circle cx="155.1" cy="114.4" r=".25"/>
<circle cx="155.1" cy="113" r=".25"/>
<circle cx="155.6" cy="106.3" r=".25"/>
<circle cx="155.8" cy="113" r=".25"/>
<circle cx="156" cy="108.5" r=".25"/>
<circle cx="156.6" cy="111.8" r=".25"/>
<circle cx="156.6" cy="113.8" r=".25"/>
<circle cx="157.1" cy="108.3" r=".25"/>
<circle cx="157.2" cy="105.7" r=".25"/>
<circle cx="157.2" cy="113.8" r=".25"/>
<circle cx="157.4" cy="118.2" r=".25"/>
<circle cx="157.5" cy="113.1" r=".25"/>
<circle cx="157.9" cy="105.7" r=".25"/>
<circle cx="158.2" cy="113.3" r=".25"/>
<circle cx="158.4" cy="119.4" r=".25"/>
<circle cx="158.5" cy="106.3" r=".25"/>
<circle cx="158.5" cy="108.6" r=".25"/>
<circle cx="158.5" cy="118.8" r=".25"/>
<circle cx="158.7" cy="116.1" r=".25"/>
<circle cx="159" cy="108.2" r=".25"/>
<circle cx="159.1" cy="119.5" r=".25"/>
<circle cx="159.3" cy="105.7" r=".25"/>
<circle cx="159.9" cy="105.7" r=".25"/>
<circle cx="160.4" cy="109.6" r=".25"/>
<circle cx="160.4" cy="108.8" r=".25"/>
<circle cx="160.4" cy="115.4" r=".25"/>
<circle cx="160.4" cy="117.8" r=".25"/>
<circle cx="160.8" cy="105.3" r=".25"/>
<circle cx="161.2" cy="117.2" r=".25"/>
<circle cx="161.5" cy="102.4" r=".25"/>
<circle cx="161.7" cy="108.5" r=".25"/>
<circle cx="161.9" cy="102.9" r=".25"/>
<circle cx="162" cy="104.3" r=".25"/>
<circle cx="163.6" cy="105.9" r=".25"/>
<circle cx="165.1" cy="103" r=".25"/>
<circle cx="165.2" cy="106" r=".25"/>
<circle cx="165.7" cy="117.3" r=".25"/>
<circle cx="166.4" cy="119.9" r=".25"/>
<circle cx="167.6" cy="114.5" r=".25"/>
<circle cx="167.8" cy="113.3" r=".25"/>
<circle cx="167.9" cy="119.2" r=".25"/>
<circle cx="167.9" cy="109.2" r=".25"/>
<circle cx="170.2" cy="115.4" r=".25"/>
<circle cx="170.3" cy="114.2" r=".25"/>
<circle cx="173.1" cy="109.7" r=".25"/>
<circle cx="173.1" cy="114" r=".25"/>
<circle cx="173.4" cy="113.4" r=".25"/>
<circle cx="173.5" cy="108.1" r=".25"/>
<circle cx="174.6" cy="102.4" r=".25"/>
<circle cx="175.3" cy="107.3" r=".25"/>
<circle cx="175.3" cy="108.8" r=".25"/>
<circle cx="175.3" cy="105.8" r=".25"/>
<circle cx="175.3" cy="111.9" r=".25"/>
<circle cx="176.1" cy="102.4" r=".25"/>
<circle cx="177.7" cy="108.3" r=".25"/>
<circle cx="177.9" cy="114.9" r=".25"/>
<circle cx="178.6" cy="111.5" r=".25"/>
<circle cx="178.8" cy="116.1" r=".25"/>
<circle cx="178.8" cy="112.5" r=".25"/>
<circle cx="179.3" cy="108.6" r=".25"/>
<circle cx="179.3" cy="109.6" r=".25"/>
<circle cx="179.3" cy="107.5" r=".25"/>
<circle cx="180.1" cy="112" r=".25"/>
<circle cx="180.3" cy="108.6" r=".25"/>
<circle cx="180.3" cy="109.6" r=".25"/>
<circle cx="180.3" cy="107.5" r=".25"/>
<circle cx="180.3" cy="108.6" r=".23"/>
<circle cx="180.5" cy="103.9" r=".25"/>
<circle cx="180.5" cy="101.8" r=".25"/>
<circle cx="180.6" cy="111.2" r=".25"/>
<circle cx="181" cy="111.8" r=".25"/>
<circle cx="181.4" cy="108.6" r=".25"/>
<circle cx="181.4" cy="109.6" r=".25"/>
<circle cx="181.4" cy="107.5" r=".25"/>
<circle cx="181.5" cy="104.8" r=".25"/>
<circle cx="181.6" cy="111.4" r=".25"/>
<circle cx="181.9" cy="113.2" r=".25"/>
<circle cx="182.1" cy="106.9" r=".25"/>
<circle cx="183" cy="101.8" r=".25"/>
<circle cx="183.3" cy="106.3" r=".25"/>
<circle cx="183.3" cy="110.4" r=".25"/>
<circle cx="183.5" cy="113.2" r=".25"/>
<circle cx="183.8" cy="107" r=".25"/>
<circle cx="184.3" cy="107.6" r=".25"/>
<circle cx="186.1" cy="115.1" r=".5"/>
<circle cx="187.7" cy="106.5" r=".25"/>
<circle cx="187.7" cy="110.4" r=".25"/>
<circle cx="187.7" cy="112.9" r=".25"/>
<circle cx="187.7" cy="104" r=".25"/>
<circle cx="189.9" cy="111.6" r=".25"/>
<circle cx="189.9" cy="105.3" r=".25"/>
<circle cx="196.5" cy="111.6" r=".25"/>
<circle cx="196.5" cy="105.3" r=".25"/>
<circle cx="207" cy="119.2" r=".5"/>
<circle cx="219.5" cy="104.1" r=".75"/>
<circle cx="219.5" cy="106.6" r=".75"/>
<circle cx="219.5" cy="114.2" r=".75"/>
<circle cx="219.5" cy="116.8" r=".75"/>
<circle cx="219.5" cy="101.5" r=".75"/>
<circle cx="219.5" cy="111.7" r=".75"/>
<circle cx="219.5" cy="119.3" r=".75"/>
<circle cx="219.5" cy="109.1" r=".75"/>
<circle cx="224.5" cy="109.1" r=".75"/>
<circle cx="224.5" cy="119.3" r=".75"/>
<circle cx="224.5" cy="101.5" r=".75"/>
<circle cx="224.5" cy="111.7" r=".75"/>
<circle cx="224.5" cy="106.6" r=".75"/>
<circle cx="224.5" cy="116.8" r=".75"/>
<circle cx="224.5" cy="104.1" r=".75"/>
<circle cx="224.5" cy="114.2" r=".75"/>
<circle cx="73.7" cy="134.1" r=".25"/>
<circle cx="75.3" cy="129.5" r=".25"/>
<circle cx="75.3" cy="130.4" r=".25"/>
<circle cx="75.3" cy="128.6" r=".25"/>
<circle cx="76.2" cy="130.4" r=".25"/>
<circle cx="76.2" cy="129.5" r=".25"/>
<circle cx="76.2" cy="128.6" r=".25"/>
<circle cx="77" cy="134.1" r=".25"/>
<circle cx="77.9" cy="139.7" r=".25"/>
<circle cx="77.9" cy="137.9" r=".25"/>
<circle cx="77.9" cy="137" r=".25"/>
<circle cx="77.9" cy="136.1" r=".25"/>
<circle cx="77.9" cy="138.8" r=".25"/>
<circle cx="78.1" cy="120.9" r=".5"/>
<circle cx="78.7" cy="134.4" r=".5"/>
<circle cx="78.7" cy="133.1" r=".5"/>
<circle cx="80" cy="133.1" r=".5"/>
<circle cx="80" cy="134.4" r=".5"/>
<circle cx="80" cy="136.1" r=".25"/>
<circle cx="80" cy="139.7" r=".25"/>
<circle cx="80" cy="137" r=".25"/>
<circle cx="80" cy="138.8" r=".25"/>
<circle cx="80" cy="137.9" r=".25"/>
<circle cx="80.5" cy="120.9" r=".5"/>
<circle cx="80.9" cy="136.1" r=".25"/>
<circle cx="80.9" cy="139.7" r=".25"/>
<circle cx="81.8" cy="139.7" r=".25"/>
<circle cx="83.1" cy="120.9" r=".5"/>
<circle cx="85.5" cy="136.6" r=".25"/>
<circle cx="85.5" cy="137.9" r=".25"/>
<circle cx="85.5" cy="139.2" r=".25"/>
<circle cx="85.7" cy="133.1" r=".5"/>
<circle cx="85.7" cy="134.4" r=".5"/>
<circle cx="87.1" cy="126.1" r=".5"/>
<circle cx="87.1" cy="127.4" r=".5"/>
<circle cx="87.1" cy="131.2" r=".5"/>
<circle cx="87.1" cy="128.6" r=".5"/>
<circle cx="87.1" cy="133.1" r=".5"/>
<circle cx="87.1" cy="134.4" r=".5"/>
<circle cx="87.1" cy="129.9" r=".5"/>
<circle cx="88.4" cy="126.1" r=".5"/>
<circle cx="88.4" cy="127.4" r=".5"/>
<circle cx="88.4" cy="128.6" r=".5"/>
<circle cx="88.4" cy="136.5" r=".5"/>
<circle cx="88.4" cy="133.1" r=".5"/>
<circle cx="88.4" cy="131.2" r=".5"/>
<circle cx="88.4" cy="137.8" r=".5"/>
<circle cx="88.4" cy="134.4" r=".5"/>
<circle cx="88.4" cy="129.9" r=".5"/>
<circle cx="89.7" cy="126.1" r=".5"/>
<circle cx="89.7" cy="127.4" r=".5"/>
<circle cx="89.7" cy="128.6" r=".5"/>
<circle cx="89.7" cy="131.2" r=".5"/>
<circle cx="89.7" cy="129.9" r=".5"/>
<circle cx="89.7" cy="134.4" r=".5"/>
<circle cx="89.7" cy="133.1" r=".5"/>
<circle cx="89.7" cy="137.8" r=".5"/>
<circle cx="89.7" cy="136.5" r=".5"/>
<circle cx="91.7" cy="137.8" r=".5"/>
<circle cx="91.7" cy="139.1" r=".5"/>
<circle cx="91.7" cy="136.5" r=".5"/>
<circle cx="91.8" cy="126.1" r=".5"/>
<circle cx="91.8" cy="127.4" r=".5"/>
<circle cx="91.8" cy="128.6" r=".5"/>
<circle cx="91.8" cy="131.2" r=".5"/>
<circle cx="91.8" cy="129.9" r=".5"/>
<circle cx="93" cy="139.1" r=".5"/>
<circle cx="93" cy="137.8" r=".5"/>
<circle cx="93" cy="136.5" r=".5"/>
<circle cx="93.1" cy="126.1" r=".5"/>
<circle cx="93.1" cy="127.4" r=".5"/>
<circle cx="93.1" cy="128.6" r=".5"/>
<circle cx="93.1" cy="131.2" r=".5"/>
<circle cx="93.1" cy="129.9" r=".5"/>
<circle cx="94.4" cy="126.1" r=".5"/>
<circle cx="94.4" cy="127.4" r=".5"/>
<circle cx="94.4" cy="128.6" r=".5"/>
<circle cx="94.4" cy="131.2" r=".5"/>
<circle cx="94.4" cy="129.9" r=".5"/>
<circle cx="97.2" cy="136.3" r=".25"/>
<circle cx="97.2" cy="135.2" r=".25"/>
<circle cx="97.2" cy="139.7" r=".25"/>
<circle cx="98.2" cy="135.2" r=".25"/>
<circle cx="98.4" cy="120.9" r=".5"/>
<circle cx="99.2" cy="135.2" r=".25"/>
<circle cx="100.2" cy="135.2" r=".25"/>
<circle cx="101" cy="120.9" r=".5"/>
<circle cx="101.2" cy="139.7" r=".25"/>
<circle cx="101.2" cy="135.2" r=".25"/>
<circle cx="101.2" cy="136.3" r=".25"/>
<circle cx="103.5" cy="120.9" r=".5"/>
<circle cx="104.6" cy="136.9" r=".25"/>
<circle cx="104.6" cy="137.9" r=".25"/>
<circle cx="104.6" cy="138.9" r=".25"/>
<circle cx="106.3" cy="137.9" r=".25"/>
<circle cx="107.4" cy="126.1" r=".5"/>
<circle cx="107.4" cy="127.4" r=".5"/>
<circle cx="107.4" cy="131.2" r=".5"/>
<circle cx="107.4" cy="128.6" r=".5"/>
<circle cx="107.4" cy="129.9" r=".5"/>
<circle cx="107.9" cy="138.9" r=".25"/>
<circle cx="107.9" cy="137.9" r=".25"/>
<circle cx="107.9" cy="136.9" r=".25"/>
<circle cx="108.7" cy="126.1" r=".5"/>
<circle cx="108.7" cy="127.4" r=".5"/>
<circle cx="108.7" cy="128.6" r=".5"/>
<circle cx="108.7" cy="129.9" r=".5"/>
<circle cx="108.7" cy="131.2" r=".5"/>
<circle cx="110" cy="126.1" r=".5"/>
<circle cx="110" cy="127.4" r=".5"/>
<circle cx="110" cy="131.2" r=".5"/>
<circle cx="110" cy="128.6" r=".5"/>
<circle cx="110" cy="129.9" r=".5"/>
<circle cx="111.8" cy="134.9" r=".25"/>
<circle cx="111.8" cy="133.9" r=".25"/>
<circle cx="111.8" cy="135.9" r=".25"/>
<circle cx="112.8" cy="133.9" r=".25"/>
<circle cx="112.8" cy="135.9" r=".25"/>
<circle cx="112.8" cy="134.9" r=".25"/>
<circle cx="112.9" cy="126.5" r=".25"/>
<circle cx="119.5" cy="135.4" r=".25"/>
<circle cx="120.3" cy="135.4" r=".25"/>
<circle cx="120.4" cy="132.1" r=".25"/>
<circle cx="121.5" cy="137.4" r=".25"/>
<circle cx="122.6" cy="137.4" r=".25"/>
<circle cx="122.8" cy="120.3" r=".25"/>
<circle cx="122.8" cy="124.6" r=".25"/>
<circle cx="122.8" cy="123.5" r=".25"/>
<circle cx="123.6" cy="133.4" r=".25"/>
<circle cx="123.6" cy="137.4" r=".25"/>
<circle cx="124" cy="121" r=".25"/>
<circle cx="124.3" cy="125.1" r=".25"/>
<circle cx="124.7" cy="127.5" r=".25"/>
<circle cx="125.2" cy="124.2" r=".25"/>
<circle cx="125.5" cy="135.9" r=".25"/>
<circle cx="127.8" cy="127.5" r=".25"/>
<circle cx="130.7" cy="127.5" r=".25"/>
<circle cx="131.6" cy="124.5" r=".25"/>
<circle cx="131.8" cy="127.5" r=".25"/>
<circle cx="132.8" cy="120.3" r=".25"/>
<circle cx="133.2" cy="124.3" r=".25"/>
<circle cx="133.2" cy="127.5" r=".25"/>
<circle cx="133.3" cy="122.2" r=".25"/>
<circle cx="134.5" cy="127.4" r=".25"/>
<circle cx="135.6" cy="124.3" r=".25"/>
<circle cx="136.8" cy="124.2" r=".25"/>
<circle cx="137" cy="123.4" r=".25"/>
<circle cx="137.3" cy="129.9" r=".25"/>
<circle cx="137.7" cy="127.5" r=".25"/>
<circle cx="138.7" cy="135.6" r=".25"/>
<circle cx="138.7" cy="136.6" r=".25"/>
<circle cx="138.7" cy="138.7" r=".25"/>
<circle cx="138.7" cy="137.7" r=".25"/>
<circle cx="138.7" cy="133.6" r=".25"/>
<circle cx="138.7" cy="134.6" r=".25"/>
<circle cx="138.7" cy="132.6" r=".25"/>
<circle cx="139.7" cy="133.6" r=".25"/>
<circle cx="139.7" cy="138.7" r=".25"/>
<circle cx="139.7" cy="134.6" r=".25"/>
<circle cx="139.7" cy="132.6" r=".25"/>
<circle cx="139.7" cy="137.7" r=".25"/>
<circle cx="139.7" cy="136.6" r=".25"/>
<circle cx="139.7" cy="135.6" r=".25"/>
<circle cx="140.2" cy="123.6" r=".25"/>
<circle cx="140.7" cy="127.6" r=".25"/>
<circle cx="141.6" cy="126.7" r=".25"/>
<circle cx="142.1" cy="132.3" r=".25"/>
<circle cx="142.1" cy="129" r=".25"/>
<circle cx="142.2" cy="133.6" r=".25"/>
<circle cx="144.7" cy="129" r=".25"/>
<circle cx="145.6" cy="122.3" r=".25"/>
<circle cx="146.4" cy="126.5" r=".25"/>
<circle cx="146.4" cy="120.2" r=".25"/>
<circle cx="147.3" cy="129" r=".25"/>
<circle cx="149" cy="120.1" r=".25"/>
<circle cx="149.1" cy="125.7" r=".25"/>
<circle cx="149.2" cy="129.8" r=".25"/>
<circle cx="149.4" cy="124.6" r=".25"/>
<circle cx="149.7" cy="122.2" r=".25"/>
<circle cx="149.9" cy="129.8" r=".25"/>
<circle cx="150.5" cy="129.8" r=".25"/>
<circle cx="151.1" cy="129.8" r=".25"/>
<circle cx="151.8" cy="129.8" r=".25"/>
<circle cx="151.9" cy="122.2" r=".25"/>
<circle cx="152.5" cy="129.7" r=".25"/>
<circle cx="152.9" cy="127.4" r=".25"/>
<circle cx="153" cy="130.1" r=".25"/>
<circle cx="153.5" cy="129.7" r=".25"/>
<circle cx="154.3" cy="120.1" r=".25"/>
<circle cx="154.5" cy="130" r=".25"/>
<circle cx="154.8" cy="130.6" r=".25"/>
<circle cx="155.4" cy="130.1" r=".25"/>
<circle cx="155.4" cy="131" r=".25"/>
<circle cx="156.6" cy="126.5" r=".25"/>
<circle cx="156.9" cy="122.8" r=".25"/>
<circle cx="157" cy="129.7" r=".25"/>
<circle cx="158.1" cy="127.5" r=".25"/>
<circle cx="158.5" cy="125.1" r=".25"/>
<circle cx="158.8" cy="120.2" r=".25"/>
<circle cx="159.5" cy="121.8" r=".25"/>
<circle cx="159.5" cy="121.2" r=".25"/>
<circle cx="160.3" cy="127.5" r=".25"/>
<circle cx="160.7" cy="122.7" r=".25"/>
<circle cx="160.7" cy="124.5" r=".25"/>
<circle cx="160.9" cy="127.5" r=".25"/>
<circle cx="161.4" cy="136.6" r=".25"/>
<circle cx="161.4" cy="135.6" r=".25"/>
<circle cx="161.4" cy="134.6" r=".25"/>
<circle cx="161.4" cy="137.7" r=".25"/>
<circle cx="161.4" cy="138.7" r=".25"/>
<circle cx="161.4" cy="133.6" r=".25"/>
<circle cx="161.5" cy="127.5" r=".25"/>
<circle cx="162.2" cy="120.5" r=".25"/>
<circle cx="162.4" cy="126" r=".25"/>
<circle cx="162.4" cy="138.7" r=".25"/>
<circle cx="162.4" cy="135.6" r=".25"/>
<circle cx="162.4" cy="134.6" r=".25"/>
<circle cx="162.4" cy="137.7" r=".25"/>
<circle cx="162.4" cy="136.6" r=".25"/>
<circle cx="162.4" cy="133.6" r=".25"/>
<circle cx="162.4" cy="127.5" r=".25"/>
<circle cx="163.1" cy="122.9" r=".25"/>
<circle cx="163.8" cy="122.9" r=".25"/>
<circle cx="164.1" cy="127.6" r=".25"/>
<circle cx="164.6" cy="122.9" r=".25"/>
<circle cx="165.2" cy="129.8" r=".25"/>
<circle cx="165.4" cy="123" r=".25"/>
<circle cx="166.2" cy="122.9" r=".25"/>
<circle cx="166.5" cy="127.6" r=".25"/>
<circle cx="166.5" cy="132.8" r=".25"/>
<circle cx="167" cy="127.2" r=".25"/>
<circle cx="167.7" cy="120.8" r=".25"/>
<circle cx="168.4" cy="137.2" r=".25"/>
<circle cx="170.1" cy="125.1" r=".25"/>
<circle cx="176.1" cy="131.8" r="1.1"/>
<circle cx="176.1" cy="121.7" r="1.1"/>
<circle cx="196.5" cy="129.3" r="1.1"/>
<circle cx="196.5" cy="134.4" r="1.1"/>
<circle cx="205" cy="134.9" r="1.15"/>
<circle cx="207" cy="120.5" r=".5"/>
<circle cx="207" cy="121.8" r=".5"/>
<circle cx="209.5" cy="134.9" r="1.15"/>
<circle cx="213.4" cy="120.1" r=".5"/>
<circle cx="219.5" cy="126.9" r=".75"/>
<circle cx="219.5" cy="129.5" r=".75"/>
<circle cx="219.5" cy="139.6" r=".75"/>
<circle cx="219.5" cy="137.1" r=".75"/>
<circle cx="219.5" cy="132" r=".75"/>
<circle cx="219.5" cy="134.5" r=".75"/>
<circle cx="219.5" cy="124.4" r=".75"/>
<circle cx="219.5" cy="121.8" r=".75"/>
<circle cx="224.5" cy="126.9" r=".75"/>
<circle cx="224.5" cy="132" r=".75"/>
<circle cx="224.5" cy="129.5" r=".75"/>
<circle cx="224.5" cy="137.1" r=".75"/>
<circle cx="224.5" cy="139.6" r=".75"/>
<circle cx="224.5" cy="134.5" r=".75"/>
<circle cx="224.5" cy="121.8" r=".75"/>
<circle cx="224.5" cy="124.4" r=".75"/>
<circle cx="75.3" cy="141.9" r=".25"/>
<circle cx="77.6" cy="143.5" r=".5"/>
<circle cx="81.4" cy="147.1" r=".5"/>
<circle cx="82.8" cy="143.5" r=".5"/>
<circle cx="82.8" cy="147.1" r=".5"/>
<circle cx="84.1" cy="147.1" r=".5"/>
<circle cx="84.1" cy="143.5" r=".5"/>
<circle cx="95.1" cy="146.9" r=".25"/>
<circle cx="95.1" cy="143.6" r=".25"/>
<circle cx="97.2" cy="140.7" r=".25"/>
<circle cx="98.2" cy="140.7" r=".25"/>
<circle cx="99.2" cy="140.7" r=".25"/>
<circle cx="100.2" cy="140.7" r=".25"/>
<circle cx="101.2" cy="140.7" r=".25"/>
<circle cx="103.1" cy="145.3" r=".25"/>
<circle cx="104.5" cy="143.1" r=".5"/>
<circle cx="111.8" cy="140.7" r=".25"/>
<circle cx="111.8" cy="141.7" r=".25"/>
<circle cx="111.8" cy="142.7" r=".25"/>
<circle cx="112.8" cy="141.7" r=".25"/>
<circle cx="112.8" cy="142.7" r=".25"/>
<circle cx="112.8" cy="140.7" r=".25"/>
<circle cx="119.8" cy="143.8" r=".25"/>
<circle cx="120.3" cy="141.2" r=".25"/>
<circle cx="123.6" cy="141.2" r=".25"/>
<circle cx="123.6" cy="142.2" r=".25"/>
<circle cx="124.8" cy="141.2" r=".25"/>
<circle cx="131.1" cy="141.9" r=".6"/>
<circle cx="133.6" cy="141.9" r=".6"/>
<circle cx="145.2" cy="145.4" r=".5"/>
<circle cx="145.2" cy="146.9" r=".5"/>
<circle cx="146.4" cy="146.9" r=".5"/>
<circle cx="147.7" cy="146.9" r=".5"/>
<circle cx="152.1" cy="141.9" r=".6"/>
<circle cx="154.7" cy="141.9" r=".6"/>
<circle cx="167" cy="146.8" r=".5"/>
<circle cx="168.3" cy="146.8" r=".5"/>
<circle cx="169.5" cy="146.8" r=".5"/>
<circle cx="176.1" cy="142" r="1.1"/>
<circle cx="196.5" cy="142" r="1.1"/>
<circle cx="205" cy="144.9" r="1.15"/>
<circle cx="209.5" cy="144.9" r="1.15"/>
<circle cx="212" cy="145.3" r=".25"/>
<circle cx="212" cy="141.5" r=".25"/>
<circle cx="212" cy="144" r=".25"/>
<circle cx="212" cy="146.6" r=".25"/>
<circle cx="212" cy="142.7" r=".25"/>
<circle cx="216.2" cy="145.3" r=".25"/>
<circle cx="216.2" cy="141.5" r=".25"/>
<circle cx="216.2" cy="144" r=".25"/>
<circle cx="216.2" cy="146.6" r=".25"/>
<circle cx="216.2" cy="142.7" r=".25"/>
<circle cx="217.7" cy="144" r=".5"/>
<circle cx="227.1" cy="144.7" r="2.05"/>
</g>
<g fill="#000">
<circle cx="90.4" cy="105.9" r=".6"/>
<circle cx="90.4" cy="103.4" r=".6"/>
<circle cx="91.7" cy="104.6" r=".6"/>
<circle cx="114.7" cy="118.5" r=".85"/>
<circle cx="117.2" cy="118.5" r=".85"/>
<circle cx="198.3" cy="105.3" r=".25"/>
<circle cx="114.7" cy="121" r=".85"/>
<circle cx="114.7" cy="123.6" r=".85"/>
<circle cx="114.7" cy="126.1" r=".85"/>
<circle cx="114.7" cy="128.6" r=".85"/>
<circle cx="117.2" cy="121" r=".85"/>
<circle cx="117.2" cy="126.1" r=".85"/>
<circle cx="117.2" cy="123.6" r=".85"/>
<circle cx="141.9" cy="136" r=".5"/>
<circle cx="143.1" cy="136" r=".5"/>
<circle cx="143.1" cy="137.3" r=".5"/>
<circle cx="144.4" cy="136" r=".5"/>
<circle cx="144.4" cy="137.3" r=".5"/>
<circle cx="145.7" cy="137.3" r=".5"/>
<circle cx="145.7" cy="136" r=".5"/>
<circle cx="146.9" cy="136" r=".5"/>
<circle cx="146.9" cy="137.3" r=".5"/>
<circle cx="165.5" cy="137" r=".85"/>
</g>
<path d="M89 104.6h.4" fill="none" stroke="#000" stroke-width="1.2"/>
<g fill="none" stroke="#000" stroke-width=".14">
<path d="M132.2 78.9h.6M150.2 92h1.4l.9 .9v11.6l1 1v.7M154.8 96.9l.8 .8v7.2l-.6 .6v.5M154.8 96.3l1 1v8l-.2 .2v.8M154.8 97.5l.5 .5v6.6l-.9 .9v.8M155.6 92.6h-1.7l-1.2 1.2v10.4l1.2 1.2v.4M178 92.6l-.2 .2v1.2M205.7 83.3h-.4l-3 3h-17.3l-1.4 1.4h-9.5l-2.7 2.7v8.8l-2 2h-9l-.9 .9v3.2l.4 .4M205.7 81.9l-.5 .5v.3l-3.1 3.1h-17.4l-1.4 1.4h-9.5l-2.9 2.9v8.7l-1.9 1.9h-8.9l-1.1 1.1v3.4l-.6 .5h-.5M205.7 81.3l-.8 .7v.6l-2.9 2.9h-17.5l-1.4 1.5h-9.5l-2.9 2.9v8.6l-1.9 2h-8.8l-1.3 1.2v3.1l-.4 .4h-.5l-.6 .5M205.7 83.9h-.6l-2.6 2.7h-17.3l-1.5 1.4h-9.5l-2.5 2.5v8.9l-2 2.1h-3.1l-.6 .5v2.8l-.8 .7v.5M205.7 82.6l-3.5 3.4h-17.3l-1.5 1.5h-9.5l-2.7 2.7v8.9l-1.9 1.9h-9l-1 1v3.7"/>
<path d="M227.6 91.7h1.7v9.9h-1.7zM227.6 98.3h1.7M227.6 96.6h1.7M227.6 95h1.7M227.6 99.9h1.7M114 109l.3 .3h.8M114 110.5l.4 .4h.7M114.7 118.5l-1.3 1.3v2l.5 .5h4.5l.4-.4h5.3l.2 .3v.5l.2 .1h1l.6-.6h6.1l.6-.7h3.1l.4 .4h3.3l.6 .6v1.1M114.9 113.7v1.1M114.9 113.7h.1M115.5 105.5l-.4 .3M115.6 107.4h-.5"/>
<path d="M117.1 113.7l-.1 .1v1M120.3 110.2l-.7 .7h-2.8M120.3 109.2l-.2 .1h-3.3M120.3 112.2l-.2 .2h-3.3M120.9 107.8l-.6 .7h-4l-.3 .3v3l-.5 .4h-.2M124.5 119.4h1.1l.3 .2h1.2M128.3 114.5v1.1M130.7 110.9v1.5h-1.1l-.4 .4h-.9M130.7 108.5v.6M134.2 118.7l.1-.3h-2l-.7-.8h-3.2l-1-1h-10.6l-.8 .9v2.3l-1.3 1.2M137 118.1v-.6h-.7l-.4 .4v1.5l-.3 .2h-6.6l-.6-.6h-2.5l-.6-.5h-8.1M145.4 102.9v6.3l1 1"/>
<path d="M150.2 112.4v1l.2 .1M150.5 110.2h-.9l-.1 .1v.6M150.7 100.2v.4l.2 .1h.9M151 112.4v1l.1 .1M152 114.4v1.2l-2.2 2.2v3.2l-1.2 1.1v1.5M152.5 115.1v.8l-2.3 2.3v5.4M152.6 112.4v.6l-1.2 1.3v.2M152.9 114.4l.3 .3v1.3l-2.2 2.1v5.5M153.4 113h.1M153.4 112.4v.6M153.9 114.4v1.8l-1.3 1.3v6.1M154.3 119.1l-.1 4.5"/>
<path d="M155 112.4v.6h.1M155.1 114.4l-.4 .4v1.5l-1.3 1.3v6M155.8 112.4v.6M155.8 112.4h.1M156.6 113.8l-1.6 1.5v8.3M157.2 113.8l-1.4 1.4v8.4M157.4 112.4l.1 .7M158.5 106.3h.5l.8 .8h2.9l1.1 1.1v4.2M159 108.2v-.4l.4-.4h2.8l.8 .9v4.1M159 112.4v3.4l-.3 .3M159.8 112.4v4.8l.6 .6M160.4 109.6h.5l.8 .7v.6"/>
<path d="M160.4 108.8l-1.1 1.2h-5.2l-.6-.5v-1.3l-.6-.6h-3.5l-.8 .7v4.1M160.6 112.4v2.7l-.2 .3M160.8 104.1v1.2M161.4 112.4v4.5l-.2 .3M161.9 102.9l-.4 .4v2l.7 .6h1.4M162.2 112.4v4.6l-1.2 1.2h-3.6M164.6 112.4v4.5l.4 .4h.7M165.1 104.1h-3l-.1 .2M165.4 112.4v1.2l.7 .7v3.7l-.7 .7-6.9 .1M166.2 112.4v1.5M166.2 113.9l.2 .1v4.1l-.9 .9h-6.5l-.4 .4h-.2M166.2 113.9h.1"/>
<path d="M167 112.4v1.2l-.4 .4v4.4l-.9 .8h-6.3l-.3 .3M167.8 113.3v.3l-.7 .7v4.3l-1.1 1.2h-5.8l-1.2 1.1h-1l-.6 .5v2.2M167.8 112.4v.2l-.5 .5v.6l-.4 .5v4.3l-1 1h-6.1l-.5 .5h-.2l-.3 .2M207 119.2v1.3M75.3 128.6v.9M75.3 130.4h.9M76.2 128.6v.9M77.9 137v1.8M78.7 133.1v1.3M80 133.1v1.3M80 137v.9M80 138.8v.9"/>
<path d="M80 136.1h.9M80.9 139.7h.9M85.5 136.6v1.3M87.1 133.1h1.3M87.1 134.4h1.3M88.4 136.5h1.3M88.4 137.8h1.3M88.4 129.9v1.3M89.7 133.1v1.3M91.7 137.8v1.3M91.8 127.4v1.2h2.6M91.8 126.1h2.6"/>
<path d="M91.8 131.2h2.6M93 136.5v1.3M93.1 129.9h1.3M97.2 138.6v1.1M98.2 135.2h-1v2.1M99.2 135.2v1.2M101.2 135.2v1.1M104.6 136.9v1h1.7M107.9 136.9v1M111.8 134.9v1h1v-1M114.7 123.6l1.3 1.2h3.6l1.2 1.2h15.4l.8 .9h.9v.3l-.2 .3M117.2 123.6h2.6l.4 .3h4.4l.7-.7h10.5l1 1"/>
<path d="M123.6 136.4h-.5l-.5 .5v1.3l-.5 .5h-.6M125.2 124.2v.9h-.9M132.8 120.3h-3.8l-.7 .6h-2.4l-.8-.8h-1.3l-.4-.3h-1.2l-1.3 1.2h-3.7M134.3 120.9h2.6l.1 .1M136.5 128.6v.9l.4 .4h.4M138.7 138.7h1M138.7 132.6v1M138.7 134.6v2M139.7 132.6v1M139.7 134.6v1M139.7 136.6v1.1M144 134.2h2.2l.7 .8v1"/>
<path d="M145.7 121.7l-.1 .6M149.4 123.6v1M150 129.7l-.1 .1M152.5 129.7v.2l-.3 .4h-9.6l-.5 .5v.5M153 130.1l-.4 .4h-7.7l-.2 .3v.5M153.5 129.7v.5l-.6 .6h-5.1l-.5 .5M159.5 121.8h6.7l.8 .8v1M159.5 121.2h7.1l1.2 1.2v1.2M159.8 123.6v1.4l-.8 .9h-9.4l-.2-.2h-.3M160.4 135.6h1v1M160.7 122.7l-.1 .9M161.4 133.6h1"/>
<path d="M161.4 138.7h1M161.4 123.6v.6l-.2 .3h-.5M162.2 120.5l.3 .3h5.2M162.4 134.6v1M162.4 136.6v1.1M162.4 126h-1.6l-2.2 2.1h-15.6l-1.4-1.4M163.1 122.9l-.1 .7M163.8 122.9h.1M163.8 122.9v.7M164.6 122.9v.7M165.5 122.9l-.1 .7M166.2 122.9v.7"/>
<path d="M166.2 122.9h.1M81.4 147.1h1.4M82.8 143.5h1.3M97.2 140.7h1M99.2 140.7h2M111.8 141.7v1M111.8 140.7h1M112.8 141.7v1M145.2 145.4v1.5h1.2M168.3 146.8h1.2M176.1 142l1.1 1.1h.4l1.1-1.1h6.1M212 142.7v2.6"/>
<path d="M212 144h1.2l.4 .4M216.2 141.5v2.5"/>
</g>
<g fill="none" stroke="#000" stroke-width=".51">
<path d="M86.8 57.1h.6M100.8 57l.1 .8M102.6 57.8h.5M109.4 57.8h.6M111.1 57.8h.7M77.2 71.9h.7M77.9 69.3h.5M79 74.3h.6M79.1 71.9h.5M79.6 69.3h.5M86 74.3l.5 .5v.4M86.1 61h.7"/>
<path d="M86.1 70.9h.7M86.5 76.9h2.5M87 76.9v.1M88.5 61h.7M100.2 60.3h.7M100.9 73.3h.6M100.9 79l-.1 .7M100.9 63.5h.6M100.9 65.8l-.3 .2h-.4M102 60.3h.6M102 65.8h.6M102.2 76.1h1"/>
<path d="M102.6 63.5h.7M108.7 60.3h.7M110.6 60.3h.5M118 65.8h1M118 68.3h-.5l-.5 .4v7.4l.5 .5h.6M118.1 74.3h1M120.3 74.3h.6M120.8 64.7v1.1M120.8 64.6v.1M123.2 74.3h1M123.3 65.8h.8M123.8 77.6l.4 .4v.4"/>
<path d="M125.2 65.8h.6M125.3 74.3h.7M126.2 77.6l-.2 .3v.5M128.9 74.3h.9M130.9 74.3h.7v-.9l.5-.5h4.2l.5 .5v.9h-.7M133.9 74.3h1.1M179.2 74v2.1l1.3 1.2v4.5M179.2 78.9v1.4l-.5 .5v2M180.5 78.9h.1M183.3 78.4v1.6l-1.1 1v.8M184 73.5h-1.8l-.5 .5v1.3M77.2 80.5l.3 .3v.6"/>
<path d="M80 83.2h-2.5v2.9l.4 .4M80.4 80.3l-.4 .4v.7M84.3 89.4h.7M84.3 95.1h.7M85 85.6h.6M86.1 95.1h.6M86.7 85.6h.7M86.7 89.4h.7M87.4 80.3l-.1 .2h-.5M87.9 83.1h.6M89.2 80.3l-.2 .2h-.5M93 95.1h.6"/>
<path d="M93.6 92.6v.1l-.6 .6v.5M94.7 95.1h.7M95.4 92.6h.6M97.5 89.3v.9M97.9 94.2v.8l.1 .1M98.6 92.5h-.7M100.2 81.5h.7M101.2 95l-.2 .2h-.5M102 81.5h.6M102.9 84.2v1.3M103.4 96.1v1M103.5 90.8h-.6l-.5 .5h-1.9"/>
<path d="M104.6 84.2v-.9l-.4-.4h-3.1l-.5 .5v1.7M105.3 90.7h-.5l-.2 .1M105.3 91.9h-.3l-.4 .4v.9M107.3 87.3l-.1 .1h-1l-.8 .7h-.8M107.3 94.4h-1.4l-.8 .7v1M107.7 96.1l-1 1h-18.3l-1.5 1.6v2.4l1.7 1.8v1.2l.6 .5M118.1 82.7h1M119.8 97.8h.6M120.4 82.2l.5 .5M120.4 95.2v.9l.4 .4h.9l.5 .5v1.6l-.5 .5h-3.3l-.4-.4v-.8M120.5 86.5h.7M122.2 95.2h.5"/>
<path d="M122.3 86.5h.5M123.2 82.7h1M124.2 91.9v4.8l-1.1 1.1h-.9M127 82.5h-.9l-.1 .2M127.1 85.8v5.3M127.1 92.2v.6M128.8 82.6l.9 .1M130 93l-.4 .5v2.1M130 97.1v.4l.2 .2h.9M130.8 82.5l.1 .2h.5v-.8l.6-.6h4.1l.5 .5v.9M131 93l.3 .3v.7M131.3 91.2v.5l.4 .4h.5"/>
<path d="M133.9 82.7h1M134 92.1v2.2l-1.4 1.3h-1.3M145.4 97h.5M145.5 94.7h-1.9l.1 4.7M150.6 91.1h1.2M150.7 94.4l.4 .3h.7M151.5 98.2h-.9M154.6 98.2h-.8v1.1l-.3 .3v1.1M160.7 90.7h2.9M163.6 92.6h-1l-.5 .5h-1M174 92.8l.4 .4v.4M174.4 95.9v2.3"/>
<path d="M174.4 96.9h.1M177.8 95.7v.9l-.3 .3h-3.5M182.5 89.1l-.1 .2h-3.3M189 89.1l.2 .3h3M197.7 90.3h2.1M214.2 97.8l.2-.1h6.8l1.4 1.3h1.9M113.2 114.8h.6M115.1 103.9v1.9M116 106.7h.1M116.8 103.9v.7M116.8 107.4l.4 .4h.3M116.8 105.8l-.8 .9"/>
<path d="M117.6 104.8v.3l.4 .4h.9M118 103.8h.6l.2 .1M118.1 114.8h.6M121.5 105.4l.2 .1h.6M123.1 111.8h-.3l-.2 .2M127.1 118.4h1.9M129.5 108.6l-.5 .5h-.7M131.6 104.8h-.4l-.1 .1M131.8 112.4h.6M131.8 112.4h.1M132.3 104.8h.4l.1 .1M132.5 110.9l-.1 3"/>
<path d="M133.7 108.6l.6 .5h.6M137 119.2v.7M139.7 108.3v.8M140.2 116.9v.1h.5M140.7 119.2h.8M142.5 110.7v2.1l-.4 .4h-1.4M142.5 108.6v.7M145.4 101.7h2.6M145.7 114.8h.3l.4 .4M145.7 120h.5l.2 .2M149.5 108.5v.6M149.5 110.9h.9l.1 .1"/>
<path d="M150.7 108.5l.2 .1h1.4M151.5 101.7v.7M153.8 101.7v.7M156 108.5v.6M160.8 102.4h.7M161.5 102.4h.1M161.7 108.5v.6M165.1 102.4v.6M167 107.3l.3 .3v1.5M167.9 119.2l.7 .7h2.7M173.4 113.4h.7M173.5 108.1h.6"/>
<path d="M173.5 108.1h.1M174.1 107.3v1.5M174.1 111.9v3M174.6 102.4l-.7 .6h-.3M176.1 102.4l.6 .6h.5M178.8 114.9v1.2M189.2 111.6h.7M189.2 105.3h.7M190 110.1l-.1 .1v2.8l.1 .2M190 103.8l-.1 .1v2.8l.1 .1M196.5 111.6h1.8M196.5 105.3h1.8"/>
<path d="M74.4 131.6v2.5h-.7M76.2 134.1h.8M112.9 125.7v.8M114.7 123.6l-.4 .4h-1.4M122.8 120.3v.7M122.8 124.6v.5M127.8 126.9v.6M130.7 127.5l-.2 .1v2.8M131.6 124.5v.6M131.6 126.9v1.2l1 1.1v1.2M131.6 127.2l.2 .3M133.2 124.3v.8"/>
<path d="M133.3 122.2h1M135.6 124.3v.8h2.3M137 122.8v.6M140.7 126.9v.7M142.2 133.6l.1 .6M146.4 126.5l-.3 .4h-.4M156.6 126.5v.4h-.5M157.6 126.9l.5 .5v.1M164.2 126.9v.6l-.1 .1M165.2 129.8l.3 .2h3.5l.2 .2M166.5 132.1v.7M168.4 136.5v.7"/>
<path d="M168.9 125.1h2M75.3 141.9h-.2l-.7 .6v1M120.3 141.2l-.5 .5v2.1M124.8 141.2v.5l-.5 .5h-.7"/>
</g>
<g fill="none" stroke="#000" stroke-width=".38">
<path d="M76 59.4l-.1 .8M88.5 70.2v.7M89 74.5v.7M102.6 79h.7M86.1 83.1h.7M91.6 89.1v1.1M93 86.6l-.8 .8h-.6M96.1 87.1l.4 .4h1M104 86.4l.1 .1h.5M104 86.4h.1M132.8 97.7v.6l-.2 .3h-1.2M153.5 94.7h.7"/>
<path d="M153.5 91.1h1.2M174.4 95.9v2.3M205.6 85.2h1M208.4 85.2h1M146.3 110.9h.9l.6 .6v1.7l.3 .2h1.1l.2-.2v-.8M150.7 104.1h.8M151.5 104.1h.1M153.8 104.1h.1M153.8 104.1h.8M154.2 112.4v.9M154.2 113.3h.1M154.6 108.6v.5"/>
<path d="M156.1 110.9v.3l.5 .6v.6M158.2 112.4v.9M158.5 108.6v.5M168.9 110.9l-.3 .2v2.4l-1 1M119.5 135.4v.3l.3 .2v2.8M120.3 135.4h.7l.5 .5v.5M121.5 138.4v.3M123.4 138.9v2.1l.2 .2M123.6 133.4v.7M125.3 134.1v2.3l.2-.1v-.4M151.9 122.2l-.1 1.9-.4 .5v.5M152.9 126.9v.5"/>
<path d="M156.9 122.8l-.3 .2v1.5l-.5 .6"/>
</g>
<path d="M135.4 68.3h1M139.4 68.3h1.2M178.8 61.1v1M189.2 66.5v1.8M175.9 81.8h1M184.4 115.1h1.6M184.4 113l-.1 .2h-3.2M186.1 115.1h-.1M176.1 129.6v4.4" fill="none" stroke="#000" stroke-width=".89"/>
<g fill="none" stroke="#000" stroke-width=".25">
<path d="M77.7 59.4h2.7M82.2 59.4v-2.1l2-2h28.4l2.2 2.2v11.6l-1.1 1.1v29.7l2.8 2.8h24.9l3.1 3.2v2.7M84.2 57.1l1.3 1.3h8.4l2.9 2.9v4.9l.7 .7v.3M88.5 57.1h.5M91.1 59.7v1.3l-1.8 1.7h-.8v2.3M91.6 57.9h2.6l3.2 3.2v4.8l1.5 1.5h2.4l.6 .5v.7M113.8 59v8.9l-2.8 2.8h-3.6l-.7 .8v4.6l-2.1 2h-11.6l-1.9 1.9v1.8M76.3 69.7v4l.7 .6h.9M79.6 74.3v2.4l.9 .9h4.2M84.2 69.6h5.6l1.3 1.3M84.6 65.1v-.6l.5-.5h2.1l.4 .4v1.3l.4 .3h1.3l.5-.5M86.2 68.3h1l.8 .8h7.2"/>
<path d="M86.8 65l-.1 1.8 1.2 1.1h9l.6 .7h1.3M86.8 62.7h.2l.2 .3h.2M90.8 63.7l.2 .3h4l.9 .9v1.1M93.9 61h-2l-1.6 1.6v2.3l1.5 1.5v1M95.8 61.1v.7l-.5 .4h-2.7M98.3 63.5h.5l1.4-1.4h6.4l1.2 1.2v3M98.7 70.6v2.3l-.4 .4v1.8l1 1h.9M99.3 78.6l-.7 .8M99.3 78.6h.1M100.6 68.6l.1 .1v1.9h2M102.6 73.3h.5M104.8 70.6v2.7l-1.3 1.2h-3.2"/>
<path d="M105.9 69.1v6.8l-1.4 1.4h-11.2M109.9 68.4l-.9 .8h-1.6l-1-1h-1.9l-.7 .8v2.4l-.7 .6h-2.9l-.5-.5v-1.7l-.4-.3h-1.6l-.7 .6v4.6l-1.3 1.3h-9.5l-.2 .2h-.4M111.3 64.8l-2.9 3M75.7 87.7l-.4 .4v3.1l.4 .4M79.1 87.5l.8 .8h12.3l.1 .1h.4M80.9 86.9h7.9l.9-.9h3.8l2.1 2.1M100.2 93v.2l.3 .3M100.5 89.5h.4l.1 .4M100.6 87.1h.1M100.6 87.1h.7l.7-.6h.9v1.6M100.6 87.1v.5M103.3 80.3h-3l-.8 .8h-1.7l-.3 .3v3.9l.4 .4h.4"/>
<path d="M107.3 89v2.8l.4 .4M111 88.6h-1.3l-1 1.1v2.8l-.8 .7h-1.7l-1 1h-2.1l-.2-.2v-1.5l-.3-.3h-.4M117.9 86.5l-.2 .2v1.2l.7 .7h5.2l1.7 1.8v9.7l1.4 1.4h5.1M118.9 96.1h-.9M121.5 91.9h.9M127.1 95.5v.8M127.1 92.2l.2 .2M129.5 90.7v1.7l-.4 .4h-2M132.3 86.5v.6M132.3 85.1l.3 .2h1.1M135.3 91.3v4.7M139.1 87.6l.5 .5h.5"/>
<path d="M139.7 91.6l.4 .3v.6M140.5 96h-6.5l-.5 .5h-4.3l-2.1 2M144.7 99l.4 .4h.3v.2l-1.7 1.7v.4M194.9 90.9l.8 .8v5.1l-.4 .3M198.9 92.2l-.4 .4v1.1l.4 .4M204.9 91.7v3.8l-2.3 2.3M80.5 113.8h2.6M98.4 113.8v2.5M101 113.8h2.5M117.7 100.5l.5 .5h.3M120.5 100.5v.2l-.2 .3M124.5 117.1v.5"/>
<path d="M132.7 104.8h.1M154.6 110.9l-.4 .3v1.2M158.5 110.9l-.3 .2v1.3M167.3 109.1l.1 .1h.5M170.3 114.2l1 1v1M175.3 105.8h.6M175.3 108.8h.6M175.3 107.3h.6M175.9 111.9h-.6M178.8 112.5v.7M180.5 103.9h.4l.6 .5v.4h.6M180.5 101.2v.6"/>
<path d="M182.1 106.3v.6M183 101.2v.6M187.7 106.5h.3l.2 .3M187.7 112.9h.3l.2 .3M188.2 103.8h-.2l-.3 .2M188.2 110.1l-.2 .3h-.3M190.2 101.8h1.5M190.4 115.1h1.3M194.7 115.1h1M194.7 101.8h.8M122.8 122.8v.7M124 121h.5"/>
<path d="M125.2 126.9v.1l-.5 .5M142.1 129v.5M144.7 129v.5M147.3 129v.5M158.2 123.6v.6l.3 .3v.6h-.9M160.3 127.5v1.3l-.3 .3-.1 2.7-.1 .1h-1.8M160.9 127.5v1.2l1 .9v1.5l-.2 .1v.6l.1 .1h2M165.5 134.5l.2 .3h2.7"/>
</g>
<path d="M189.2 75.3h1.2M187.8 121.7h1.4M187.8 142h.7" fill="none" stroke="#000" stroke-width="1"/>
<path d="M176.1 121.7h8.7" fill="none" stroke="#000" stroke-width="1.4"/>
<g fill="none" stroke="#000" stroke-width=".76">
<path d="M157.7 57v2.9l4.3 4.3h20.2l1.2-1.2h2.8M165.4 58v2M186.1 56.1v4.8l.1 .1M189.1 56.1v3.6h1.9v-3.3l.3-.3M134.2 70.7h13.6l2.7-2.7h36.4l.3 .3v2.7M153.3 71.6v1.3M153.3 76.2v1.1M165.4 61.3v.8M174.9 71.5v1.3M174.9 76.1v.7M184 75.3v.6M187.2 75.3v2.9"/>
<path d="M189.2 78.2h1.8M189.2 71h1.8M191.9 63h-3v1.1l-1.9 1.9h-40.6l-.7 .8v.9M193 78.2h1.8M193 71h1.8M196.9 71l.8 .9h2.2M199.9 77.1h-1.9l-1.1 1.1M176.1 121.7v6.2"/>
</g>
<path d="M178.8 59.1h-4.1l-1.9 1.9v1M189.1 56.1h2.2M215.1 56.3l2.5 2.4v3.4l1.3 1.3h.6M215.1 66.7l1.9 1.8h2.5M215.1 61.5v1.9l2.6 2.6h1.8M215.1 71.9l1.7 1.7h7.7M224.5 76.1h-8.4l-1 1M219.5 86.3h5M219.5 88.8h5M219.5 83.7h5" fill="none" stroke="#000" stroke-width="1.3"/>
<g fill="none" stroke="#000" stroke-width=".63">
<path d="M129.4 69v.9l.9 .8h1.9M157 72.3v1l-1.4 1.4h-12.9l-2 2h-10.5M182.4 69.6h-.7l-.2 .2M184.1 69.6v1.5l-.5 .5h-2.5l-.6 .7v1.7M187.2 78.2v1.9l-4.5 4.5h-9.7l-5.8-5.7h-33.1M140.1 86.1h1.1l1.2 1.3h2.1M140.1 88.1v2.3M140.1 92.5v2.5M140.1 97v1.2M197.7 90.3h2.1l1.4 1.4h1.1M204.1 91.7h.8M210.8 90.2v.6"/>
<path d="M133.2 126.9v1.2l.5 .5h1.1M95.1 143.6v.8M97.5 146.2h-2.4v.7M104.5 144.4h-1l-.4 .4v.5"/>
</g>
<path d="M219.1 63.4h5.4M219.5 68.5h5M219.5 66h5M219.5 71h5M219.5 78.7h5M219.5 91.4h5M219.5 81.2h5" fill="none" stroke="#000" stroke-width="1.1"/>
<path d="M183.8 107h.2l.2-.2h1.1l.3 .4v3.6l.7 .6h.4l1-1M184.3 107.6l.1-.3h.7l.1 .1v3.6l.9 .9h.6l1 1" fill="none" stroke="#000" stroke-width=".2"/>
<use href="#words"/>
</svg>
